VERSION 5.7 ;
  NOWIREEXTENSIONATPIN ON ;
  DIVIDERCHAR "/" ;
  BUSBITCHARS "[]" ;
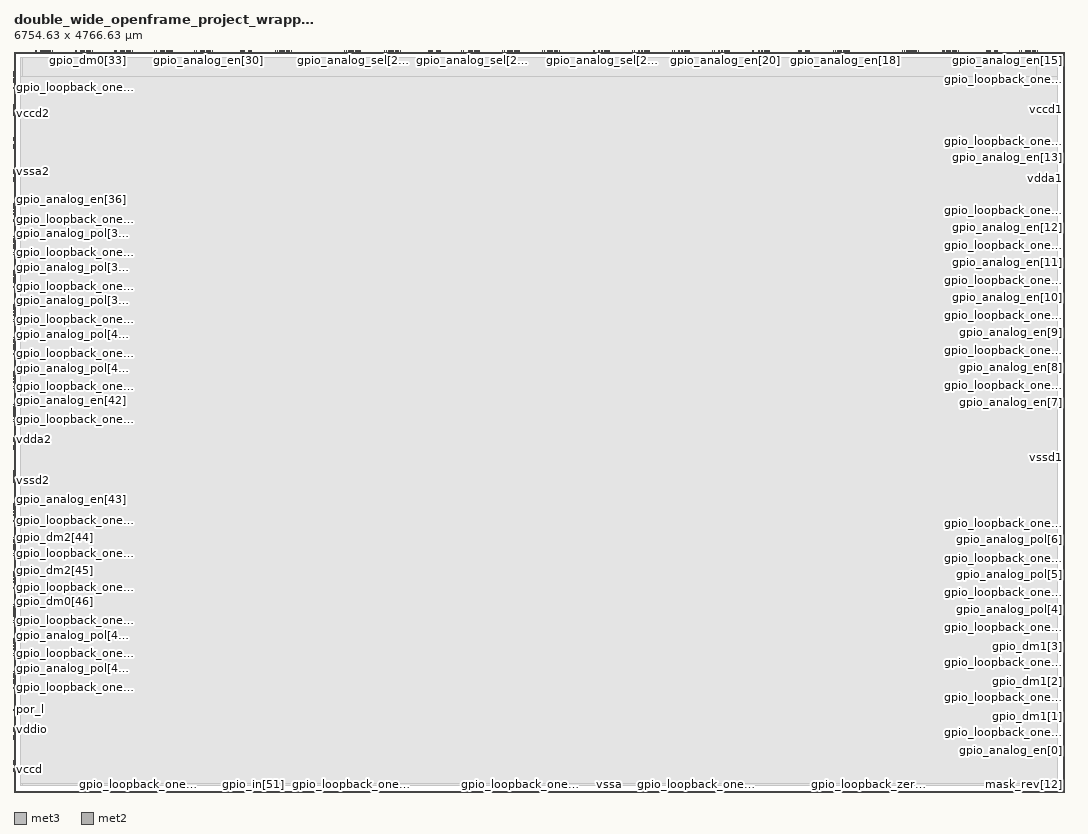
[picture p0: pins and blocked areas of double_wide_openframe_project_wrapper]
MACRO double_wide_openframe_project_wrapper
  CLASS BLOCK ;
  FOREIGN double_wide_openframe_project_wrapper ;
  ORIGIN 0.000 0.000 ;
  SIZE 6754.630 BY 4766.630 ;
  PIN analog_io[0]
    DIRECTION INOUT ;
    USE SIGNAL ;
    PORT
      LAYER met3 ;
        RECT 6754.330 306.190 6756.630 306.830 ;
    END
  END analog_io[0]
  PIN analog_io[10]
    DIRECTION INOUT ;
    USE SIGNAL ;
    PORT
      LAYER met3 ;
        RECT 6754.330 3222.190 6756.630 3222.830 ;
    END
  END analog_io[10]
  PIN analog_io[11]
    DIRECTION INOUT ;
    USE SIGNAL ;
    PORT
      LAYER met3 ;
        RECT 6754.330 3447.190 6756.630 3447.830 ;
    END
  END analog_io[11]
  PIN analog_io[12]
    DIRECTION INOUT ;
    USE SIGNAL ;
    PORT
      LAYER met3 ;
        RECT 6754.330 3672.190 6756.630 3672.830 ;
    END
  END analog_io[12]
  PIN analog_io[13]
    DIRECTION INOUT ;
    USE SIGNAL ;
    PORT
      LAYER met3 ;
        RECT 6754.330 4118.190 6756.630 4118.830 ;
    END
  END analog_io[13]
  PIN analog_io[14]
    DIRECTION INOUT ;
    USE SIGNAL ;
    PORT
      LAYER met3 ;
        RECT 6754.330 4564.190 6756.630 4564.830 ;
    END
  END analog_io[14]
  PIN analog_io[15]
    DIRECTION INOUT ;
    USE SIGNAL ;
    PORT
      LAYER met2 ;
        RECT 6569.800 4766.350 6570.440 4768.630 ;
    END
  END analog_io[15]
  PIN analog_io[16]
    DIRECTION INOUT ;
    USE SIGNAL ;
    PORT
      LAYER met2 ;
        RECT 6060.800 4766.350 6061.440 4768.630 ;
    END
  END analog_io[16]
  PIN analog_io[17]
    DIRECTION INOUT ;
    USE SIGNAL ;
    PORT
      LAYER met2 ;
        RECT 5803.800 4766.350 5804.440 4768.630 ;
    END
  END analog_io[17]
  PIN analog_io[18]
    DIRECTION INOUT ;
    USE SIGNAL ;
    PORT
      LAYER met2 ;
        RECT 5358.800 4766.350 5359.440 4768.630 ;
    END
  END analog_io[18]
  PIN analog_io[19]
    DIRECTION INOUT ;
    USE SIGNAL ;
    PORT
      LAYER met2 ;
        RECT 4849.800 4766.350 4850.440 4768.630 ;
    END
  END analog_io[19]
  PIN analog_io[1]
    DIRECTION INOUT ;
    USE SIGNAL ;
    PORT
      LAYER met3 ;
        RECT 6754.330 532.190 6756.630 532.830 ;
    END
  END analog_io[1]
  PIN analog_io[20]
    DIRECTION INOUT ;
    USE SIGNAL ;
    PORT
      LAYER met2 ;
        RECT 4591.800 4766.350 4592.440 4768.630 ;
    END
  END analog_io[20]
  PIN analog_io[21]
    DIRECTION INOUT ;
    USE SIGNAL ;
    PORT
      LAYER met2 ;
        RECT 4334.800 4766.350 4335.440 4768.630 ;
    END
  END analog_io[21]
  PIN analog_io[22]
    DIRECTION INOUT ;
    USE SIGNAL ;
    PORT
      LAYER met2 ;
        RECT 4077.800 4766.350 4078.440 4768.630 ;
    END
  END analog_io[22]
  PIN analog_io[23]
    DIRECTION INOUT ;
    USE SIGNAL ;
    PORT
      LAYER met2 ;
        RECT 3820.800 4766.350 3821.440 4768.630 ;
    END
  END analog_io[23]
  PIN analog_io[24]
    DIRECTION INOUT ;
    USE SIGNAL ;
    PORT
      LAYER met2 ;
        RECT 3495.800 4766.350 3496.440 4768.630 ;
    END
  END analog_io[24]
  PIN analog_io[25]
    DIRECTION INOUT ;
    USE SIGNAL ;
    PORT
      LAYER met2 ;
        RECT 3238.800 4766.350 3239.440 4768.630 ;
    END
  END analog_io[25]
  PIN analog_io[26]
    DIRECTION INOUT ;
    USE SIGNAL ;
    PORT
      LAYER met2 ;
        RECT 2981.800 4766.350 2982.440 4768.630 ;
    END
  END analog_io[26]
  PIN analog_io[27]
    DIRECTION INOUT ;
    USE SIGNAL ;
    PORT
      LAYER met2 ;
        RECT 2472.800 4766.350 2473.440 4768.630 ;
    END
  END analog_io[27]
  PIN analog_io[28]
    DIRECTION INOUT ;
    USE SIGNAL ;
    PORT
      LAYER met2 ;
        RECT 2215.800 4766.350 2216.440 4768.630 ;
    END
  END analog_io[28]
  PIN analog_io[29]
    DIRECTION INOUT ;
    USE SIGNAL ;
    PORT
      LAYER met2 ;
        RECT 1770.800 4766.350 1771.440 4768.630 ;
    END
  END analog_io[29]
  PIN analog_io[2]
    DIRECTION INOUT ;
    USE SIGNAL ;
    PORT
      LAYER met3 ;
        RECT 6754.330 757.190 6756.630 757.830 ;
    END
  END analog_io[2]
  PIN analog_io[30]
    DIRECTION INOUT ;
    USE SIGNAL ;
    PORT
      LAYER met2 ;
        RECT 1261.800 4766.350 1262.440 4768.630 ;
    END
  END analog_io[30]
  PIN analog_io[31]
    DIRECTION INOUT ;
    USE SIGNAL ;
    PORT
      LAYER met2 ;
        RECT 1003.800 4766.350 1004.440 4768.630 ;
    END
  END analog_io[31]
  PIN analog_io[32]
    DIRECTION INOUT ;
    USE SIGNAL ;
    PORT
      LAYER met2 ;
        RECT 746.800 4766.350 747.440 4768.630 ;
    END
  END analog_io[32]
  PIN analog_io[33]
    DIRECTION INOUT ;
    USE SIGNAL ;
    PORT
      LAYER met2 ;
        RECT 489.800 4766.350 490.440 4768.630 ;
    END
  END analog_io[33]
  PIN analog_io[34]
    DIRECTION INOUT ;
    USE SIGNAL ;
    PORT
      LAYER met2 ;
        RECT 232.800 4766.350 233.440 4768.630 ;
    END
  END analog_io[34]
  PIN analog_io[35]
    DIRECTION INOUT ;
    USE SIGNAL ;
    PORT
      LAYER met3 ;
        RECT -2.000 4622.800 0.300 4623.440 ;
    END
  END analog_io[35]
  PIN analog_io[36]
    DIRECTION INOUT ;
    USE SIGNAL ;
    PORT
      LAYER met3 ;
        RECT -2.000 3773.800 0.300 3774.440 ;
    END
  END analog_io[36]
  PIN analog_io[37]
    DIRECTION INOUT ;
    USE SIGNAL ;
    PORT
      LAYER met3 ;
        RECT -2.000 3557.800 0.300 3558.440 ;
    END
  END analog_io[37]
  PIN analog_io[38]
    DIRECTION INOUT ;
    USE SIGNAL ;
    PORT
      LAYER met3 ;
        RECT -2.000 3341.800 0.300 3342.440 ;
    END
  END analog_io[38]
  PIN analog_io[39]
    DIRECTION INOUT ;
    USE SIGNAL ;
    PORT
      LAYER met3 ;
        RECT -2.000 3125.800 0.300 3126.440 ;
    END
  END analog_io[39]
  PIN analog_io[3]
    DIRECTION INOUT ;
    USE SIGNAL ;
    PORT
      LAYER met3 ;
        RECT 6754.330 983.190 6756.630 983.830 ;
    END
  END analog_io[3]
  PIN analog_io[40]
    DIRECTION INOUT ;
    USE SIGNAL ;
    PORT
      LAYER met3 ;
        RECT -2.000 2909.800 0.300 2910.440 ;
    END
  END analog_io[40]
  PIN analog_io[41]
    DIRECTION INOUT ;
    USE SIGNAL ;
    PORT
      LAYER met3 ;
        RECT -2.000 2693.800 0.300 2694.440 ;
    END
  END analog_io[41]
  PIN analog_io[42]
    DIRECTION INOUT ;
    USE SIGNAL ;
    PORT
      LAYER met3 ;
        RECT -2.000 2477.800 0.300 2478.440 ;
    END
  END analog_io[42]
  PIN analog_io[43]
    DIRECTION INOUT ;
    USE SIGNAL ;
    PORT
      LAYER met3 ;
        RECT -2.000 1839.800 0.300 1840.440 ;
    END
  END analog_io[43]
  PIN analog_io[44]
    DIRECTION INOUT ;
    USE SIGNAL ;
    PORT
      LAYER met3 ;
        RECT -2.000 1623.800 0.300 1624.440 ;
    END
  END analog_io[44]
  PIN analog_io[45]
    DIRECTION INOUT ;
    USE SIGNAL ;
    PORT
      LAYER met3 ;
        RECT -2.000 1407.800 0.300 1408.440 ;
    END
  END analog_io[45]
  PIN analog_io[46]
    DIRECTION INOUT ;
    USE SIGNAL ;
    PORT
      LAYER met3 ;
        RECT -2.000 1191.800 0.300 1192.440 ;
    END
  END analog_io[46]
  PIN analog_io[47]
    DIRECTION INOUT ;
    USE SIGNAL ;
    PORT
      LAYER met3 ;
        RECT -2.000 975.800 0.300 976.440 ;
    END
  END analog_io[47]
  PIN analog_io[48]
    DIRECTION INOUT ;
    USE SIGNAL ;
    PORT
      LAYER met3 ;
        RECT -2.000 759.800 0.300 760.440 ;
    END
  END analog_io[48]
  PIN analog_io[49]
    DIRECTION INOUT ;
    USE SIGNAL ;
    PORT
      LAYER met2 ;
        RECT 738.190 -2.000 738.830 0.280 ;
    END
  END analog_io[49]
  PIN analog_io[4]
    DIRECTION INOUT ;
    USE SIGNAL ;
    PORT
      LAYER met3 ;
        RECT 6754.330 1208.190 6756.630 1208.830 ;
    END
  END analog_io[4]
  PIN analog_io[50]
    DIRECTION INOUT ;
    USE SIGNAL ;
    PORT
      LAYER met2 ;
        RECT 1281.190 -2.000 1281.830 0.280 ;
    END
  END analog_io[50]
  PIN analog_io[51]
    DIRECTION INOUT ;
    USE SIGNAL ;
    PORT
      LAYER met2 ;
        RECT 1555.190 -2.000 1555.830 0.280 ;
    END
  END analog_io[51]
  PIN analog_io[52]
    DIRECTION INOUT ;
    USE SIGNAL ;
    PORT
      LAYER met2 ;
        RECT 1829.190 -2.000 1829.830 0.280 ;
    END
  END analog_io[52]
  PIN analog_io[53]
    DIRECTION INOUT ;
    USE SIGNAL ;
    PORT
      LAYER met2 ;
        RECT 2103.190 -2.000 2103.830 0.280 ;
    END
  END analog_io[53]
  PIN analog_io[54]
    DIRECTION INOUT ;
    USE SIGNAL ;
    PORT
      LAYER met2 ;
        RECT 2377.190 -2.000 2377.830 0.280 ;
    END
  END analog_io[54]
  PIN analog_io[55]
    DIRECTION INOUT ;
    USE SIGNAL ;
    PORT
      LAYER met2 ;
        RECT 3191.670 -2.000 3192.310 0.280 ;
    END
  END analog_io[55]
  PIN analog_io[56]
    DIRECTION INOUT ;
    USE SIGNAL ;
    PORT
      LAYER met2 ;
        RECT 3465.670 -2.000 3466.310 0.280 ;
    END
  END analog_io[56]
  PIN analog_io[57]
    DIRECTION INOUT ;
    USE SIGNAL ;
    PORT
      LAYER met2 ;
        RECT 4326.190 -2.000 4326.830 0.280 ;
    END
  END analog_io[57]
  PIN analog_io[58]
    DIRECTION INOUT ;
    USE SIGNAL ;
    PORT
      LAYER met2 ;
        RECT 4869.190 -2.000 4869.830 0.280 ;
    END
  END analog_io[58]
  PIN analog_io[59]
    DIRECTION INOUT ;
    USE SIGNAL ;
    PORT
      LAYER met2 ;
        RECT 5143.190 -2.000 5143.830 0.280 ;
    END
  END analog_io[59]
  PIN analog_io[5]
    DIRECTION INOUT ;
    USE SIGNAL ;
    PORT
      LAYER met3 ;
        RECT 6754.330 1433.190 6756.630 1433.830 ;
    END
  END analog_io[5]
  PIN analog_io[60]
    DIRECTION INOUT ;
    USE SIGNAL ;
    PORT
      LAYER met2 ;
        RECT 5417.190 -2.000 5417.830 0.280 ;
    END
  END analog_io[60]
  PIN analog_io[61]
    DIRECTION INOUT ;
    USE SIGNAL ;
    PORT
      LAYER met2 ;
        RECT 5691.190 -2.000 5691.830 0.280 ;
    END
  END analog_io[61]
  PIN analog_io[62]
    DIRECTION INOUT ;
    USE SIGNAL ;
    PORT
      LAYER met2 ;
        RECT 5965.190 -2.000 5965.830 0.280 ;
    END
  END analog_io[62]
  PIN analog_io[6]
    DIRECTION INOUT ;
    USE SIGNAL ;
    PORT
      LAYER met3 ;
        RECT 6754.330 1659.190 6756.630 1659.830 ;
    END
  END analog_io[6]
  PIN analog_io[7]
    DIRECTION INOUT ;
    USE SIGNAL ;
    PORT
      LAYER met3 ;
        RECT 6754.330 2545.190 6756.630 2545.830 ;
    END
  END analog_io[7]
  PIN analog_io[8]
    DIRECTION INOUT ;
    USE SIGNAL ;
    PORT
      LAYER met3 ;
        RECT 6754.330 2771.190 6756.630 2771.830 ;
    END
  END analog_io[8]
  PIN analog_io[9]
    DIRECTION INOUT ;
    USE SIGNAL ;
    PORT
      LAYER met3 ;
        RECT 6754.330 2996.190 6756.630 2996.830 ;
    END
  END analog_io[9]
  PIN analog_noesd_io[0]
    DIRECTION INOUT ;
    USE SIGNAL ;
    PORT
      LAYER met3 ;
        RECT 6754.330 315.175 6756.630 316.245 ;
    END
  END analog_noesd_io[0]
  PIN analog_noesd_io[10]
    DIRECTION INOUT ;
    USE SIGNAL ;
    PORT
      LAYER met3 ;
        RECT 6754.330 3231.175 6756.630 3232.245 ;
    END
  END analog_noesd_io[10]
  PIN analog_noesd_io[11]
    DIRECTION INOUT ;
    USE SIGNAL ;
    PORT
      LAYER met3 ;
        RECT 6754.330 3456.175 6756.630 3457.245 ;
    END
  END analog_noesd_io[11]
  PIN analog_noesd_io[12]
    DIRECTION INOUT ;
    USE SIGNAL ;
    PORT
      LAYER met3 ;
        RECT 6754.330 3681.175 6756.630 3682.245 ;
    END
  END analog_noesd_io[12]
  PIN analog_noesd_io[13]
    DIRECTION INOUT ;
    USE SIGNAL ;
    PORT
      LAYER met3 ;
        RECT 6754.330 4127.175 6756.630 4128.245 ;
    END
  END analog_noesd_io[13]
  PIN analog_noesd_io[14]
    DIRECTION INOUT ;
    USE SIGNAL ;
    PORT
      LAYER met3 ;
        RECT 6754.330 4573.175 6756.630 4574.245 ;
    END
  END analog_noesd_io[14]
  PIN analog_noesd_io[15]
    DIRECTION INOUT ;
    USE SIGNAL ;
    PORT
      LAYER met2 ;
        RECT 6560.385 4766.350 6561.455 4768.630 ;
    END
  END analog_noesd_io[15]
  PIN analog_noesd_io[16]
    DIRECTION INOUT ;
    USE SIGNAL ;
    PORT
      LAYER met2 ;
        RECT 6051.385 4766.350 6052.455 4768.630 ;
    END
  END analog_noesd_io[16]
  PIN analog_noesd_io[17]
    DIRECTION INOUT ;
    USE SIGNAL ;
    PORT
      LAYER met2 ;
        RECT 5794.385 4766.350 5795.455 4768.630 ;
    END
  END analog_noesd_io[17]
  PIN analog_noesd_io[18]
    DIRECTION INOUT ;
    USE SIGNAL ;
    PORT
      LAYER met2 ;
        RECT 5349.385 4766.350 5350.455 4768.630 ;
    END
  END analog_noesd_io[18]
  PIN analog_noesd_io[19]
    DIRECTION INOUT ;
    USE SIGNAL ;
    PORT
      LAYER met2 ;
        RECT 4840.385 4766.350 4841.455 4768.630 ;
    END
  END analog_noesd_io[19]
  PIN analog_noesd_io[1]
    DIRECTION INOUT ;
    USE SIGNAL ;
    PORT
      LAYER met3 ;
        RECT 6754.330 541.175 6756.630 542.245 ;
    END
  END analog_noesd_io[1]
  PIN analog_noesd_io[20]
    DIRECTION INOUT ;
    USE SIGNAL ;
    PORT
      LAYER met2 ;
        RECT 4582.385 4766.350 4583.455 4768.630 ;
    END
  END analog_noesd_io[20]
  PIN analog_noesd_io[21]
    DIRECTION INOUT ;
    USE SIGNAL ;
    PORT
      LAYER met2 ;
        RECT 4325.385 4766.350 4326.455 4768.630 ;
    END
  END analog_noesd_io[21]
  PIN analog_noesd_io[22]
    DIRECTION INOUT ;
    USE SIGNAL ;
    PORT
      LAYER met2 ;
        RECT 4068.385 4766.350 4069.455 4768.630 ;
    END
  END analog_noesd_io[22]
  PIN analog_noesd_io[23]
    DIRECTION INOUT ;
    USE SIGNAL ;
    PORT
      LAYER met2 ;
        RECT 3811.385 4766.350 3812.455 4768.630 ;
    END
  END analog_noesd_io[23]
  PIN analog_noesd_io[24]
    DIRECTION INOUT ;
    USE SIGNAL ;
    PORT
      LAYER met2 ;
        RECT 3486.385 4766.350 3487.455 4768.630 ;
    END
  END analog_noesd_io[24]
  PIN analog_noesd_io[25]
    DIRECTION INOUT ;
    USE SIGNAL ;
    PORT
      LAYER met2 ;
        RECT 3229.385 4766.350 3230.455 4768.630 ;
    END
  END analog_noesd_io[25]
  PIN analog_noesd_io[26]
    DIRECTION INOUT ;
    USE SIGNAL ;
    PORT
      LAYER met2 ;
        RECT 2972.385 4766.350 2973.455 4768.630 ;
    END
  END analog_noesd_io[26]
  PIN analog_noesd_io[27]
    DIRECTION INOUT ;
    USE SIGNAL ;
    PORT
      LAYER met2 ;
        RECT 2463.385 4766.350 2464.455 4768.630 ;
    END
  END analog_noesd_io[27]
  PIN analog_noesd_io[28]
    DIRECTION INOUT ;
    USE SIGNAL ;
    PORT
      LAYER met2 ;
        RECT 2206.385 4766.350 2207.455 4768.630 ;
    END
  END analog_noesd_io[28]
  PIN analog_noesd_io[29]
    DIRECTION INOUT ;
    USE SIGNAL ;
    PORT
      LAYER met2 ;
        RECT 1761.385 4766.350 1762.455 4768.630 ;
    END
  END analog_noesd_io[29]
  PIN analog_noesd_io[2]
    DIRECTION INOUT ;
    USE SIGNAL ;
    PORT
      LAYER met3 ;
        RECT 6754.330 766.175 6756.630 767.245 ;
    END
  END analog_noesd_io[2]
  PIN analog_noesd_io[30]
    DIRECTION INOUT ;
    USE SIGNAL ;
    PORT
      LAYER met2 ;
        RECT 1252.385 4766.350 1253.455 4768.630 ;
    END
  END analog_noesd_io[30]
  PIN analog_noesd_io[31]
    DIRECTION INOUT ;
    USE SIGNAL ;
    PORT
      LAYER met2 ;
        RECT 994.385 4766.350 995.455 4768.630 ;
    END
  END analog_noesd_io[31]
  PIN analog_noesd_io[32]
    DIRECTION INOUT ;
    USE SIGNAL ;
    PORT
      LAYER met2 ;
        RECT 737.385 4766.350 738.455 4768.630 ;
    END
  END analog_noesd_io[32]
  PIN analog_noesd_io[33]
    DIRECTION INOUT ;
    USE SIGNAL ;
    PORT
      LAYER met2 ;
        RECT 480.385 4766.350 481.455 4768.630 ;
    END
  END analog_noesd_io[33]
  PIN analog_noesd_io[34]
    DIRECTION INOUT ;
    USE SIGNAL ;
    PORT
      LAYER met2 ;
        RECT 223.385 4766.350 224.455 4768.630 ;
    END
  END analog_noesd_io[34]
  PIN analog_noesd_io[35]
    DIRECTION INOUT ;
    USE SIGNAL ;
    PORT
      LAYER met3 ;
        RECT -2.000 4613.385 0.300 4614.455 ;
    END
  END analog_noesd_io[35]
  PIN analog_noesd_io[36]
    DIRECTION INOUT ;
    USE SIGNAL ;
    PORT
      LAYER met3 ;
        RECT -2.000 3764.385 0.300 3765.455 ;
    END
  END analog_noesd_io[36]
  PIN analog_noesd_io[37]
    DIRECTION INOUT ;
    USE SIGNAL ;
    PORT
      LAYER met3 ;
        RECT -2.000 3548.385 0.300 3549.455 ;
    END
  END analog_noesd_io[37]
  PIN analog_noesd_io[38]
    DIRECTION INOUT ;
    USE SIGNAL ;
    PORT
      LAYER met3 ;
        RECT -2.000 3332.385 0.300 3333.455 ;
    END
  END analog_noesd_io[38]
  PIN analog_noesd_io[39]
    DIRECTION INOUT ;
    USE SIGNAL ;
    PORT
      LAYER met3 ;
        RECT -2.000 3116.385 0.300 3117.455 ;
    END
  END analog_noesd_io[39]
  PIN analog_noesd_io[3]
    DIRECTION INOUT ;
    USE SIGNAL ;
    PORT
      LAYER met3 ;
        RECT 6754.330 992.175 6756.630 993.245 ;
    END
  END analog_noesd_io[3]
  PIN analog_noesd_io[40]
    DIRECTION INOUT ;
    USE SIGNAL ;
    PORT
      LAYER met3 ;
        RECT -2.000 2900.385 0.300 2901.455 ;
    END
  END analog_noesd_io[40]
  PIN analog_noesd_io[41]
    DIRECTION INOUT ;
    USE SIGNAL ;
    PORT
      LAYER met3 ;
        RECT -2.000 2684.385 0.300 2685.455 ;
    END
  END analog_noesd_io[41]
  PIN analog_noesd_io[42]
    DIRECTION INOUT ;
    USE SIGNAL ;
    PORT
      LAYER met3 ;
        RECT -2.000 2468.385 0.300 2469.455 ;
    END
  END analog_noesd_io[42]
  PIN analog_noesd_io[43]
    DIRECTION INOUT ;
    USE SIGNAL ;
    PORT
      LAYER met3 ;
        RECT -2.000 1830.385 0.300 1831.455 ;
    END
  END analog_noesd_io[43]
  PIN analog_noesd_io[44]
    DIRECTION INOUT ;
    USE SIGNAL ;
    PORT
      LAYER met3 ;
        RECT -2.000 1614.385 0.300 1615.455 ;
    END
  END analog_noesd_io[44]
  PIN analog_noesd_io[45]
    DIRECTION INOUT ;
    USE SIGNAL ;
    PORT
      LAYER met3 ;
        RECT -2.000 1398.385 0.300 1399.455 ;
    END
  END analog_noesd_io[45]
  PIN analog_noesd_io[46]
    DIRECTION INOUT ;
    USE SIGNAL ;
    PORT
      LAYER met3 ;
        RECT -2.000 1182.385 0.300 1183.455 ;
    END
  END analog_noesd_io[46]
  PIN analog_noesd_io[47]
    DIRECTION INOUT ;
    USE SIGNAL ;
    PORT
      LAYER met3 ;
        RECT -2.000 966.385 0.300 967.455 ;
    END
  END analog_noesd_io[47]
  PIN analog_noesd_io[48]
    DIRECTION INOUT ;
    USE SIGNAL ;
    PORT
      LAYER met3 ;
        RECT -2.000 750.385 0.300 751.455 ;
    END
  END analog_noesd_io[48]
  PIN analog_noesd_io[49]
    DIRECTION INOUT ;
    USE SIGNAL ;
    PORT
      LAYER met2 ;
        RECT 747.175 -2.000 748.245 0.280 ;
    END
  END analog_noesd_io[49]
  PIN analog_noesd_io[4]
    DIRECTION INOUT ;
    USE SIGNAL ;
    PORT
      LAYER met3 ;
        RECT 6754.330 1217.175 6756.630 1218.245 ;
    END
  END analog_noesd_io[4]
  PIN analog_noesd_io[50]
    DIRECTION INOUT ;
    USE SIGNAL ;
    PORT
      LAYER met2 ;
        RECT 1290.175 -2.000 1291.245 0.280 ;
    END
  END analog_noesd_io[50]
  PIN analog_noesd_io[51]
    DIRECTION INOUT ;
    USE SIGNAL ;
    PORT
      LAYER met2 ;
        RECT 1564.175 -2.000 1565.245 0.280 ;
    END
  END analog_noesd_io[51]
  PIN analog_noesd_io[52]
    DIRECTION INOUT ;
    USE SIGNAL ;
    PORT
      LAYER met2 ;
        RECT 1838.175 -2.000 1839.245 0.280 ;
    END
  END analog_noesd_io[52]
  PIN analog_noesd_io[53]
    DIRECTION INOUT ;
    USE SIGNAL ;
    PORT
      LAYER met2 ;
        RECT 2112.175 -2.000 2113.245 0.280 ;
    END
  END analog_noesd_io[53]
  PIN analog_noesd_io[54]
    DIRECTION INOUT ;
    USE SIGNAL ;
    PORT
      LAYER met2 ;
        RECT 2386.175 -2.000 2387.245 0.280 ;
    END
  END analog_noesd_io[54]
  PIN analog_noesd_io[55]
    DIRECTION INOUT ;
    USE SIGNAL ;
    PORT
      LAYER met2 ;
        RECT 3200.655 -2.000 3201.725 0.280 ;
    END
  END analog_noesd_io[55]
  PIN analog_noesd_io[56]
    DIRECTION INOUT ;
    USE SIGNAL ;
    PORT
      LAYER met2 ;
        RECT 3474.655 -2.000 3475.725 0.280 ;
    END
  END analog_noesd_io[56]
  PIN analog_noesd_io[57]
    DIRECTION INOUT ;
    USE SIGNAL ;
    PORT
      LAYER met2 ;
        RECT 4335.175 -2.000 4336.245 0.280 ;
    END
  END analog_noesd_io[57]
  PIN analog_noesd_io[58]
    DIRECTION INOUT ;
    USE SIGNAL ;
    PORT
      LAYER met2 ;
        RECT 4878.175 -2.000 4879.245 0.280 ;
    END
  END analog_noesd_io[58]
  PIN analog_noesd_io[59]
    DIRECTION INOUT ;
    USE SIGNAL ;
    PORT
      LAYER met2 ;
        RECT 5152.175 -2.000 5153.245 0.280 ;
    END
  END analog_noesd_io[59]
  PIN analog_noesd_io[5]
    DIRECTION INOUT ;
    USE SIGNAL ;
    PORT
      LAYER met3 ;
        RECT 6754.330 1442.175 6756.630 1443.245 ;
    END
  END analog_noesd_io[5]
  PIN analog_noesd_io[60]
    DIRECTION INOUT ;
    USE SIGNAL ;
    PORT
      LAYER met2 ;
        RECT 5426.175 -2.000 5427.245 0.280 ;
    END
  END analog_noesd_io[60]
  PIN analog_noesd_io[61]
    DIRECTION INOUT ;
    USE SIGNAL ;
    PORT
      LAYER met2 ;
        RECT 5700.175 -2.000 5701.245 0.280 ;
    END
  END analog_noesd_io[61]
  PIN analog_noesd_io[62]
    DIRECTION INOUT ;
    USE SIGNAL ;
    PORT
      LAYER met2 ;
        RECT 5974.175 -2.000 5975.245 0.280 ;
    END
  END analog_noesd_io[62]
  PIN analog_noesd_io[6]
    DIRECTION INOUT ;
    USE SIGNAL ;
    PORT
      LAYER met3 ;
        RECT 6754.330 1668.175 6756.630 1669.245 ;
    END
  END analog_noesd_io[6]
  PIN analog_noesd_io[7]
    DIRECTION INOUT ;
    USE SIGNAL ;
    PORT
      LAYER met3 ;
        RECT 6754.330 2554.175 6756.630 2555.245 ;
    END
  END analog_noesd_io[7]
  PIN analog_noesd_io[8]
    DIRECTION INOUT ;
    USE SIGNAL ;
    PORT
      LAYER met3 ;
        RECT 6754.330 2780.175 6756.630 2781.245 ;
    END
  END analog_noesd_io[8]
  PIN analog_noesd_io[9]
    DIRECTION INOUT ;
    USE SIGNAL ;
    PORT
      LAYER met3 ;
        RECT 6754.330 3005.175 6756.630 3006.245 ;
    END
  END analog_noesd_io[9]
  PIN gpio_analog_en[0]
    DIRECTION OUTPUT ;
    USE SIGNAL ;
    PORT
      LAYER met3 ;
        RECT 6754.330 318.300 6756.630 318.650 ;
    END
  END gpio_analog_en[0]
  PIN gpio_analog_en[10]
    DIRECTION OUTPUT ;
    USE SIGNAL ;
    PORT
      LAYER met3 ;
        RECT 6754.330 3234.300 6756.630 3234.650 ;
    END
  END gpio_analog_en[10]
  PIN gpio_analog_en[11]
    DIRECTION OUTPUT ;
    USE SIGNAL ;
    PORT
      LAYER met3 ;
        RECT 6754.330 3459.300 6756.630 3459.650 ;
    END
  END gpio_analog_en[11]
  PIN gpio_analog_en[12]
    DIRECTION OUTPUT ;
    USE SIGNAL ;
    PORT
      LAYER met3 ;
        RECT 6754.330 3684.300 6756.630 3684.650 ;
    END
  END gpio_analog_en[12]
  PIN gpio_analog_en[13]
    DIRECTION OUTPUT ;
    USE SIGNAL ;
    PORT
      LAYER met3 ;
        RECT 6754.330 4130.300 6756.630 4130.650 ;
    END
  END gpio_analog_en[13]
  PIN gpio_analog_en[14]
    DIRECTION OUTPUT ;
    USE SIGNAL ;
    PORT
      LAYER met3 ;
        RECT 6754.330 4576.300 6756.630 4576.650 ;
    END
  END gpio_analog_en[14]
  PIN gpio_analog_en[15]
    DIRECTION OUTPUT ;
    USE SIGNAL ;
    PORT
      LAYER met2 ;
        RECT 6558.020 4766.350 6558.300 4768.630 ;
    END
  END gpio_analog_en[15]
  PIN gpio_analog_en[16]
    DIRECTION OUTPUT ;
    USE SIGNAL ;
    PORT
      LAYER met2 ;
        RECT 6049.020 4766.350 6049.300 4768.630 ;
    END
  END gpio_analog_en[16]
  PIN gpio_analog_en[17]
    DIRECTION OUTPUT ;
    USE SIGNAL ;
    PORT
      LAYER met2 ;
        RECT 5792.020 4766.350 5792.300 4768.630 ;
    END
  END gpio_analog_en[17]
  PIN gpio_analog_en[18]
    DIRECTION OUTPUT ;
    USE SIGNAL ;
    PORT
      LAYER met2 ;
        RECT 5347.020 4766.350 5347.300 4768.630 ;
    END
  END gpio_analog_en[18]
  PIN gpio_analog_en[19]
    DIRECTION OUTPUT ;
    USE SIGNAL ;
    PORT
      LAYER met2 ;
        RECT 4838.020 4766.350 4838.300 4768.630 ;
    END
  END gpio_analog_en[19]
  PIN gpio_analog_en[1]
    DIRECTION OUTPUT ;
    USE SIGNAL ;
    PORT
      LAYER met3 ;
        RECT 6754.330 544.300 6756.630 544.650 ;
    END
  END gpio_analog_en[1]
  PIN gpio_analog_en[20]
    DIRECTION OUTPUT ;
    USE SIGNAL ;
    PORT
      LAYER met2 ;
        RECT 4580.020 4766.350 4580.300 4768.630 ;
    END
  END gpio_analog_en[20]
  PIN gpio_analog_en[21]
    DIRECTION OUTPUT ;
    USE SIGNAL ;
    PORT
      LAYER met2 ;
        RECT 4323.020 4766.350 4323.300 4768.630 ;
    END
  END gpio_analog_en[21]
  PIN gpio_analog_en[22]
    DIRECTION OUTPUT ;
    USE SIGNAL ;
    PORT
      LAYER met2 ;
        RECT 4066.020 4766.350 4066.300 4768.630 ;
    END
  END gpio_analog_en[22]
  PIN gpio_analog_en[23]
    DIRECTION OUTPUT ;
    USE SIGNAL ;
    PORT
      LAYER met2 ;
        RECT 3809.020 4766.350 3809.300 4768.630 ;
    END
  END gpio_analog_en[23]
  PIN gpio_analog_en[24]
    DIRECTION OUTPUT ;
    USE SIGNAL ;
    PORT
      LAYER met2 ;
        RECT 3484.020 4766.350 3484.300 4768.630 ;
    END
  END gpio_analog_en[24]
  PIN gpio_analog_en[25]
    DIRECTION OUTPUT ;
    USE SIGNAL ;
    PORT
      LAYER met2 ;
        RECT 3227.020 4766.350 3227.300 4768.630 ;
    END
  END gpio_analog_en[25]
  PIN gpio_analog_en[26]
    DIRECTION OUTPUT ;
    USE SIGNAL ;
    PORT
      LAYER met2 ;
        RECT 2970.020 4766.350 2970.300 4768.630 ;
    END
  END gpio_analog_en[26]
  PIN gpio_analog_en[27]
    DIRECTION OUTPUT ;
    USE SIGNAL ;
    PORT
      LAYER met2 ;
        RECT 2461.020 4766.350 2461.300 4768.630 ;
    END
  END gpio_analog_en[27]
  PIN gpio_analog_en[28]
    DIRECTION OUTPUT ;
    USE SIGNAL ;
    PORT
      LAYER met2 ;
        RECT 2204.020 4766.350 2204.300 4768.630 ;
    END
  END gpio_analog_en[28]
  PIN gpio_analog_en[29]
    DIRECTION OUTPUT ;
    USE SIGNAL ;
    PORT
      LAYER met2 ;
        RECT 1759.020 4766.350 1759.300 4768.630 ;
    END
  END gpio_analog_en[29]
  PIN gpio_analog_en[2]
    DIRECTION OUTPUT ;
    USE SIGNAL ;
    PORT
      LAYER met3 ;
        RECT 6754.330 769.300 6756.630 769.650 ;
    END
  END gpio_analog_en[2]
  PIN gpio_analog_en[30]
    DIRECTION OUTPUT ;
    USE SIGNAL ;
    PORT
      LAYER met2 ;
        RECT 1250.020 4766.350 1250.300 4768.630 ;
    END
  END gpio_analog_en[30]
  PIN gpio_analog_en[31]
    DIRECTION OUTPUT ;
    USE SIGNAL ;
    PORT
      LAYER met2 ;
        RECT 992.020 4766.350 992.300 4768.630 ;
    END
  END gpio_analog_en[31]
  PIN gpio_analog_en[32]
    DIRECTION OUTPUT ;
    USE SIGNAL ;
    PORT
      LAYER met2 ;
        RECT 735.020 4766.350 735.300 4768.630 ;
    END
  END gpio_analog_en[32]
  PIN gpio_analog_en[33]
    DIRECTION OUTPUT ;
    USE SIGNAL ;
    PORT
      LAYER met2 ;
        RECT 478.020 4766.350 478.300 4768.630 ;
    END
  END gpio_analog_en[33]
  PIN gpio_analog_en[34]
    DIRECTION OUTPUT ;
    USE SIGNAL ;
    PORT
      LAYER met2 ;
        RECT 221.020 4766.350 221.300 4768.630 ;
    END
  END gpio_analog_en[34]
  PIN gpio_analog_en[35]
    DIRECTION OUTPUT ;
    USE SIGNAL ;
    PORT
      LAYER met3 ;
        RECT -2.000 4610.980 0.300 4611.330 ;
    END
  END gpio_analog_en[35]
  PIN gpio_analog_en[36]
    DIRECTION OUTPUT ;
    USE SIGNAL ;
    PORT
      LAYER met3 ;
        RECT -2.000 3761.980 0.300 3762.330 ;
    END
  END gpio_analog_en[36]
  PIN gpio_analog_en[37]
    DIRECTION OUTPUT ;
    USE SIGNAL ;
    PORT
      LAYER met3 ;
        RECT -2.000 3545.980 0.300 3546.330 ;
    END
  END gpio_analog_en[37]
  PIN gpio_analog_en[38]
    DIRECTION OUTPUT ;
    USE SIGNAL ;
    PORT
      LAYER met3 ;
        RECT -2.000 3329.980 0.300 3330.330 ;
    END
  END gpio_analog_en[38]
  PIN gpio_analog_en[39]
    DIRECTION OUTPUT ;
    USE SIGNAL ;
    PORT
      LAYER met3 ;
        RECT -2.000 3113.980 0.300 3114.330 ;
    END
  END gpio_analog_en[39]
  PIN gpio_analog_en[3]
    DIRECTION OUTPUT ;
    USE SIGNAL ;
    PORT
      LAYER met3 ;
        RECT 6754.330 995.300 6756.630 995.650 ;
    END
  END gpio_analog_en[3]
  PIN gpio_analog_en[40]
    DIRECTION OUTPUT ;
    USE SIGNAL ;
    PORT
      LAYER met3 ;
        RECT -2.000 2897.980 0.300 2898.330 ;
    END
  END gpio_analog_en[40]
  PIN gpio_analog_en[41]
    DIRECTION OUTPUT ;
    USE SIGNAL ;
    PORT
      LAYER met3 ;
        RECT -2.000 2681.980 0.300 2682.330 ;
    END
  END gpio_analog_en[41]
  PIN gpio_analog_en[42]
    DIRECTION OUTPUT ;
    USE SIGNAL ;
    PORT
      LAYER met3 ;
        RECT -2.000 2465.980 0.300 2466.330 ;
    END
  END gpio_analog_en[42]
  PIN gpio_analog_en[43]
    DIRECTION OUTPUT ;
    USE SIGNAL ;
    PORT
      LAYER met3 ;
        RECT -2.000 1827.980 0.300 1828.330 ;
    END
  END gpio_analog_en[43]
  PIN gpio_analog_en[44]
    DIRECTION OUTPUT ;
    USE SIGNAL ;
    PORT
      LAYER met3 ;
        RECT -2.000 1611.980 0.300 1612.330 ;
    END
  END gpio_analog_en[44]
  PIN gpio_analog_en[45]
    DIRECTION OUTPUT ;
    USE SIGNAL ;
    PORT
      LAYER met3 ;
        RECT -2.000 1395.980 0.300 1396.330 ;
    END
  END gpio_analog_en[45]
  PIN gpio_analog_en[46]
    DIRECTION OUTPUT ;
    USE SIGNAL ;
    PORT
      LAYER met3 ;
        RECT -2.000 1179.980 0.300 1180.330 ;
    END
  END gpio_analog_en[46]
  PIN gpio_analog_en[47]
    DIRECTION OUTPUT ;
    USE SIGNAL ;
    PORT
      LAYER met3 ;
        RECT -2.000 963.980 0.300 964.330 ;
    END
  END gpio_analog_en[47]
  PIN gpio_analog_en[48]
    DIRECTION OUTPUT ;
    USE SIGNAL ;
    PORT
      LAYER met3 ;
        RECT -2.000 747.980 0.300 748.330 ;
    END
  END gpio_analog_en[48]
  PIN gpio_analog_en[49]
    DIRECTION OUTPUT ;
    USE SIGNAL ;
    PORT
      LAYER met2 ;
        RECT 750.330 -2.000 750.610 0.280 ;
    END
  END gpio_analog_en[49]
  PIN gpio_analog_en[4]
    DIRECTION OUTPUT ;
    USE SIGNAL ;
    PORT
      LAYER met3 ;
        RECT 6754.330 1220.300 6756.630 1220.650 ;
    END
  END gpio_analog_en[4]
  PIN gpio_analog_en[50]
    DIRECTION OUTPUT ;
    USE SIGNAL ;
    PORT
      LAYER met2 ;
        RECT 1293.330 -2.000 1293.610 0.280 ;
    END
  END gpio_analog_en[50]
  PIN gpio_analog_en[51]
    DIRECTION OUTPUT ;
    USE SIGNAL ;
    PORT
      LAYER met2 ;
        RECT 1567.330 -2.000 1567.610 0.280 ;
    END
  END gpio_analog_en[51]
  PIN gpio_analog_en[52]
    DIRECTION OUTPUT ;
    USE SIGNAL ;
    PORT
      LAYER met2 ;
        RECT 1841.330 -2.000 1841.610 0.280 ;
    END
  END gpio_analog_en[52]
  PIN gpio_analog_en[53]
    DIRECTION OUTPUT ;
    USE SIGNAL ;
    PORT
      LAYER met2 ;
        RECT 2115.330 -2.000 2115.610 0.280 ;
    END
  END gpio_analog_en[53]
  PIN gpio_analog_en[54]
    DIRECTION OUTPUT ;
    USE SIGNAL ;
    PORT
      LAYER met2 ;
        RECT 2389.330 -2.000 2389.610 0.280 ;
    END
  END gpio_analog_en[54]
  PIN gpio_analog_en[55]
    DIRECTION OUTPUT ;
    USE SIGNAL ;
    PORT
      LAYER met2 ;
        RECT 3203.810 -2.000 3204.090 0.280 ;
    END
  END gpio_analog_en[55]
  PIN gpio_analog_en[56]
    DIRECTION OUTPUT ;
    USE SIGNAL ;
    PORT
      LAYER met2 ;
        RECT 3477.810 -2.000 3478.090 0.280 ;
    END
  END gpio_analog_en[56]
  PIN gpio_analog_en[57]
    DIRECTION OUTPUT ;
    USE SIGNAL ;
    PORT
      LAYER met2 ;
        RECT 4338.330 -2.000 4338.610 0.280 ;
    END
  END gpio_analog_en[57]
  PIN gpio_analog_en[58]
    DIRECTION OUTPUT ;
    USE SIGNAL ;
    PORT
      LAYER met2 ;
        RECT 4881.330 -2.000 4881.610 0.280 ;
    END
  END gpio_analog_en[58]
  PIN gpio_analog_en[59]
    DIRECTION OUTPUT ;
    USE SIGNAL ;
    PORT
      LAYER met2 ;
        RECT 5155.330 -2.000 5155.610 0.280 ;
    END
  END gpio_analog_en[59]
  PIN gpio_analog_en[5]
    DIRECTION OUTPUT ;
    USE SIGNAL ;
    PORT
      LAYER met3 ;
        RECT 6754.330 1445.300 6756.630 1445.650 ;
    END
  END gpio_analog_en[5]
  PIN gpio_analog_en[60]
    DIRECTION OUTPUT ;
    USE SIGNAL ;
    PORT
      LAYER met2 ;
        RECT 5429.330 -2.000 5429.610 0.280 ;
    END
  END gpio_analog_en[60]
  PIN gpio_analog_en[61]
    DIRECTION OUTPUT ;
    USE SIGNAL ;
    PORT
      LAYER met2 ;
        RECT 5703.330 -2.000 5703.610 0.280 ;
    END
  END gpio_analog_en[61]
  PIN gpio_analog_en[62]
    DIRECTION OUTPUT ;
    USE SIGNAL ;
    PORT
      LAYER met2 ;
        RECT 5977.330 -2.000 5977.610 0.280 ;
    END
  END gpio_analog_en[62]
  PIN gpio_analog_en[6]
    DIRECTION OUTPUT ;
    USE SIGNAL ;
    PORT
      LAYER met3 ;
        RECT 6754.330 1671.300 6756.630 1671.650 ;
    END
  END gpio_analog_en[6]
  PIN gpio_analog_en[7]
    DIRECTION OUTPUT ;
    USE SIGNAL ;
    PORT
      LAYER met3 ;
        RECT 6754.330 2557.300 6756.630 2557.650 ;
    END
  END gpio_analog_en[7]
  PIN gpio_analog_en[8]
    DIRECTION OUTPUT ;
    USE SIGNAL ;
    PORT
      LAYER met3 ;
        RECT 6754.330 2783.300 6756.630 2783.650 ;
    END
  END gpio_analog_en[8]
  PIN gpio_analog_en[9]
    DIRECTION OUTPUT ;
    USE SIGNAL ;
    PORT
      LAYER met3 ;
        RECT 6754.330 3008.300 6756.630 3008.650 ;
    END
  END gpio_analog_en[9]
  PIN gpio_analog_pol[0]
    DIRECTION OUTPUT ;
    USE SIGNAL ;
    PORT
      LAYER met3 ;
        RECT 6754.330 324.740 6756.630 325.090 ;
    END
  END gpio_analog_pol[0]
  PIN gpio_analog_pol[10]
    DIRECTION OUTPUT ;
    USE SIGNAL ;
    PORT
      LAYER met3 ;
        RECT 6754.330 3240.740 6756.630 3241.090 ;
    END
  END gpio_analog_pol[10]
  PIN gpio_analog_pol[11]
    DIRECTION OUTPUT ;
    USE SIGNAL ;
    PORT
      LAYER met3 ;
        RECT 6754.330 3465.740 6756.630 3466.090 ;
    END
  END gpio_analog_pol[11]
  PIN gpio_analog_pol[12]
    DIRECTION OUTPUT ;
    USE SIGNAL ;
    PORT
      LAYER met3 ;
        RECT 6754.330 3690.740 6756.630 3691.090 ;
    END
  END gpio_analog_pol[12]
  PIN gpio_analog_pol[13]
    DIRECTION OUTPUT ;
    USE SIGNAL ;
    PORT
      LAYER met3 ;
        RECT 6754.330 4136.740 6756.630 4137.090 ;
    END
  END gpio_analog_pol[13]
  PIN gpio_analog_pol[14]
    DIRECTION OUTPUT ;
    USE SIGNAL ;
    PORT
      LAYER met3 ;
        RECT 6754.330 4582.740 6756.630 4583.090 ;
    END
  END gpio_analog_pol[14]
  PIN gpio_analog_pol[15]
    DIRECTION OUTPUT ;
    USE SIGNAL ;
    PORT
      LAYER met2 ;
        RECT 6551.580 4766.350 6551.860 4768.630 ;
    END
  END gpio_analog_pol[15]
  PIN gpio_analog_pol[16]
    DIRECTION OUTPUT ;
    USE SIGNAL ;
    PORT
      LAYER met2 ;
        RECT 6042.580 4766.350 6042.860 4768.630 ;
    END
  END gpio_analog_pol[16]
  PIN gpio_analog_pol[17]
    DIRECTION OUTPUT ;
    USE SIGNAL ;
    PORT
      LAYER met2 ;
        RECT 5785.580 4766.350 5785.860 4768.630 ;
    END
  END gpio_analog_pol[17]
  PIN gpio_analog_pol[18]
    DIRECTION OUTPUT ;
    USE SIGNAL ;
    PORT
      LAYER met2 ;
        RECT 5340.580 4766.350 5340.860 4768.630 ;
    END
  END gpio_analog_pol[18]
  PIN gpio_analog_pol[19]
    DIRECTION OUTPUT ;
    USE SIGNAL ;
    PORT
      LAYER met2 ;
        RECT 4831.580 4766.350 4831.860 4768.630 ;
    END
  END gpio_analog_pol[19]
  PIN gpio_analog_pol[1]
    DIRECTION OUTPUT ;
    USE SIGNAL ;
    PORT
      LAYER met3 ;
        RECT 6754.330 550.740 6756.630 551.090 ;
    END
  END gpio_analog_pol[1]
  PIN gpio_analog_pol[20]
    DIRECTION OUTPUT ;
    USE SIGNAL ;
    PORT
      LAYER met2 ;
        RECT 4573.580 4766.350 4573.860 4768.630 ;
    END
  END gpio_analog_pol[20]
  PIN gpio_analog_pol[21]
    DIRECTION OUTPUT ;
    USE SIGNAL ;
    PORT
      LAYER met2 ;
        RECT 4316.580 4766.350 4316.860 4768.630 ;
    END
  END gpio_analog_pol[21]
  PIN gpio_analog_pol[22]
    DIRECTION OUTPUT ;
    USE SIGNAL ;
    PORT
      LAYER met2 ;
        RECT 4059.580 4766.350 4059.860 4768.630 ;
    END
  END gpio_analog_pol[22]
  PIN gpio_analog_pol[23]
    DIRECTION OUTPUT ;
    USE SIGNAL ;
    PORT
      LAYER met2 ;
        RECT 3802.580 4766.350 3802.860 4768.630 ;
    END
  END gpio_analog_pol[23]
  PIN gpio_analog_pol[24]
    DIRECTION OUTPUT ;
    USE SIGNAL ;
    PORT
      LAYER met2 ;
        RECT 3477.580 4766.350 3477.860 4768.630 ;
    END
  END gpio_analog_pol[24]
  PIN gpio_analog_pol[25]
    DIRECTION OUTPUT ;
    USE SIGNAL ;
    PORT
      LAYER met2 ;
        RECT 3220.580 4766.350 3220.860 4768.630 ;
    END
  END gpio_analog_pol[25]
  PIN gpio_analog_pol[26]
    DIRECTION OUTPUT ;
    USE SIGNAL ;
    PORT
      LAYER met2 ;
        RECT 2963.580 4766.350 2963.860 4768.630 ;
    END
  END gpio_analog_pol[26]
  PIN gpio_analog_pol[27]
    DIRECTION OUTPUT ;
    USE SIGNAL ;
    PORT
      LAYER met2 ;
        RECT 2454.580 4766.350 2454.860 4768.630 ;
    END
  END gpio_analog_pol[27]
  PIN gpio_analog_pol[28]
    DIRECTION OUTPUT ;
    USE SIGNAL ;
    PORT
      LAYER met2 ;
        RECT 2197.580 4766.350 2197.860 4768.630 ;
    END
  END gpio_analog_pol[28]
  PIN gpio_analog_pol[29]
    DIRECTION OUTPUT ;
    USE SIGNAL ;
    PORT
      LAYER met2 ;
        RECT 1752.580 4766.350 1752.860 4768.630 ;
    END
  END gpio_analog_pol[29]
  PIN gpio_analog_pol[2]
    DIRECTION OUTPUT ;
    USE SIGNAL ;
    PORT
      LAYER met3 ;
        RECT 6754.330 775.740 6756.630 776.090 ;
    END
  END gpio_analog_pol[2]
  PIN gpio_analog_pol[30]
    DIRECTION OUTPUT ;
    USE SIGNAL ;
    PORT
      LAYER met2 ;
        RECT 1243.580 4766.350 1243.860 4768.630 ;
    END
  END gpio_analog_pol[30]
  PIN gpio_analog_pol[31]
    DIRECTION OUTPUT ;
    USE SIGNAL ;
    PORT
      LAYER met2 ;
        RECT 985.580 4766.350 985.860 4768.630 ;
    END
  END gpio_analog_pol[31]
  PIN gpio_analog_pol[32]
    DIRECTION OUTPUT ;
    USE SIGNAL ;
    PORT
      LAYER met2 ;
        RECT 728.580 4766.350 728.860 4768.630 ;
    END
  END gpio_analog_pol[32]
  PIN gpio_analog_pol[33]
    DIRECTION OUTPUT ;
    USE SIGNAL ;
    PORT
      LAYER met2 ;
        RECT 471.580 4766.350 471.860 4768.630 ;
    END
  END gpio_analog_pol[33]
  PIN gpio_analog_pol[34]
    DIRECTION OUTPUT ;
    USE SIGNAL ;
    PORT
      LAYER met2 ;
        RECT 214.580 4766.350 214.860 4768.630 ;
    END
  END gpio_analog_pol[34]
  PIN gpio_analog_pol[35]
    DIRECTION OUTPUT ;
    USE SIGNAL ;
    PORT
      LAYER met3 ;
        RECT -2.000 4604.540 0.300 4604.890 ;
    END
  END gpio_analog_pol[35]
  PIN gpio_analog_pol[36]
    DIRECTION OUTPUT ;
    USE SIGNAL ;
    PORT
      LAYER met3 ;
        RECT -2.000 3755.540 0.300 3755.890 ;
    END
  END gpio_analog_pol[36]
  PIN gpio_analog_pol[37]
    DIRECTION OUTPUT ;
    USE SIGNAL ;
    PORT
      LAYER met3 ;
        RECT -2.000 3539.540 0.300 3539.890 ;
    END
  END gpio_analog_pol[37]
  PIN gpio_analog_pol[38]
    DIRECTION OUTPUT ;
    USE SIGNAL ;
    PORT
      LAYER met3 ;
        RECT -2.000 3323.540 0.300 3323.890 ;
    END
  END gpio_analog_pol[38]
  PIN gpio_analog_pol[39]
    DIRECTION OUTPUT ;
    USE SIGNAL ;
    PORT
      LAYER met3 ;
        RECT -2.000 3107.540 0.300 3107.890 ;
    END
  END gpio_analog_pol[39]
  PIN gpio_analog_pol[3]
    DIRECTION OUTPUT ;
    USE SIGNAL ;
    PORT
      LAYER met3 ;
        RECT 6754.330 1001.740 6756.630 1002.090 ;
    END
  END gpio_analog_pol[3]
  PIN gpio_analog_pol[40]
    DIRECTION OUTPUT ;
    USE SIGNAL ;
    PORT
      LAYER met3 ;
        RECT -2.000 2891.540 0.300 2891.890 ;
    END
  END gpio_analog_pol[40]
  PIN gpio_analog_pol[41]
    DIRECTION OUTPUT ;
    USE SIGNAL ;
    PORT
      LAYER met3 ;
        RECT -2.000 2675.540 0.300 2675.890 ;
    END
  END gpio_analog_pol[41]
  PIN gpio_analog_pol[42]
    DIRECTION OUTPUT ;
    USE SIGNAL ;
    PORT
      LAYER met3 ;
        RECT -2.000 2459.540 0.300 2459.890 ;
    END
  END gpio_analog_pol[42]
  PIN gpio_analog_pol[43]
    DIRECTION OUTPUT ;
    USE SIGNAL ;
    PORT
      LAYER met3 ;
        RECT -2.000 1821.540 0.300 1821.890 ;
    END
  END gpio_analog_pol[43]
  PIN gpio_analog_pol[44]
    DIRECTION OUTPUT ;
    USE SIGNAL ;
    PORT
      LAYER met3 ;
        RECT -2.000 1605.540 0.300 1605.890 ;
    END
  END gpio_analog_pol[44]
  PIN gpio_analog_pol[45]
    DIRECTION OUTPUT ;
    USE SIGNAL ;
    PORT
      LAYER met3 ;
        RECT -2.000 1389.540 0.300 1389.890 ;
    END
  END gpio_analog_pol[45]
  PIN gpio_analog_pol[46]
    DIRECTION OUTPUT ;
    USE SIGNAL ;
    PORT
      LAYER met3 ;
        RECT -2.000 1173.540 0.300 1173.890 ;
    END
  END gpio_analog_pol[46]
  PIN gpio_analog_pol[47]
    DIRECTION OUTPUT ;
    USE SIGNAL ;
    PORT
      LAYER met3 ;
        RECT -2.000 957.540 0.300 957.890 ;
    END
  END gpio_analog_pol[47]
  PIN gpio_analog_pol[48]
    DIRECTION OUTPUT ;
    USE SIGNAL ;
    PORT
      LAYER met3 ;
        RECT -2.000 741.540 0.300 741.890 ;
    END
  END gpio_analog_pol[48]
  PIN gpio_analog_pol[49]
    DIRECTION OUTPUT ;
    USE SIGNAL ;
    PORT
      LAYER met2 ;
        RECT 756.770 -2.000 757.050 0.280 ;
    END
  END gpio_analog_pol[49]
  PIN gpio_analog_pol[4]
    DIRECTION OUTPUT ;
    USE SIGNAL ;
    PORT
      LAYER met3 ;
        RECT 6754.330 1226.740 6756.630 1227.090 ;
    END
  END gpio_analog_pol[4]
  PIN gpio_analog_pol[50]
    DIRECTION OUTPUT ;
    USE SIGNAL ;
    PORT
      LAYER met2 ;
        RECT 1299.770 -2.000 1300.050 0.280 ;
    END
  END gpio_analog_pol[50]
  PIN gpio_analog_pol[51]
    DIRECTION OUTPUT ;
    USE SIGNAL ;
    PORT
      LAYER met2 ;
        RECT 1573.770 -2.000 1574.050 0.280 ;
    END
  END gpio_analog_pol[51]
  PIN gpio_analog_pol[52]
    DIRECTION OUTPUT ;
    USE SIGNAL ;
    PORT
      LAYER met2 ;
        RECT 1847.770 -2.000 1848.050 0.280 ;
    END
  END gpio_analog_pol[52]
  PIN gpio_analog_pol[53]
    DIRECTION OUTPUT ;
    USE SIGNAL ;
    PORT
      LAYER met2 ;
        RECT 2121.770 -2.000 2122.050 0.280 ;
    END
  END gpio_analog_pol[53]
  PIN gpio_analog_pol[54]
    DIRECTION OUTPUT ;
    USE SIGNAL ;
    PORT
      LAYER met2 ;
        RECT 2395.770 -2.000 2396.050 0.280 ;
    END
  END gpio_analog_pol[54]
  PIN gpio_analog_pol[55]
    DIRECTION OUTPUT ;
    USE SIGNAL ;
    PORT
      LAYER met2 ;
        RECT 3210.250 -2.000 3210.530 0.280 ;
    END
  END gpio_analog_pol[55]
  PIN gpio_analog_pol[56]
    DIRECTION OUTPUT ;
    USE SIGNAL ;
    PORT
      LAYER met2 ;
        RECT 3484.250 -2.000 3484.530 0.280 ;
    END
  END gpio_analog_pol[56]
  PIN gpio_analog_pol[57]
    DIRECTION OUTPUT ;
    USE SIGNAL ;
    PORT
      LAYER met2 ;
        RECT 4344.770 -2.000 4345.050 0.280 ;
    END
  END gpio_analog_pol[57]
  PIN gpio_analog_pol[58]
    DIRECTION OUTPUT ;
    USE SIGNAL ;
    PORT
      LAYER met2 ;
        RECT 4887.770 -2.000 4888.050 0.280 ;
    END
  END gpio_analog_pol[58]
  PIN gpio_analog_pol[59]
    DIRECTION OUTPUT ;
    USE SIGNAL ;
    PORT
      LAYER met2 ;
        RECT 5161.770 -2.000 5162.050 0.280 ;
    END
  END gpio_analog_pol[59]
  PIN gpio_analog_pol[5]
    DIRECTION OUTPUT ;
    USE SIGNAL ;
    PORT
      LAYER met3 ;
        RECT 6754.330 1451.740 6756.630 1452.090 ;
    END
  END gpio_analog_pol[5]
  PIN gpio_analog_pol[60]
    DIRECTION OUTPUT ;
    USE SIGNAL ;
    PORT
      LAYER met2 ;
        RECT 5435.770 -2.000 5436.050 0.280 ;
    END
  END gpio_analog_pol[60]
  PIN gpio_analog_pol[61]
    DIRECTION OUTPUT ;
    USE SIGNAL ;
    PORT
      LAYER met2 ;
        RECT 5709.770 -2.000 5710.050 0.280 ;
    END
  END gpio_analog_pol[61]
  PIN gpio_analog_pol[62]
    DIRECTION OUTPUT ;
    USE SIGNAL ;
    PORT
      LAYER met2 ;
        RECT 5983.770 -2.000 5984.050 0.280 ;
    END
  END gpio_analog_pol[62]
  PIN gpio_analog_pol[6]
    DIRECTION OUTPUT ;
    USE SIGNAL ;
    PORT
      LAYER met3 ;
        RECT 6754.330 1677.740 6756.630 1678.090 ;
    END
  END gpio_analog_pol[6]
  PIN gpio_analog_pol[7]
    DIRECTION OUTPUT ;
    USE SIGNAL ;
    PORT
      LAYER met3 ;
        RECT 6754.330 2563.740 6756.630 2564.090 ;
    END
  END gpio_analog_pol[7]
  PIN gpio_analog_pol[8]
    DIRECTION OUTPUT ;
    USE SIGNAL ;
    PORT
      LAYER met3 ;
        RECT 6754.330 2789.740 6756.630 2790.090 ;
    END
  END gpio_analog_pol[8]
  PIN gpio_analog_pol[9]
    DIRECTION OUTPUT ;
    USE SIGNAL ;
    PORT
      LAYER met3 ;
        RECT 6754.330 3014.740 6756.630 3015.090 ;
    END
  END gpio_analog_pol[9]
  PIN gpio_analog_sel[0]
    DIRECTION OUTPUT ;
    USE SIGNAL ;
    PORT
      LAYER met3 ;
        RECT 6754.330 339.920 6756.630 340.270 ;
    END
  END gpio_analog_sel[0]
  PIN gpio_analog_sel[10]
    DIRECTION OUTPUT ;
    USE SIGNAL ;
    PORT
      LAYER met3 ;
        RECT 6754.330 3255.920 6756.630 3256.270 ;
    END
  END gpio_analog_sel[10]
  PIN gpio_analog_sel[11]
    DIRECTION OUTPUT ;
    USE SIGNAL ;
    PORT
      LAYER met3 ;
        RECT 6754.330 3480.920 6756.630 3481.270 ;
    END
  END gpio_analog_sel[11]
  PIN gpio_analog_sel[12]
    DIRECTION OUTPUT ;
    USE SIGNAL ;
    PORT
      LAYER met3 ;
        RECT 6754.330 3705.920 6756.630 3706.270 ;
    END
  END gpio_analog_sel[12]
  PIN gpio_analog_sel[13]
    DIRECTION OUTPUT ;
    USE SIGNAL ;
    PORT
      LAYER met3 ;
        RECT 6754.330 4151.920 6756.630 4152.270 ;
    END
  END gpio_analog_sel[13]
  PIN gpio_analog_sel[14]
    DIRECTION OUTPUT ;
    USE SIGNAL ;
    PORT
      LAYER met3 ;
        RECT 6754.330 4597.920 6756.630 4598.270 ;
    END
  END gpio_analog_sel[14]
  PIN gpio_analog_sel[15]
    DIRECTION OUTPUT ;
    USE SIGNAL ;
    PORT
      LAYER met2 ;
        RECT 6536.400 4766.350 6536.680 4768.630 ;
    END
  END gpio_analog_sel[15]
  PIN gpio_analog_sel[16]
    DIRECTION OUTPUT ;
    USE SIGNAL ;
    PORT
      LAYER met2 ;
        RECT 6027.400 4766.350 6027.680 4768.630 ;
    END
  END gpio_analog_sel[16]
  PIN gpio_analog_sel[17]
    DIRECTION OUTPUT ;
    USE SIGNAL ;
    PORT
      LAYER met2 ;
        RECT 5770.400 4766.350 5770.680 4768.630 ;
    END
  END gpio_analog_sel[17]
  PIN gpio_analog_sel[18]
    DIRECTION OUTPUT ;
    USE SIGNAL ;
    PORT
      LAYER met2 ;
        RECT 5325.400 4766.350 5325.680 4768.630 ;
    END
  END gpio_analog_sel[18]
  PIN gpio_analog_sel[19]
    DIRECTION OUTPUT ;
    USE SIGNAL ;
    PORT
      LAYER met2 ;
        RECT 4816.400 4766.350 4816.680 4768.630 ;
    END
  END gpio_analog_sel[19]
  PIN gpio_analog_sel[1]
    DIRECTION OUTPUT ;
    USE SIGNAL ;
    PORT
      LAYER met3 ;
        RECT 6754.330 565.920 6756.630 566.270 ;
    END
  END gpio_analog_sel[1]
  PIN gpio_analog_sel[20]
    DIRECTION OUTPUT ;
    USE SIGNAL ;
    PORT
      LAYER met2 ;
        RECT 4558.400 4766.350 4558.680 4768.630 ;
    END
  END gpio_analog_sel[20]
  PIN gpio_analog_sel[21]
    DIRECTION OUTPUT ;
    USE SIGNAL ;
    PORT
      LAYER met2 ;
        RECT 4301.400 4766.350 4301.680 4768.630 ;
    END
  END gpio_analog_sel[21]
  PIN gpio_analog_sel[22]
    DIRECTION OUTPUT ;
    USE SIGNAL ;
    PORT
      LAYER met2 ;
        RECT 4044.400 4766.350 4044.680 4768.630 ;
    END
  END gpio_analog_sel[22]
  PIN gpio_analog_sel[23]
    DIRECTION OUTPUT ;
    USE SIGNAL ;
    PORT
      LAYER met2 ;
        RECT 3787.400 4766.350 3787.680 4768.630 ;
    END
  END gpio_analog_sel[23]
  PIN gpio_analog_sel[24]
    DIRECTION OUTPUT ;
    USE SIGNAL ;
    PORT
      LAYER met2 ;
        RECT 3462.400 4766.350 3462.680 4768.630 ;
    END
  END gpio_analog_sel[24]
  PIN gpio_analog_sel[25]
    DIRECTION OUTPUT ;
    USE SIGNAL ;
    PORT
      LAYER met2 ;
        RECT 3205.400 4766.350 3205.680 4768.630 ;
    END
  END gpio_analog_sel[25]
  PIN gpio_analog_sel[26]
    DIRECTION OUTPUT ;
    USE SIGNAL ;
    PORT
      LAYER met2 ;
        RECT 2948.400 4766.350 2948.680 4768.630 ;
    END
  END gpio_analog_sel[26]
  PIN gpio_analog_sel[27]
    DIRECTION OUTPUT ;
    USE SIGNAL ;
    PORT
      LAYER met2 ;
        RECT 2439.400 4766.350 2439.680 4768.630 ;
    END
  END gpio_analog_sel[27]
  PIN gpio_analog_sel[28]
    DIRECTION OUTPUT ;
    USE SIGNAL ;
    PORT
      LAYER met2 ;
        RECT 2182.400 4766.350 2182.680 4768.630 ;
    END
  END gpio_analog_sel[28]
  PIN gpio_analog_sel[29]
    DIRECTION OUTPUT ;
    USE SIGNAL ;
    PORT
      LAYER met2 ;
        RECT 1737.400 4766.350 1737.680 4768.630 ;
    END
  END gpio_analog_sel[29]
  PIN gpio_analog_sel[2]
    DIRECTION OUTPUT ;
    USE SIGNAL ;
    PORT
      LAYER met3 ;
        RECT 6754.330 790.920 6756.630 791.270 ;
    END
  END gpio_analog_sel[2]
  PIN gpio_analog_sel[30]
    DIRECTION OUTPUT ;
    USE SIGNAL ;
    PORT
      LAYER met2 ;
        RECT 1228.400 4766.350 1228.680 4768.630 ;
    END
  END gpio_analog_sel[30]
  PIN gpio_analog_sel[31]
    DIRECTION OUTPUT ;
    USE SIGNAL ;
    PORT
      LAYER met2 ;
        RECT 970.400 4766.350 970.680 4768.630 ;
    END
  END gpio_analog_sel[31]
  PIN gpio_analog_sel[32]
    DIRECTION OUTPUT ;
    USE SIGNAL ;
    PORT
      LAYER met2 ;
        RECT 713.400 4766.350 713.680 4768.630 ;
    END
  END gpio_analog_sel[32]
  PIN gpio_analog_sel[33]
    DIRECTION OUTPUT ;
    USE SIGNAL ;
    PORT
      LAYER met2 ;
        RECT 456.400 4766.350 456.680 4768.630 ;
    END
  END gpio_analog_sel[33]
  PIN gpio_analog_sel[34]
    DIRECTION OUTPUT ;
    USE SIGNAL ;
    PORT
      LAYER met2 ;
        RECT 199.400 4766.350 199.680 4768.630 ;
    END
  END gpio_analog_sel[34]
  PIN gpio_analog_sel[35]
    DIRECTION OUTPUT ;
    USE SIGNAL ;
    PORT
      LAYER met3 ;
        RECT -2.000 4589.360 0.300 4589.710 ;
    END
  END gpio_analog_sel[35]
  PIN gpio_analog_sel[36]
    DIRECTION OUTPUT ;
    USE SIGNAL ;
    PORT
      LAYER met3 ;
        RECT -2.000 3740.360 0.300 3740.710 ;
    END
  END gpio_analog_sel[36]
  PIN gpio_analog_sel[37]
    DIRECTION OUTPUT ;
    USE SIGNAL ;
    PORT
      LAYER met3 ;
        RECT -2.000 3524.360 0.300 3524.710 ;
    END
  END gpio_analog_sel[37]
  PIN gpio_analog_sel[38]
    DIRECTION OUTPUT ;
    USE SIGNAL ;
    PORT
      LAYER met3 ;
        RECT -2.000 3308.360 0.300 3308.710 ;
    END
  END gpio_analog_sel[38]
  PIN gpio_analog_sel[39]
    DIRECTION OUTPUT ;
    USE SIGNAL ;
    PORT
      LAYER met3 ;
        RECT -2.000 3092.360 0.300 3092.710 ;
    END
  END gpio_analog_sel[39]
  PIN gpio_analog_sel[3]
    DIRECTION OUTPUT ;
    USE SIGNAL ;
    PORT
      LAYER met3 ;
        RECT 6754.330 1016.920 6756.630 1017.270 ;
    END
  END gpio_analog_sel[3]
  PIN gpio_analog_sel[40]
    DIRECTION OUTPUT ;
    USE SIGNAL ;
    PORT
      LAYER met3 ;
        RECT -2.000 2876.360 0.300 2876.710 ;
    END
  END gpio_analog_sel[40]
  PIN gpio_analog_sel[41]
    DIRECTION OUTPUT ;
    USE SIGNAL ;
    PORT
      LAYER met3 ;
        RECT -2.000 2660.360 0.300 2660.710 ;
    END
  END gpio_analog_sel[41]
  PIN gpio_analog_sel[42]
    DIRECTION OUTPUT ;
    USE SIGNAL ;
    PORT
      LAYER met3 ;
        RECT -2.000 2444.360 0.300 2444.710 ;
    END
  END gpio_analog_sel[42]
  PIN gpio_analog_sel[43]
    DIRECTION OUTPUT ;
    USE SIGNAL ;
    PORT
      LAYER met3 ;
        RECT -2.000 1806.360 0.300 1806.710 ;
    END
  END gpio_analog_sel[43]
  PIN gpio_analog_sel[44]
    DIRECTION OUTPUT ;
    USE SIGNAL ;
    PORT
      LAYER met3 ;
        RECT -2.000 1590.360 0.300 1590.710 ;
    END
  END gpio_analog_sel[44]
  PIN gpio_analog_sel[45]
    DIRECTION OUTPUT ;
    USE SIGNAL ;
    PORT
      LAYER met3 ;
        RECT -2.000 1374.360 0.300 1374.710 ;
    END
  END gpio_analog_sel[45]
  PIN gpio_analog_sel[46]
    DIRECTION OUTPUT ;
    USE SIGNAL ;
    PORT
      LAYER met3 ;
        RECT -2.000 1158.360 0.300 1158.710 ;
    END
  END gpio_analog_sel[46]
  PIN gpio_analog_sel[47]
    DIRECTION OUTPUT ;
    USE SIGNAL ;
    PORT
      LAYER met3 ;
        RECT -2.000 942.360 0.300 942.710 ;
    END
  END gpio_analog_sel[47]
  PIN gpio_analog_sel[48]
    DIRECTION OUTPUT ;
    USE SIGNAL ;
    PORT
      LAYER met3 ;
        RECT -2.000 726.360 0.300 726.710 ;
    END
  END gpio_analog_sel[48]
  PIN gpio_analog_sel[49]
    DIRECTION OUTPUT ;
    USE SIGNAL ;
    PORT
      LAYER met2 ;
        RECT 771.950 -2.000 772.230 0.280 ;
    END
  END gpio_analog_sel[49]
  PIN gpio_analog_sel[4]
    DIRECTION OUTPUT ;
    USE SIGNAL ;
    PORT
      LAYER met3 ;
        RECT 6754.330 1241.920 6756.630 1242.270 ;
    END
  END gpio_analog_sel[4]
  PIN gpio_analog_sel[50]
    DIRECTION OUTPUT ;
    USE SIGNAL ;
    PORT
      LAYER met2 ;
        RECT 1314.950 -2.000 1315.230 0.280 ;
    END
  END gpio_analog_sel[50]
  PIN gpio_analog_sel[51]
    DIRECTION OUTPUT ;
    USE SIGNAL ;
    PORT
      LAYER met2 ;
        RECT 1588.950 -2.000 1589.230 0.280 ;
    END
  END gpio_analog_sel[51]
  PIN gpio_analog_sel[52]
    DIRECTION OUTPUT ;
    USE SIGNAL ;
    PORT
      LAYER met2 ;
        RECT 1862.950 -2.000 1863.230 0.280 ;
    END
  END gpio_analog_sel[52]
  PIN gpio_analog_sel[53]
    DIRECTION OUTPUT ;
    USE SIGNAL ;
    PORT
      LAYER met2 ;
        RECT 2136.950 -2.000 2137.230 0.280 ;
    END
  END gpio_analog_sel[53]
  PIN gpio_analog_sel[54]
    DIRECTION OUTPUT ;
    USE SIGNAL ;
    PORT
      LAYER met2 ;
        RECT 2410.950 -2.000 2411.230 0.280 ;
    END
  END gpio_analog_sel[54]
  PIN gpio_analog_sel[55]
    DIRECTION OUTPUT ;
    USE SIGNAL ;
    PORT
      LAYER met2 ;
        RECT 3225.430 -2.000 3225.710 0.280 ;
    END
  END gpio_analog_sel[55]
  PIN gpio_analog_sel[56]
    DIRECTION OUTPUT ;
    USE SIGNAL ;
    PORT
      LAYER met2 ;
        RECT 3499.430 -2.000 3499.710 0.280 ;
    END
  END gpio_analog_sel[56]
  PIN gpio_analog_sel[57]
    DIRECTION OUTPUT ;
    USE SIGNAL ;
    PORT
      LAYER met2 ;
        RECT 4359.950 -2.000 4360.230 0.280 ;
    END
  END gpio_analog_sel[57]
  PIN gpio_analog_sel[58]
    DIRECTION OUTPUT ;
    USE SIGNAL ;
    PORT
      LAYER met2 ;
        RECT 4902.950 -2.000 4903.230 0.280 ;
    END
  END gpio_analog_sel[58]
  PIN gpio_analog_sel[59]
    DIRECTION OUTPUT ;
    USE SIGNAL ;
    PORT
      LAYER met2 ;
        RECT 5176.950 -2.000 5177.230 0.280 ;
    END
  END gpio_analog_sel[59]
  PIN gpio_analog_sel[5]
    DIRECTION OUTPUT ;
    USE SIGNAL ;
    PORT
      LAYER met3 ;
        RECT 6754.330 1466.920 6756.630 1467.270 ;
    END
  END gpio_analog_sel[5]
  PIN gpio_analog_sel[60]
    DIRECTION OUTPUT ;
    USE SIGNAL ;
    PORT
      LAYER met2 ;
        RECT 5450.950 -2.000 5451.230 0.280 ;
    END
  END gpio_analog_sel[60]
  PIN gpio_analog_sel[61]
    DIRECTION OUTPUT ;
    USE SIGNAL ;
    PORT
      LAYER met2 ;
        RECT 5724.950 -2.000 5725.230 0.280 ;
    END
  END gpio_analog_sel[61]
  PIN gpio_analog_sel[62]
    DIRECTION OUTPUT ;
    USE SIGNAL ;
    PORT
      LAYER met2 ;
        RECT 5998.950 -2.000 5999.230 0.280 ;
    END
  END gpio_analog_sel[62]
  PIN gpio_analog_sel[6]
    DIRECTION OUTPUT ;
    USE SIGNAL ;
    PORT
      LAYER met3 ;
        RECT 6754.330 1692.920 6756.630 1693.270 ;
    END
  END gpio_analog_sel[6]
  PIN gpio_analog_sel[7]
    DIRECTION OUTPUT ;
    USE SIGNAL ;
    PORT
      LAYER met3 ;
        RECT 6754.330 2578.920 6756.630 2579.270 ;
    END
  END gpio_analog_sel[7]
  PIN gpio_analog_sel[8]
    DIRECTION OUTPUT ;
    USE SIGNAL ;
    PORT
      LAYER met3 ;
        RECT 6754.330 2804.920 6756.630 2805.270 ;
    END
  END gpio_analog_sel[8]
  PIN gpio_analog_sel[9]
    DIRECTION OUTPUT ;
    USE SIGNAL ;
    PORT
      LAYER met3 ;
        RECT 6754.330 3029.920 6756.630 3030.270 ;
    END
  END gpio_analog_sel[9]
  PIN gpio_dm0[0]
    DIRECTION OUTPUT ;
    USE SIGNAL ;
    PORT
      LAYER met3 ;
        RECT 6754.330 321.520 6756.630 321.870 ;
    END
  END gpio_dm0[0]
  PIN gpio_dm0[10]
    DIRECTION OUTPUT ;
    USE SIGNAL ;
    PORT
      LAYER met3 ;
        RECT 6754.330 3237.520 6756.630 3237.870 ;
    END
  END gpio_dm0[10]
  PIN gpio_dm0[11]
    DIRECTION OUTPUT ;
    USE SIGNAL ;
    PORT
      LAYER met3 ;
        RECT 6754.330 3462.520 6756.630 3462.870 ;
    END
  END gpio_dm0[11]
  PIN gpio_dm0[12]
    DIRECTION OUTPUT ;
    USE SIGNAL ;
    PORT
      LAYER met3 ;
        RECT 6754.330 3687.520 6756.630 3687.870 ;
    END
  END gpio_dm0[12]
  PIN gpio_dm0[13]
    DIRECTION OUTPUT ;
    USE SIGNAL ;
    PORT
      LAYER met3 ;
        RECT 6754.330 4133.520 6756.630 4133.870 ;
    END
  END gpio_dm0[13]
  PIN gpio_dm0[14]
    DIRECTION OUTPUT ;
    USE SIGNAL ;
    PORT
      LAYER met3 ;
        RECT 6754.330 4579.520 6756.630 4579.870 ;
    END
  END gpio_dm0[14]
  PIN gpio_dm0[15]
    DIRECTION OUTPUT ;
    USE SIGNAL ;
    PORT
      LAYER met2 ;
        RECT 6554.800 4766.350 6555.080 4768.630 ;
    END
  END gpio_dm0[15]
  PIN gpio_dm0[16]
    DIRECTION OUTPUT ;
    USE SIGNAL ;
    PORT
      LAYER met2 ;
        RECT 6045.800 4766.350 6046.080 4768.630 ;
    END
  END gpio_dm0[16]
  PIN gpio_dm0[17]
    DIRECTION OUTPUT ;
    USE SIGNAL ;
    PORT
      LAYER met2 ;
        RECT 5788.800 4766.350 5789.080 4768.630 ;
    END
  END gpio_dm0[17]
  PIN gpio_dm0[18]
    DIRECTION OUTPUT ;
    USE SIGNAL ;
    PORT
      LAYER met2 ;
        RECT 5343.800 4766.350 5344.080 4768.630 ;
    END
  END gpio_dm0[18]
  PIN gpio_dm0[19]
    DIRECTION OUTPUT ;
    USE SIGNAL ;
    PORT
      LAYER met2 ;
        RECT 4834.800 4766.350 4835.080 4768.630 ;
    END
  END gpio_dm0[19]
  PIN gpio_dm0[1]
    DIRECTION OUTPUT ;
    USE SIGNAL ;
    PORT
      LAYER met3 ;
        RECT 6754.330 547.520 6756.630 547.870 ;
    END
  END gpio_dm0[1]
  PIN gpio_dm0[20]
    DIRECTION OUTPUT ;
    USE SIGNAL ;
    PORT
      LAYER met2 ;
        RECT 4576.800 4766.350 4577.080 4768.630 ;
    END
  END gpio_dm0[20]
  PIN gpio_dm0[21]
    DIRECTION OUTPUT ;
    USE SIGNAL ;
    PORT
      LAYER met2 ;
        RECT 4319.800 4766.350 4320.080 4768.630 ;
    END
  END gpio_dm0[21]
  PIN gpio_dm0[22]
    DIRECTION OUTPUT ;
    USE SIGNAL ;
    PORT
      LAYER met2 ;
        RECT 4062.800 4766.350 4063.080 4768.630 ;
    END
  END gpio_dm0[22]
  PIN gpio_dm0[23]
    DIRECTION OUTPUT ;
    USE SIGNAL ;
    PORT
      LAYER met2 ;
        RECT 3805.800 4766.350 3806.080 4768.630 ;
    END
  END gpio_dm0[23]
  PIN gpio_dm0[24]
    DIRECTION OUTPUT ;
    USE SIGNAL ;
    PORT
      LAYER met2 ;
        RECT 3480.800 4766.350 3481.080 4768.630 ;
    END
  END gpio_dm0[24]
  PIN gpio_dm0[25]
    DIRECTION OUTPUT ;
    USE SIGNAL ;
    PORT
      LAYER met2 ;
        RECT 3223.800 4766.350 3224.080 4768.630 ;
    END
  END gpio_dm0[25]
  PIN gpio_dm0[26]
    DIRECTION OUTPUT ;
    USE SIGNAL ;
    PORT
      LAYER met2 ;
        RECT 2966.800 4766.350 2967.080 4768.630 ;
    END
  END gpio_dm0[26]
  PIN gpio_dm0[27]
    DIRECTION OUTPUT ;
    USE SIGNAL ;
    PORT
      LAYER met2 ;
        RECT 2457.800 4766.350 2458.080 4768.630 ;
    END
  END gpio_dm0[27]
  PIN gpio_dm0[28]
    DIRECTION OUTPUT ;
    USE SIGNAL ;
    PORT
      LAYER met2 ;
        RECT 2200.800 4766.350 2201.080 4768.630 ;
    END
  END gpio_dm0[28]
  PIN gpio_dm0[29]
    DIRECTION OUTPUT ;
    USE SIGNAL ;
    PORT
      LAYER met2 ;
        RECT 1755.800 4766.350 1756.080 4768.630 ;
    END
  END gpio_dm0[29]
  PIN gpio_dm0[2]
    DIRECTION OUTPUT ;
    USE SIGNAL ;
    PORT
      LAYER met3 ;
        RECT 6754.330 772.520 6756.630 772.870 ;
    END
  END gpio_dm0[2]
  PIN gpio_dm0[30]
    DIRECTION OUTPUT ;
    USE SIGNAL ;
    PORT
      LAYER met2 ;
        RECT 1246.800 4766.350 1247.080 4768.630 ;
    END
  END gpio_dm0[30]
  PIN gpio_dm0[31]
    DIRECTION OUTPUT ;
    USE SIGNAL ;
    PORT
      LAYER met2 ;
        RECT 988.800 4766.350 989.080 4768.630 ;
    END
  END gpio_dm0[31]
  PIN gpio_dm0[32]
    DIRECTION OUTPUT ;
    USE SIGNAL ;
    PORT
      LAYER met2 ;
        RECT 731.800 4766.350 732.080 4768.630 ;
    END
  END gpio_dm0[32]
  PIN gpio_dm0[33]
    DIRECTION OUTPUT ;
    USE SIGNAL ;
    PORT
      LAYER met2 ;
        RECT 474.800 4766.350 475.080 4768.630 ;
    END
  END gpio_dm0[33]
  PIN gpio_dm0[34]
    DIRECTION OUTPUT ;
    USE SIGNAL ;
    PORT
      LAYER met2 ;
        RECT 217.800 4766.350 218.080 4768.630 ;
    END
  END gpio_dm0[34]
  PIN gpio_dm0[35]
    DIRECTION OUTPUT ;
    USE SIGNAL ;
    PORT
      LAYER met3 ;
        RECT -2.000 4607.760 0.300 4608.110 ;
    END
  END gpio_dm0[35]
  PIN gpio_dm0[36]
    DIRECTION OUTPUT ;
    USE SIGNAL ;
    PORT
      LAYER met3 ;
        RECT -2.000 3758.760 0.300 3759.110 ;
    END
  END gpio_dm0[36]
  PIN gpio_dm0[37]
    DIRECTION OUTPUT ;
    USE SIGNAL ;
    PORT
      LAYER met3 ;
        RECT -2.000 3542.760 0.300 3543.110 ;
    END
  END gpio_dm0[37]
  PIN gpio_dm0[38]
    DIRECTION OUTPUT ;
    USE SIGNAL ;
    PORT
      LAYER met3 ;
        RECT -2.000 3326.760 0.300 3327.110 ;
    END
  END gpio_dm0[38]
  PIN gpio_dm0[39]
    DIRECTION OUTPUT ;
    USE SIGNAL ;
    PORT
      LAYER met3 ;
        RECT -2.000 3110.760 0.300 3111.110 ;
    END
  END gpio_dm0[39]
  PIN gpio_dm0[3]
    DIRECTION OUTPUT ;
    USE SIGNAL ;
    PORT
      LAYER met3 ;
        RECT 6754.330 998.520 6756.630 998.870 ;
    END
  END gpio_dm0[3]
  PIN gpio_dm0[40]
    DIRECTION OUTPUT ;
    USE SIGNAL ;
    PORT
      LAYER met3 ;
        RECT -2.000 2894.760 0.300 2895.110 ;
    END
  END gpio_dm0[40]
  PIN gpio_dm0[41]
    DIRECTION OUTPUT ;
    USE SIGNAL ;
    PORT
      LAYER met3 ;
        RECT -2.000 2678.760 0.300 2679.110 ;
    END
  END gpio_dm0[41]
  PIN gpio_dm0[42]
    DIRECTION OUTPUT ;
    USE SIGNAL ;
    PORT
      LAYER met3 ;
        RECT -2.000 2462.760 0.300 2463.110 ;
    END
  END gpio_dm0[42]
  PIN gpio_dm0[43]
    DIRECTION OUTPUT ;
    USE SIGNAL ;
    PORT
      LAYER met3 ;
        RECT -2.000 1824.760 0.300 1825.110 ;
    END
  END gpio_dm0[43]
  PIN gpio_dm0[44]
    DIRECTION OUTPUT ;
    USE SIGNAL ;
    PORT
      LAYER met3 ;
        RECT -2.000 1608.760 0.300 1609.110 ;
    END
  END gpio_dm0[44]
  PIN gpio_dm0[45]
    DIRECTION OUTPUT ;
    USE SIGNAL ;
    PORT
      LAYER met3 ;
        RECT -2.000 1392.760 0.300 1393.110 ;
    END
  END gpio_dm0[45]
  PIN gpio_dm0[46]
    DIRECTION OUTPUT ;
    USE SIGNAL ;
    PORT
      LAYER met3 ;
        RECT -2.000 1176.760 0.300 1177.110 ;
    END
  END gpio_dm0[46]
  PIN gpio_dm0[47]
    DIRECTION OUTPUT ;
    USE SIGNAL ;
    PORT
      LAYER met3 ;
        RECT -2.000 960.760 0.300 961.110 ;
    END
  END gpio_dm0[47]
  PIN gpio_dm0[48]
    DIRECTION OUTPUT ;
    USE SIGNAL ;
    PORT
      LAYER met3 ;
        RECT -2.000 744.760 0.300 745.110 ;
    END
  END gpio_dm0[48]
  PIN gpio_dm0[49]
    DIRECTION OUTPUT ;
    USE SIGNAL ;
    PORT
      LAYER met2 ;
        RECT 753.550 -2.000 753.830 0.280 ;
    END
  END gpio_dm0[49]
  PIN gpio_dm0[4]
    DIRECTION OUTPUT ;
    USE SIGNAL ;
    PORT
      LAYER met3 ;
        RECT 6754.330 1223.520 6756.630 1223.870 ;
    END
  END gpio_dm0[4]
  PIN gpio_dm0[50]
    DIRECTION OUTPUT ;
    USE SIGNAL ;
    PORT
      LAYER met2 ;
        RECT 1296.550 -2.000 1296.830 0.280 ;
    END
  END gpio_dm0[50]
  PIN gpio_dm0[51]
    DIRECTION OUTPUT ;
    USE SIGNAL ;
    PORT
      LAYER met2 ;
        RECT 1570.550 -2.000 1570.830 0.280 ;
    END
  END gpio_dm0[51]
  PIN gpio_dm0[52]
    DIRECTION OUTPUT ;
    USE SIGNAL ;
    PORT
      LAYER met2 ;
        RECT 1844.550 -2.000 1844.830 0.280 ;
    END
  END gpio_dm0[52]
  PIN gpio_dm0[53]
    DIRECTION OUTPUT ;
    USE SIGNAL ;
    PORT
      LAYER met2 ;
        RECT 2118.550 -2.000 2118.830 0.280 ;
    END
  END gpio_dm0[53]
  PIN gpio_dm0[54]
    DIRECTION OUTPUT ;
    USE SIGNAL ;
    PORT
      LAYER met2 ;
        RECT 2392.550 -2.000 2392.830 0.280 ;
    END
  END gpio_dm0[54]
  PIN gpio_dm0[55]
    DIRECTION OUTPUT ;
    USE SIGNAL ;
    PORT
      LAYER met2 ;
        RECT 3207.030 -2.000 3207.310 0.280 ;
    END
  END gpio_dm0[55]
  PIN gpio_dm0[56]
    DIRECTION OUTPUT ;
    USE SIGNAL ;
    PORT
      LAYER met2 ;
        RECT 3481.030 -2.000 3481.310 0.280 ;
    END
  END gpio_dm0[56]
  PIN gpio_dm0[57]
    DIRECTION OUTPUT ;
    USE SIGNAL ;
    PORT
      LAYER met2 ;
        RECT 4341.550 -2.000 4341.830 0.280 ;
    END
  END gpio_dm0[57]
  PIN gpio_dm0[58]
    DIRECTION OUTPUT ;
    USE SIGNAL ;
    PORT
      LAYER met2 ;
        RECT 4884.550 -2.000 4884.830 0.280 ;
    END
  END gpio_dm0[58]
  PIN gpio_dm0[59]
    DIRECTION OUTPUT ;
    USE SIGNAL ;
    PORT
      LAYER met2 ;
        RECT 5158.550 -2.000 5158.830 0.280 ;
    END
  END gpio_dm0[59]
  PIN gpio_dm0[5]
    DIRECTION OUTPUT ;
    USE SIGNAL ;
    PORT
      LAYER met3 ;
        RECT 6754.330 1448.520 6756.630 1448.870 ;
    END
  END gpio_dm0[5]
  PIN gpio_dm0[60]
    DIRECTION OUTPUT ;
    USE SIGNAL ;
    PORT
      LAYER met2 ;
        RECT 5432.550 -2.000 5432.830 0.280 ;
    END
  END gpio_dm0[60]
  PIN gpio_dm0[61]
    DIRECTION OUTPUT ;
    USE SIGNAL ;
    PORT
      LAYER met2 ;
        RECT 5706.550 -2.000 5706.830 0.280 ;
    END
  END gpio_dm0[61]
  PIN gpio_dm0[62]
    DIRECTION OUTPUT ;
    USE SIGNAL ;
    PORT
      LAYER met2 ;
        RECT 5980.550 -2.000 5980.830 0.280 ;
    END
  END gpio_dm0[62]
  PIN gpio_dm0[6]
    DIRECTION OUTPUT ;
    USE SIGNAL ;
    PORT
      LAYER met3 ;
        RECT 6754.330 1674.520 6756.630 1674.870 ;
    END
  END gpio_dm0[6]
  PIN gpio_dm0[7]
    DIRECTION OUTPUT ;
    USE SIGNAL ;
    PORT
      LAYER met3 ;
        RECT 6754.330 2560.520 6756.630 2560.870 ;
    END
  END gpio_dm0[7]
  PIN gpio_dm0[8]
    DIRECTION OUTPUT ;
    USE SIGNAL ;
    PORT
      LAYER met3 ;
        RECT 6754.330 2786.520 6756.630 2786.870 ;
    END
  END gpio_dm0[8]
  PIN gpio_dm0[9]
    DIRECTION OUTPUT ;
    USE SIGNAL ;
    PORT
      LAYER met3 ;
        RECT 6754.330 3011.520 6756.630 3011.870 ;
    END
  END gpio_dm0[9]
  PIN gpio_dm1[0]
    DIRECTION OUTPUT ;
    USE SIGNAL ;
    PORT
      LAYER met3 ;
        RECT 6754.330 312.320 6756.630 312.670 ;
    END
  END gpio_dm1[0]
  PIN gpio_dm1[10]
    DIRECTION OUTPUT ;
    USE SIGNAL ;
    PORT
      LAYER met3 ;
        RECT 6754.330 3228.320 6756.630 3228.670 ;
    END
  END gpio_dm1[10]
  PIN gpio_dm1[11]
    DIRECTION OUTPUT ;
    USE SIGNAL ;
    PORT
      LAYER met3 ;
        RECT 6754.330 3453.320 6756.630 3453.670 ;
    END
  END gpio_dm1[11]
  PIN gpio_dm1[12]
    DIRECTION OUTPUT ;
    USE SIGNAL ;
    PORT
      LAYER met3 ;
        RECT 6754.330 3678.320 6756.630 3678.670 ;
    END
  END gpio_dm1[12]
  PIN gpio_dm1[13]
    DIRECTION OUTPUT ;
    USE SIGNAL ;
    PORT
      LAYER met3 ;
        RECT 6754.330 4124.320 6756.630 4124.670 ;
    END
  END gpio_dm1[13]
  PIN gpio_dm1[14]
    DIRECTION OUTPUT ;
    USE SIGNAL ;
    PORT
      LAYER met3 ;
        RECT 6754.330 4570.320 6756.630 4570.670 ;
    END
  END gpio_dm1[14]
  PIN gpio_dm1[15]
    DIRECTION OUTPUT ;
    USE SIGNAL ;
    PORT
      LAYER met2 ;
        RECT 6564.000 4766.350 6564.280 4768.630 ;
    END
  END gpio_dm1[15]
  PIN gpio_dm1[16]
    DIRECTION OUTPUT ;
    USE SIGNAL ;
    PORT
      LAYER met2 ;
        RECT 6055.000 4766.350 6055.280 4768.630 ;
    END
  END gpio_dm1[16]
  PIN gpio_dm1[17]
    DIRECTION OUTPUT ;
    USE SIGNAL ;
    PORT
      LAYER met2 ;
        RECT 5798.000 4766.350 5798.280 4768.630 ;
    END
  END gpio_dm1[17]
  PIN gpio_dm1[18]
    DIRECTION OUTPUT ;
    USE SIGNAL ;
    PORT
      LAYER met2 ;
        RECT 5353.000 4766.350 5353.280 4768.630 ;
    END
  END gpio_dm1[18]
  PIN gpio_dm1[19]
    DIRECTION OUTPUT ;
    USE SIGNAL ;
    PORT
      LAYER met2 ;
        RECT 4844.000 4766.350 4844.280 4768.630 ;
    END
  END gpio_dm1[19]
  PIN gpio_dm1[1]
    DIRECTION OUTPUT ;
    USE SIGNAL ;
    PORT
      LAYER met3 ;
        RECT 6754.330 538.320 6756.630 538.670 ;
    END
  END gpio_dm1[1]
  PIN gpio_dm1[20]
    DIRECTION OUTPUT ;
    USE SIGNAL ;
    PORT
      LAYER met2 ;
        RECT 4586.000 4766.350 4586.280 4768.630 ;
    END
  END gpio_dm1[20]
  PIN gpio_dm1[21]
    DIRECTION OUTPUT ;
    USE SIGNAL ;
    PORT
      LAYER met2 ;
        RECT 4329.000 4766.350 4329.280 4768.630 ;
    END
  END gpio_dm1[21]
  PIN gpio_dm1[22]
    DIRECTION OUTPUT ;
    USE SIGNAL ;
    PORT
      LAYER met2 ;
        RECT 4072.000 4766.350 4072.280 4768.630 ;
    END
  END gpio_dm1[22]
  PIN gpio_dm1[23]
    DIRECTION OUTPUT ;
    USE SIGNAL ;
    PORT
      LAYER met2 ;
        RECT 3815.000 4766.350 3815.280 4768.630 ;
    END
  END gpio_dm1[23]
  PIN gpio_dm1[24]
    DIRECTION OUTPUT ;
    USE SIGNAL ;
    PORT
      LAYER met2 ;
        RECT 3490.000 4766.350 3490.280 4768.630 ;
    END
  END gpio_dm1[24]
  PIN gpio_dm1[25]
    DIRECTION OUTPUT ;
    USE SIGNAL ;
    PORT
      LAYER met2 ;
        RECT 3233.000 4766.350 3233.280 4768.630 ;
    END
  END gpio_dm1[25]
  PIN gpio_dm1[26]
    DIRECTION OUTPUT ;
    USE SIGNAL ;
    PORT
      LAYER met2 ;
        RECT 2976.000 4766.350 2976.280 4768.630 ;
    END
  END gpio_dm1[26]
  PIN gpio_dm1[27]
    DIRECTION OUTPUT ;
    USE SIGNAL ;
    PORT
      LAYER met2 ;
        RECT 2467.000 4766.350 2467.280 4768.630 ;
    END
  END gpio_dm1[27]
  PIN gpio_dm1[28]
    DIRECTION OUTPUT ;
    USE SIGNAL ;
    PORT
      LAYER met2 ;
        RECT 2210.000 4766.350 2210.280 4768.630 ;
    END
  END gpio_dm1[28]
  PIN gpio_dm1[29]
    DIRECTION OUTPUT ;
    USE SIGNAL ;
    PORT
      LAYER met2 ;
        RECT 1765.000 4766.350 1765.280 4768.630 ;
    END
  END gpio_dm1[29]
  PIN gpio_dm1[2]
    DIRECTION OUTPUT ;
    USE SIGNAL ;
    PORT
      LAYER met3 ;
        RECT 6754.330 763.320 6756.630 763.670 ;
    END
  END gpio_dm1[2]
  PIN gpio_dm1[30]
    DIRECTION OUTPUT ;
    USE SIGNAL ;
    PORT
      LAYER met2 ;
        RECT 1256.000 4766.350 1256.280 4768.630 ;
    END
  END gpio_dm1[30]
  PIN gpio_dm1[31]
    DIRECTION OUTPUT ;
    USE SIGNAL ;
    PORT
      LAYER met2 ;
        RECT 998.000 4766.350 998.280 4768.630 ;
    END
  END gpio_dm1[31]
  PIN gpio_dm1[32]
    DIRECTION OUTPUT ;
    USE SIGNAL ;
    PORT
      LAYER met2 ;
        RECT 741.000 4766.350 741.280 4768.630 ;
    END
  END gpio_dm1[32]
  PIN gpio_dm1[33]
    DIRECTION OUTPUT ;
    USE SIGNAL ;
    PORT
      LAYER met2 ;
        RECT 484.000 4766.350 484.280 4768.630 ;
    END
  END gpio_dm1[33]
  PIN gpio_dm1[34]
    DIRECTION OUTPUT ;
    USE SIGNAL ;
    PORT
      LAYER met2 ;
        RECT 227.000 4766.350 227.280 4768.630 ;
    END
  END gpio_dm1[34]
  PIN gpio_dm1[35]
    DIRECTION OUTPUT ;
    USE SIGNAL ;
    PORT
      LAYER met3 ;
        RECT -2.000 4616.960 0.300 4617.310 ;
    END
  END gpio_dm1[35]
  PIN gpio_dm1[36]
    DIRECTION OUTPUT ;
    USE SIGNAL ;
    PORT
      LAYER met3 ;
        RECT -2.000 3767.960 0.300 3768.310 ;
    END
  END gpio_dm1[36]
  PIN gpio_dm1[37]
    DIRECTION OUTPUT ;
    USE SIGNAL ;
    PORT
      LAYER met3 ;
        RECT -2.000 3551.960 0.300 3552.310 ;
    END
  END gpio_dm1[37]
  PIN gpio_dm1[38]
    DIRECTION OUTPUT ;
    USE SIGNAL ;
    PORT
      LAYER met3 ;
        RECT -2.000 3335.960 0.300 3336.310 ;
    END
  END gpio_dm1[38]
  PIN gpio_dm1[39]
    DIRECTION OUTPUT ;
    USE SIGNAL ;
    PORT
      LAYER met3 ;
        RECT -2.000 3119.960 0.300 3120.310 ;
    END
  END gpio_dm1[39]
  PIN gpio_dm1[3]
    DIRECTION OUTPUT ;
    USE SIGNAL ;
    PORT
      LAYER met3 ;
        RECT 6754.330 989.320 6756.630 989.670 ;
    END
  END gpio_dm1[3]
  PIN gpio_dm1[40]
    DIRECTION OUTPUT ;
    USE SIGNAL ;
    PORT
      LAYER met3 ;
        RECT -2.000 2903.960 0.300 2904.310 ;
    END
  END gpio_dm1[40]
  PIN gpio_dm1[41]
    DIRECTION OUTPUT ;
    USE SIGNAL ;
    PORT
      LAYER met3 ;
        RECT -2.000 2687.960 0.300 2688.310 ;
    END
  END gpio_dm1[41]
  PIN gpio_dm1[42]
    DIRECTION OUTPUT ;
    USE SIGNAL ;
    PORT
      LAYER met3 ;
        RECT -2.000 2471.960 0.300 2472.310 ;
    END
  END gpio_dm1[42]
  PIN gpio_dm1[43]
    DIRECTION OUTPUT ;
    USE SIGNAL ;
    PORT
      LAYER met3 ;
        RECT -2.000 1833.960 0.300 1834.310 ;
    END
  END gpio_dm1[43]
  PIN gpio_dm1[44]
    DIRECTION OUTPUT ;
    USE SIGNAL ;
    PORT
      LAYER met3 ;
        RECT -2.000 1617.960 0.300 1618.310 ;
    END
  END gpio_dm1[44]
  PIN gpio_dm1[45]
    DIRECTION OUTPUT ;
    USE SIGNAL ;
    PORT
      LAYER met3 ;
        RECT -2.000 1401.960 0.300 1402.310 ;
    END
  END gpio_dm1[45]
  PIN gpio_dm1[46]
    DIRECTION OUTPUT ;
    USE SIGNAL ;
    PORT
      LAYER met3 ;
        RECT -2.000 1185.960 0.300 1186.310 ;
    END
  END gpio_dm1[46]
  PIN gpio_dm1[47]
    DIRECTION OUTPUT ;
    USE SIGNAL ;
    PORT
      LAYER met3 ;
        RECT -2.000 969.960 0.300 970.310 ;
    END
  END gpio_dm1[47]
  PIN gpio_dm1[48]
    DIRECTION OUTPUT ;
    USE SIGNAL ;
    PORT
      LAYER met3 ;
        RECT -2.000 753.960 0.300 754.310 ;
    END
  END gpio_dm1[48]
  PIN gpio_dm1[49]
    DIRECTION OUTPUT ;
    USE SIGNAL ;
    PORT
      LAYER met2 ;
        RECT 744.350 -2.000 744.630 0.280 ;
    END
  END gpio_dm1[49]
  PIN gpio_dm1[4]
    DIRECTION OUTPUT ;
    USE SIGNAL ;
    PORT
      LAYER met3 ;
        RECT 6754.330 1214.320 6756.630 1214.670 ;
    END
  END gpio_dm1[4]
  PIN gpio_dm1[50]
    DIRECTION OUTPUT ;
    USE SIGNAL ;
    PORT
      LAYER met2 ;
        RECT 1287.350 -2.000 1287.630 0.280 ;
    END
  END gpio_dm1[50]
  PIN gpio_dm1[51]
    DIRECTION OUTPUT ;
    USE SIGNAL ;
    PORT
      LAYER met2 ;
        RECT 1561.350 -2.000 1561.630 0.280 ;
    END
  END gpio_dm1[51]
  PIN gpio_dm1[52]
    DIRECTION OUTPUT ;
    USE SIGNAL ;
    PORT
      LAYER met2 ;
        RECT 1835.350 -2.000 1835.630 0.280 ;
    END
  END gpio_dm1[52]
  PIN gpio_dm1[53]
    DIRECTION OUTPUT ;
    USE SIGNAL ;
    PORT
      LAYER met2 ;
        RECT 2109.350 -2.000 2109.630 0.280 ;
    END
  END gpio_dm1[53]
  PIN gpio_dm1[54]
    DIRECTION OUTPUT ;
    USE SIGNAL ;
    PORT
      LAYER met2 ;
        RECT 2383.350 -2.000 2383.630 0.280 ;
    END
  END gpio_dm1[54]
  PIN gpio_dm1[55]
    DIRECTION OUTPUT ;
    USE SIGNAL ;
    PORT
      LAYER met2 ;
        RECT 3197.830 -2.000 3198.110 0.280 ;
    END
  END gpio_dm1[55]
  PIN gpio_dm1[56]
    DIRECTION OUTPUT ;
    USE SIGNAL ;
    PORT
      LAYER met2 ;
        RECT 3471.830 -2.000 3472.110 0.280 ;
    END
  END gpio_dm1[56]
  PIN gpio_dm1[57]
    DIRECTION OUTPUT ;
    USE SIGNAL ;
    PORT
      LAYER met2 ;
        RECT 4332.350 -2.000 4332.630 0.280 ;
    END
  END gpio_dm1[57]
  PIN gpio_dm1[58]
    DIRECTION OUTPUT ;
    USE SIGNAL ;
    PORT
      LAYER met2 ;
        RECT 4875.350 -2.000 4875.630 0.280 ;
    END
  END gpio_dm1[58]
  PIN gpio_dm1[59]
    DIRECTION OUTPUT ;
    USE SIGNAL ;
    PORT
      LAYER met2 ;
        RECT 5149.350 -2.000 5149.630 0.280 ;
    END
  END gpio_dm1[59]
  PIN gpio_dm1[5]
    DIRECTION OUTPUT ;
    USE SIGNAL ;
    PORT
      LAYER met3 ;
        RECT 6754.330 1439.320 6756.630 1439.670 ;
    END
  END gpio_dm1[5]
  PIN gpio_dm1[60]
    DIRECTION OUTPUT ;
    USE SIGNAL ;
    PORT
      LAYER met2 ;
        RECT 5423.350 -2.000 5423.630 0.280 ;
    END
  END gpio_dm1[60]
  PIN gpio_dm1[61]
    DIRECTION OUTPUT ;
    USE SIGNAL ;
    PORT
      LAYER met2 ;
        RECT 5697.350 -2.000 5697.630 0.280 ;
    END
  END gpio_dm1[61]
  PIN gpio_dm1[62]
    DIRECTION OUTPUT ;
    USE SIGNAL ;
    PORT
      LAYER met2 ;
        RECT 5971.350 -2.000 5971.630 0.280 ;
    END
  END gpio_dm1[62]
  PIN gpio_dm1[6]
    DIRECTION OUTPUT ;
    USE SIGNAL ;
    PORT
      LAYER met3 ;
        RECT 6754.330 1665.320 6756.630 1665.670 ;
    END
  END gpio_dm1[6]
  PIN gpio_dm1[7]
    DIRECTION OUTPUT ;
    USE SIGNAL ;
    PORT
      LAYER met3 ;
        RECT 6754.330 2551.320 6756.630 2551.670 ;
    END
  END gpio_dm1[7]
  PIN gpio_dm1[8]
    DIRECTION OUTPUT ;
    USE SIGNAL ;
    PORT
      LAYER met3 ;
        RECT 6754.330 2777.320 6756.630 2777.670 ;
    END
  END gpio_dm1[8]
  PIN gpio_dm1[9]
    DIRECTION OUTPUT ;
    USE SIGNAL ;
    PORT
      LAYER met3 ;
        RECT 6754.330 3002.320 6756.630 3002.670 ;
    END
  END gpio_dm1[9]
  PIN gpio_dm2[0]
    DIRECTION OUTPUT ;
    USE SIGNAL ;
    PORT
      LAYER met3 ;
        RECT 6754.330 343.140 6756.630 343.490 ;
    END
  END gpio_dm2[0]
  PIN gpio_dm2[10]
    DIRECTION OUTPUT ;
    USE SIGNAL ;
    PORT
      LAYER met3 ;
        RECT 6754.330 3259.140 6756.630 3259.490 ;
    END
  END gpio_dm2[10]
  PIN gpio_dm2[11]
    DIRECTION OUTPUT ;
    USE SIGNAL ;
    PORT
      LAYER met3 ;
        RECT 6754.330 3484.140 6756.630 3484.490 ;
    END
  END gpio_dm2[11]
  PIN gpio_dm2[12]
    DIRECTION OUTPUT ;
    USE SIGNAL ;
    PORT
      LAYER met3 ;
        RECT 6754.330 3709.140 6756.630 3709.490 ;
    END
  END gpio_dm2[12]
  PIN gpio_dm2[13]
    DIRECTION OUTPUT ;
    USE SIGNAL ;
    PORT
      LAYER met3 ;
        RECT 6754.330 4155.140 6756.630 4155.490 ;
    END
  END gpio_dm2[13]
  PIN gpio_dm2[14]
    DIRECTION OUTPUT ;
    USE SIGNAL ;
    PORT
      LAYER met3 ;
        RECT 6754.330 4601.140 6756.630 4601.490 ;
    END
  END gpio_dm2[14]
  PIN gpio_dm2[15]
    DIRECTION OUTPUT ;
    USE SIGNAL ;
    PORT
      LAYER met2 ;
        RECT 6533.180 4766.350 6533.460 4768.630 ;
    END
  END gpio_dm2[15]
  PIN gpio_dm2[16]
    DIRECTION OUTPUT ;
    USE SIGNAL ;
    PORT
      LAYER met2 ;
        RECT 6024.180 4766.350 6024.460 4768.630 ;
    END
  END gpio_dm2[16]
  PIN gpio_dm2[17]
    DIRECTION OUTPUT ;
    USE SIGNAL ;
    PORT
      LAYER met2 ;
        RECT 5767.180 4766.350 5767.460 4768.630 ;
    END
  END gpio_dm2[17]
  PIN gpio_dm2[18]
    DIRECTION OUTPUT ;
    USE SIGNAL ;
    PORT
      LAYER met2 ;
        RECT 5322.180 4766.350 5322.460 4768.630 ;
    END
  END gpio_dm2[18]
  PIN gpio_dm2[19]
    DIRECTION OUTPUT ;
    USE SIGNAL ;
    PORT
      LAYER met2 ;
        RECT 4813.180 4766.350 4813.460 4768.630 ;
    END
  END gpio_dm2[19]
  PIN gpio_dm2[1]
    DIRECTION OUTPUT ;
    USE SIGNAL ;
    PORT
      LAYER met3 ;
        RECT 6754.330 569.140 6756.630 569.490 ;
    END
  END gpio_dm2[1]
  PIN gpio_dm2[20]
    DIRECTION OUTPUT ;
    USE SIGNAL ;
    PORT
      LAYER met2 ;
        RECT 4555.180 4766.350 4555.460 4768.630 ;
    END
  END gpio_dm2[20]
  PIN gpio_dm2[21]
    DIRECTION OUTPUT ;
    USE SIGNAL ;
    PORT
      LAYER met2 ;
        RECT 4298.180 4766.350 4298.460 4768.630 ;
    END
  END gpio_dm2[21]
  PIN gpio_dm2[22]
    DIRECTION OUTPUT ;
    USE SIGNAL ;
    PORT
      LAYER met2 ;
        RECT 4041.180 4766.350 4041.460 4768.630 ;
    END
  END gpio_dm2[22]
  PIN gpio_dm2[23]
    DIRECTION OUTPUT ;
    USE SIGNAL ;
    PORT
      LAYER met2 ;
        RECT 3784.180 4766.350 3784.460 4768.630 ;
    END
  END gpio_dm2[23]
  PIN gpio_dm2[24]
    DIRECTION OUTPUT ;
    USE SIGNAL ;
    PORT
      LAYER met2 ;
        RECT 3459.180 4766.350 3459.460 4768.630 ;
    END
  END gpio_dm2[24]
  PIN gpio_dm2[25]
    DIRECTION OUTPUT ;
    USE SIGNAL ;
    PORT
      LAYER met2 ;
        RECT 3202.180 4766.350 3202.460 4768.630 ;
    END
  END gpio_dm2[25]
  PIN gpio_dm2[26]
    DIRECTION OUTPUT ;
    USE SIGNAL ;
    PORT
      LAYER met2 ;
        RECT 2945.180 4766.350 2945.460 4768.630 ;
    END
  END gpio_dm2[26]
  PIN gpio_dm2[27]
    DIRECTION OUTPUT ;
    USE SIGNAL ;
    PORT
      LAYER met2 ;
        RECT 2436.180 4766.350 2436.460 4768.630 ;
    END
  END gpio_dm2[27]
  PIN gpio_dm2[28]
    DIRECTION OUTPUT ;
    USE SIGNAL ;
    PORT
      LAYER met2 ;
        RECT 2179.180 4766.350 2179.460 4768.630 ;
    END
  END gpio_dm2[28]
  PIN gpio_dm2[29]
    DIRECTION OUTPUT ;
    USE SIGNAL ;
    PORT
      LAYER met2 ;
        RECT 1734.180 4766.350 1734.460 4768.630 ;
    END
  END gpio_dm2[29]
  PIN gpio_dm2[2]
    DIRECTION OUTPUT ;
    USE SIGNAL ;
    PORT
      LAYER met3 ;
        RECT 6754.330 794.140 6756.630 794.490 ;
    END
  END gpio_dm2[2]
  PIN gpio_dm2[30]
    DIRECTION OUTPUT ;
    USE SIGNAL ;
    PORT
      LAYER met2 ;
        RECT 1225.180 4766.350 1225.460 4768.630 ;
    END
  END gpio_dm2[30]
  PIN gpio_dm2[31]
    DIRECTION OUTPUT ;
    USE SIGNAL ;
    PORT
      LAYER met2 ;
        RECT 967.180 4766.350 967.460 4768.630 ;
    END
  END gpio_dm2[31]
  PIN gpio_dm2[32]
    DIRECTION OUTPUT ;
    USE SIGNAL ;
    PORT
      LAYER met2 ;
        RECT 710.180 4766.350 710.460 4768.630 ;
    END
  END gpio_dm2[32]
  PIN gpio_dm2[33]
    DIRECTION OUTPUT ;
    USE SIGNAL ;
    PORT
      LAYER met2 ;
        RECT 453.180 4766.350 453.460 4768.630 ;
    END
  END gpio_dm2[33]
  PIN gpio_dm2[34]
    DIRECTION OUTPUT ;
    USE SIGNAL ;
    PORT
      LAYER met2 ;
        RECT 196.180 4766.350 196.460 4768.630 ;
    END
  END gpio_dm2[34]
  PIN gpio_dm2[35]
    DIRECTION OUTPUT ;
    USE SIGNAL ;
    PORT
      LAYER met3 ;
        RECT -2.000 4586.140 0.300 4586.490 ;
    END
  END gpio_dm2[35]
  PIN gpio_dm2[36]
    DIRECTION OUTPUT ;
    USE SIGNAL ;
    PORT
      LAYER met3 ;
        RECT -2.000 3737.140 0.300 3737.490 ;
    END
  END gpio_dm2[36]
  PIN gpio_dm2[37]
    DIRECTION OUTPUT ;
    USE SIGNAL ;
    PORT
      LAYER met3 ;
        RECT -2.000 3521.140 0.300 3521.490 ;
    END
  END gpio_dm2[37]
  PIN gpio_dm2[38]
    DIRECTION OUTPUT ;
    USE SIGNAL ;
    PORT
      LAYER met3 ;
        RECT -2.000 3305.140 0.300 3305.490 ;
    END
  END gpio_dm2[38]
  PIN gpio_dm2[39]
    DIRECTION OUTPUT ;
    USE SIGNAL ;
    PORT
      LAYER met3 ;
        RECT -2.000 3089.140 0.300 3089.490 ;
    END
  END gpio_dm2[39]
  PIN gpio_dm2[3]
    DIRECTION OUTPUT ;
    USE SIGNAL ;
    PORT
      LAYER met3 ;
        RECT 6754.330 1020.140 6756.630 1020.490 ;
    END
  END gpio_dm2[3]
  PIN gpio_dm2[40]
    DIRECTION OUTPUT ;
    USE SIGNAL ;
    PORT
      LAYER met3 ;
        RECT -2.000 2873.140 0.300 2873.490 ;
    END
  END gpio_dm2[40]
  PIN gpio_dm2[41]
    DIRECTION OUTPUT ;
    USE SIGNAL ;
    PORT
      LAYER met3 ;
        RECT -2.000 2657.140 0.300 2657.490 ;
    END
  END gpio_dm2[41]
  PIN gpio_dm2[42]
    DIRECTION OUTPUT ;
    USE SIGNAL ;
    PORT
      LAYER met3 ;
        RECT -2.000 2441.140 0.300 2441.490 ;
    END
  END gpio_dm2[42]
  PIN gpio_dm2[43]
    DIRECTION OUTPUT ;
    USE SIGNAL ;
    PORT
      LAYER met3 ;
        RECT -2.000 1803.140 0.300 1803.490 ;
    END
  END gpio_dm2[43]
  PIN gpio_dm2[44]
    DIRECTION OUTPUT ;
    USE SIGNAL ;
    PORT
      LAYER met3 ;
        RECT -2.000 1587.140 0.300 1587.490 ;
    END
  END gpio_dm2[44]
  PIN gpio_dm2[45]
    DIRECTION OUTPUT ;
    USE SIGNAL ;
    PORT
      LAYER met3 ;
        RECT -2.000 1371.140 0.300 1371.490 ;
    END
  END gpio_dm2[45]
  PIN gpio_dm2[46]
    DIRECTION OUTPUT ;
    USE SIGNAL ;
    PORT
      LAYER met3 ;
        RECT -2.000 1155.140 0.300 1155.490 ;
    END
  END gpio_dm2[46]
  PIN gpio_dm2[47]
    DIRECTION OUTPUT ;
    USE SIGNAL ;
    PORT
      LAYER met3 ;
        RECT -2.000 939.140 0.300 939.490 ;
    END
  END gpio_dm2[47]
  PIN gpio_dm2[48]
    DIRECTION OUTPUT ;
    USE SIGNAL ;
    PORT
      LAYER met3 ;
        RECT -2.000 723.140 0.300 723.490 ;
    END
  END gpio_dm2[48]
  PIN gpio_dm2[49]
    DIRECTION OUTPUT ;
    USE SIGNAL ;
    PORT
      LAYER met2 ;
        RECT 775.170 -2.000 775.450 0.280 ;
    END
  END gpio_dm2[49]
  PIN gpio_dm2[4]
    DIRECTION OUTPUT ;
    USE SIGNAL ;
    PORT
      LAYER met3 ;
        RECT 6754.330 1245.140 6756.630 1245.490 ;
    END
  END gpio_dm2[4]
  PIN gpio_dm2[50]
    DIRECTION OUTPUT ;
    USE SIGNAL ;
    PORT
      LAYER met2 ;
        RECT 1318.170 -2.000 1318.450 0.280 ;
    END
  END gpio_dm2[50]
  PIN gpio_dm2[51]
    DIRECTION OUTPUT ;
    USE SIGNAL ;
    PORT
      LAYER met2 ;
        RECT 1592.170 -2.000 1592.450 0.280 ;
    END
  END gpio_dm2[51]
  PIN gpio_dm2[52]
    DIRECTION OUTPUT ;
    USE SIGNAL ;
    PORT
      LAYER met2 ;
        RECT 1866.170 -2.000 1866.450 0.280 ;
    END
  END gpio_dm2[52]
  PIN gpio_dm2[53]
    DIRECTION OUTPUT ;
    USE SIGNAL ;
    PORT
      LAYER met2 ;
        RECT 2140.170 -2.000 2140.450 0.280 ;
    END
  END gpio_dm2[53]
  PIN gpio_dm2[54]
    DIRECTION OUTPUT ;
    USE SIGNAL ;
    PORT
      LAYER met2 ;
        RECT 2414.170 -2.000 2414.450 0.280 ;
    END
  END gpio_dm2[54]
  PIN gpio_dm2[55]
    DIRECTION OUTPUT ;
    USE SIGNAL ;
    PORT
      LAYER met2 ;
        RECT 3228.650 -2.000 3228.930 0.280 ;
    END
  END gpio_dm2[55]
  PIN gpio_dm2[56]
    DIRECTION OUTPUT ;
    USE SIGNAL ;
    PORT
      LAYER met2 ;
        RECT 3502.650 -2.000 3502.930 0.280 ;
    END
  END gpio_dm2[56]
  PIN gpio_dm2[57]
    DIRECTION OUTPUT ;
    USE SIGNAL ;
    PORT
      LAYER met2 ;
        RECT 4363.170 -2.000 4363.450 0.280 ;
    END
  END gpio_dm2[57]
  PIN gpio_dm2[58]
    DIRECTION OUTPUT ;
    USE SIGNAL ;
    PORT
      LAYER met2 ;
        RECT 4906.170 -2.000 4906.450 0.280 ;
    END
  END gpio_dm2[58]
  PIN gpio_dm2[59]
    DIRECTION OUTPUT ;
    USE SIGNAL ;
    PORT
      LAYER met2 ;
        RECT 5180.170 -2.000 5180.450 0.280 ;
    END
  END gpio_dm2[59]
  PIN gpio_dm2[5]
    DIRECTION OUTPUT ;
    USE SIGNAL ;
    PORT
      LAYER met3 ;
        RECT 6754.330 1470.140 6756.630 1470.490 ;
    END
  END gpio_dm2[5]
  PIN gpio_dm2[60]
    DIRECTION OUTPUT ;
    USE SIGNAL ;
    PORT
      LAYER met2 ;
        RECT 5454.170 -2.000 5454.450 0.280 ;
    END
  END gpio_dm2[60]
  PIN gpio_dm2[61]
    DIRECTION OUTPUT ;
    USE SIGNAL ;
    PORT
      LAYER met2 ;
        RECT 5728.170 -2.000 5728.450 0.280 ;
    END
  END gpio_dm2[61]
  PIN gpio_dm2[62]
    DIRECTION OUTPUT ;
    USE SIGNAL ;
    PORT
      LAYER met2 ;
        RECT 6002.170 -2.000 6002.450 0.280 ;
    END
  END gpio_dm2[62]
  PIN gpio_dm2[6]
    DIRECTION OUTPUT ;
    USE SIGNAL ;
    PORT
      LAYER met3 ;
        RECT 6754.330 1696.140 6756.630 1696.490 ;
    END
  END gpio_dm2[6]
  PIN gpio_dm2[7]
    DIRECTION OUTPUT ;
    USE SIGNAL ;
    PORT
      LAYER met3 ;
        RECT 6754.330 2582.140 6756.630 2582.490 ;
    END
  END gpio_dm2[7]
  PIN gpio_dm2[8]
    DIRECTION OUTPUT ;
    USE SIGNAL ;
    PORT
      LAYER met3 ;
        RECT 6754.330 2808.140 6756.630 2808.490 ;
    END
  END gpio_dm2[8]
  PIN gpio_dm2[9]
    DIRECTION OUTPUT ;
    USE SIGNAL ;
    PORT
      LAYER met3 ;
        RECT 6754.330 3033.140 6756.630 3033.490 ;
    END
  END gpio_dm2[9]
  PIN gpio_holdover[0]
    DIRECTION OUTPUT ;
    USE SIGNAL ;
    PORT
      LAYER met3 ;
        RECT 6754.330 346.360 6756.630 346.710 ;
    END
  END gpio_holdover[0]
  PIN gpio_holdover[10]
    DIRECTION OUTPUT ;
    USE SIGNAL ;
    PORT
      LAYER met3 ;
        RECT 6754.330 3262.360 6756.630 3262.710 ;
    END
  END gpio_holdover[10]
  PIN gpio_holdover[11]
    DIRECTION OUTPUT ;
    USE SIGNAL ;
    PORT
      LAYER met3 ;
        RECT 6754.330 3487.360 6756.630 3487.710 ;
    END
  END gpio_holdover[11]
  PIN gpio_holdover[12]
    DIRECTION OUTPUT ;
    USE SIGNAL ;
    PORT
      LAYER met3 ;
        RECT 6754.330 3712.360 6756.630 3712.710 ;
    END
  END gpio_holdover[12]
  PIN gpio_holdover[13]
    DIRECTION OUTPUT ;
    USE SIGNAL ;
    PORT
      LAYER met3 ;
        RECT 6754.330 4158.360 6756.630 4158.710 ;
    END
  END gpio_holdover[13]
  PIN gpio_holdover[14]
    DIRECTION OUTPUT ;
    USE SIGNAL ;
    PORT
      LAYER met3 ;
        RECT 6754.330 4604.360 6756.630 4604.710 ;
    END
  END gpio_holdover[14]
  PIN gpio_holdover[15]
    DIRECTION OUTPUT ;
    USE SIGNAL ;
    PORT
      LAYER met2 ;
        RECT 6529.960 4766.350 6530.240 4768.630 ;
    END
  END gpio_holdover[15]
  PIN gpio_holdover[16]
    DIRECTION OUTPUT ;
    USE SIGNAL ;
    PORT
      LAYER met2 ;
        RECT 6020.960 4766.350 6021.240 4768.630 ;
    END
  END gpio_holdover[16]
  PIN gpio_holdover[17]
    DIRECTION OUTPUT ;
    USE SIGNAL ;
    PORT
      LAYER met2 ;
        RECT 5763.960 4766.350 5764.240 4768.630 ;
    END
  END gpio_holdover[17]
  PIN gpio_holdover[18]
    DIRECTION OUTPUT ;
    USE SIGNAL ;
    PORT
      LAYER met2 ;
        RECT 5318.960 4766.350 5319.240 4768.630 ;
    END
  END gpio_holdover[18]
  PIN gpio_holdover[19]
    DIRECTION OUTPUT ;
    USE SIGNAL ;
    PORT
      LAYER met2 ;
        RECT 4809.960 4766.350 4810.240 4768.630 ;
    END
  END gpio_holdover[19]
  PIN gpio_holdover[1]
    DIRECTION OUTPUT ;
    USE SIGNAL ;
    PORT
      LAYER met3 ;
        RECT 6754.330 572.360 6756.630 572.710 ;
    END
  END gpio_holdover[1]
  PIN gpio_holdover[20]
    DIRECTION OUTPUT ;
    USE SIGNAL ;
    PORT
      LAYER met2 ;
        RECT 4551.960 4766.350 4552.240 4768.630 ;
    END
  END gpio_holdover[20]
  PIN gpio_holdover[21]
    DIRECTION OUTPUT ;
    USE SIGNAL ;
    PORT
      LAYER met2 ;
        RECT 4294.960 4766.350 4295.240 4768.630 ;
    END
  END gpio_holdover[21]
  PIN gpio_holdover[22]
    DIRECTION OUTPUT ;
    USE SIGNAL ;
    PORT
      LAYER met2 ;
        RECT 4037.960 4766.350 4038.240 4768.630 ;
    END
  END gpio_holdover[22]
  PIN gpio_holdover[23]
    DIRECTION OUTPUT ;
    USE SIGNAL ;
    PORT
      LAYER met2 ;
        RECT 3780.960 4766.350 3781.240 4768.630 ;
    END
  END gpio_holdover[23]
  PIN gpio_holdover[24]
    DIRECTION OUTPUT ;
    USE SIGNAL ;
    PORT
      LAYER met2 ;
        RECT 3455.960 4766.350 3456.240 4768.630 ;
    END
  END gpio_holdover[24]
  PIN gpio_holdover[25]
    DIRECTION OUTPUT ;
    USE SIGNAL ;
    PORT
      LAYER met2 ;
        RECT 3198.960 4766.350 3199.240 4768.630 ;
    END
  END gpio_holdover[25]
  PIN gpio_holdover[26]
    DIRECTION OUTPUT ;
    USE SIGNAL ;
    PORT
      LAYER met2 ;
        RECT 2941.960 4766.350 2942.240 4768.630 ;
    END
  END gpio_holdover[26]
  PIN gpio_holdover[27]
    DIRECTION OUTPUT ;
    USE SIGNAL ;
    PORT
      LAYER met2 ;
        RECT 2432.960 4766.350 2433.240 4768.630 ;
    END
  END gpio_holdover[27]
  PIN gpio_holdover[28]
    DIRECTION OUTPUT ;
    USE SIGNAL ;
    PORT
      LAYER met2 ;
        RECT 2175.960 4766.350 2176.240 4768.630 ;
    END
  END gpio_holdover[28]
  PIN gpio_holdover[29]
    DIRECTION OUTPUT ;
    USE SIGNAL ;
    PORT
      LAYER met2 ;
        RECT 1730.960 4766.350 1731.240 4768.630 ;
    END
  END gpio_holdover[29]
  PIN gpio_holdover[2]
    DIRECTION OUTPUT ;
    USE SIGNAL ;
    PORT
      LAYER met3 ;
        RECT 6754.330 797.360 6756.630 797.710 ;
    END
  END gpio_holdover[2]
  PIN gpio_holdover[30]
    DIRECTION OUTPUT ;
    USE SIGNAL ;
    PORT
      LAYER met2 ;
        RECT 1221.960 4766.350 1222.240 4768.630 ;
    END
  END gpio_holdover[30]
  PIN gpio_holdover[31]
    DIRECTION OUTPUT ;
    USE SIGNAL ;
    PORT
      LAYER met2 ;
        RECT 963.960 4766.350 964.240 4768.630 ;
    END
  END gpio_holdover[31]
  PIN gpio_holdover[32]
    DIRECTION OUTPUT ;
    USE SIGNAL ;
    PORT
      LAYER met2 ;
        RECT 706.960 4766.350 707.240 4768.630 ;
    END
  END gpio_holdover[32]
  PIN gpio_holdover[33]
    DIRECTION OUTPUT ;
    USE SIGNAL ;
    PORT
      LAYER met2 ;
        RECT 449.960 4766.350 450.240 4768.630 ;
    END
  END gpio_holdover[33]
  PIN gpio_holdover[34]
    DIRECTION OUTPUT ;
    USE SIGNAL ;
    PORT
      LAYER met2 ;
        RECT 192.960 4766.350 193.240 4768.630 ;
    END
  END gpio_holdover[34]
  PIN gpio_holdover[35]
    DIRECTION OUTPUT ;
    USE SIGNAL ;
    PORT
      LAYER met3 ;
        RECT -2.000 4582.920 0.300 4583.270 ;
    END
  END gpio_holdover[35]
  PIN gpio_holdover[36]
    DIRECTION OUTPUT ;
    USE SIGNAL ;
    PORT
      LAYER met3 ;
        RECT -2.000 3733.920 0.300 3734.270 ;
    END
  END gpio_holdover[36]
  PIN gpio_holdover[37]
    DIRECTION OUTPUT ;
    USE SIGNAL ;
    PORT
      LAYER met3 ;
        RECT -2.000 3517.920 0.300 3518.270 ;
    END
  END gpio_holdover[37]
  PIN gpio_holdover[38]
    DIRECTION OUTPUT ;
    USE SIGNAL ;
    PORT
      LAYER met3 ;
        RECT -2.000 3301.920 0.300 3302.270 ;
    END
  END gpio_holdover[38]
  PIN gpio_holdover[39]
    DIRECTION OUTPUT ;
    USE SIGNAL ;
    PORT
      LAYER met3 ;
        RECT -2.000 3085.920 0.300 3086.270 ;
    END
  END gpio_holdover[39]
  PIN gpio_holdover[3]
    DIRECTION OUTPUT ;
    USE SIGNAL ;
    PORT
      LAYER met3 ;
        RECT 6754.330 1023.360 6756.630 1023.710 ;
    END
  END gpio_holdover[3]
  PIN gpio_holdover[40]
    DIRECTION OUTPUT ;
    USE SIGNAL ;
    PORT
      LAYER met3 ;
        RECT -2.000 2869.920 0.300 2870.270 ;
    END
  END gpio_holdover[40]
  PIN gpio_holdover[41]
    DIRECTION OUTPUT ;
    USE SIGNAL ;
    PORT
      LAYER met3 ;
        RECT -2.000 2653.920 0.300 2654.270 ;
    END
  END gpio_holdover[41]
  PIN gpio_holdover[42]
    DIRECTION OUTPUT ;
    USE SIGNAL ;
    PORT
      LAYER met3 ;
        RECT -2.000 2437.920 0.300 2438.270 ;
    END
  END gpio_holdover[42]
  PIN gpio_holdover[43]
    DIRECTION OUTPUT ;
    USE SIGNAL ;
    PORT
      LAYER met3 ;
        RECT -2.000 1799.920 0.300 1800.270 ;
    END
  END gpio_holdover[43]
  PIN gpio_holdover[44]
    DIRECTION OUTPUT ;
    USE SIGNAL ;
    PORT
      LAYER met3 ;
        RECT -2.000 1583.920 0.300 1584.270 ;
    END
  END gpio_holdover[44]
  PIN gpio_holdover[45]
    DIRECTION OUTPUT ;
    USE SIGNAL ;
    PORT
      LAYER met3 ;
        RECT -2.000 1367.920 0.300 1368.270 ;
    END
  END gpio_holdover[45]
  PIN gpio_holdover[46]
    DIRECTION OUTPUT ;
    USE SIGNAL ;
    PORT
      LAYER met3 ;
        RECT -2.000 1151.920 0.300 1152.270 ;
    END
  END gpio_holdover[46]
  PIN gpio_holdover[47]
    DIRECTION OUTPUT ;
    USE SIGNAL ;
    PORT
      LAYER met3 ;
        RECT -2.000 935.920 0.300 936.270 ;
    END
  END gpio_holdover[47]
  PIN gpio_holdover[48]
    DIRECTION OUTPUT ;
    USE SIGNAL ;
    PORT
      LAYER met3 ;
        RECT -2.000 719.920 0.300 720.270 ;
    END
  END gpio_holdover[48]
  PIN gpio_holdover[49]
    DIRECTION OUTPUT ;
    USE SIGNAL ;
    PORT
      LAYER met2 ;
        RECT 778.390 -2.000 778.670 0.280 ;
    END
  END gpio_holdover[49]
  PIN gpio_holdover[4]
    DIRECTION OUTPUT ;
    USE SIGNAL ;
    PORT
      LAYER met3 ;
        RECT 6754.330 1248.360 6756.630 1248.710 ;
    END
  END gpio_holdover[4]
  PIN gpio_holdover[50]
    DIRECTION OUTPUT ;
    USE SIGNAL ;
    PORT
      LAYER met2 ;
        RECT 1321.390 -2.000 1321.670 0.280 ;
    END
  END gpio_holdover[50]
  PIN gpio_holdover[51]
    DIRECTION OUTPUT ;
    USE SIGNAL ;
    PORT
      LAYER met2 ;
        RECT 1595.390 -2.000 1595.670 0.280 ;
    END
  END gpio_holdover[51]
  PIN gpio_holdover[52]
    DIRECTION OUTPUT ;
    USE SIGNAL ;
    PORT
      LAYER met2 ;
        RECT 1869.390 -2.000 1869.670 0.280 ;
    END
  END gpio_holdover[52]
  PIN gpio_holdover[53]
    DIRECTION OUTPUT ;
    USE SIGNAL ;
    PORT
      LAYER met2 ;
        RECT 2143.390 -2.000 2143.670 0.280 ;
    END
  END gpio_holdover[53]
  PIN gpio_holdover[54]
    DIRECTION OUTPUT ;
    USE SIGNAL ;
    PORT
      LAYER met2 ;
        RECT 2417.390 -2.000 2417.670 0.280 ;
    END
  END gpio_holdover[54]
  PIN gpio_holdover[55]
    DIRECTION OUTPUT ;
    USE SIGNAL ;
    PORT
      LAYER met2 ;
        RECT 3231.870 -2.000 3232.150 0.280 ;
    END
  END gpio_holdover[55]
  PIN gpio_holdover[56]
    DIRECTION OUTPUT ;
    USE SIGNAL ;
    PORT
      LAYER met2 ;
        RECT 3505.870 -2.000 3506.150 0.280 ;
    END
  END gpio_holdover[56]
  PIN gpio_holdover[57]
    DIRECTION OUTPUT ;
    USE SIGNAL ;
    PORT
      LAYER met2 ;
        RECT 4366.390 -2.000 4366.670 0.280 ;
    END
  END gpio_holdover[57]
  PIN gpio_holdover[58]
    DIRECTION OUTPUT ;
    USE SIGNAL ;
    PORT
      LAYER met2 ;
        RECT 4909.390 -2.000 4909.670 0.280 ;
    END
  END gpio_holdover[58]
  PIN gpio_holdover[59]
    DIRECTION OUTPUT ;
    USE SIGNAL ;
    PORT
      LAYER met2 ;
        RECT 5183.390 -2.000 5183.670 0.280 ;
    END
  END gpio_holdover[59]
  PIN gpio_holdover[5]
    DIRECTION OUTPUT ;
    USE SIGNAL ;
    PORT
      LAYER met3 ;
        RECT 6754.330 1473.360 6756.630 1473.710 ;
    END
  END gpio_holdover[5]
  PIN gpio_holdover[60]
    DIRECTION OUTPUT ;
    USE SIGNAL ;
    PORT
      LAYER met2 ;
        RECT 5457.390 -2.000 5457.670 0.280 ;
    END
  END gpio_holdover[60]
  PIN gpio_holdover[61]
    DIRECTION OUTPUT ;
    USE SIGNAL ;
    PORT
      LAYER met2 ;
        RECT 5731.390 -2.000 5731.670 0.280 ;
    END
  END gpio_holdover[61]
  PIN gpio_holdover[62]
    DIRECTION OUTPUT ;
    USE SIGNAL ;
    PORT
      LAYER met2 ;
        RECT 6005.390 -2.000 6005.670 0.280 ;
    END
  END gpio_holdover[62]
  PIN gpio_holdover[6]
    DIRECTION OUTPUT ;
    USE SIGNAL ;
    PORT
      LAYER met3 ;
        RECT 6754.330 1699.360 6756.630 1699.710 ;
    END
  END gpio_holdover[6]
  PIN gpio_holdover[7]
    DIRECTION OUTPUT ;
    USE SIGNAL ;
    PORT
      LAYER met3 ;
        RECT 6754.330 2585.360 6756.630 2585.710 ;
    END
  END gpio_holdover[7]
  PIN gpio_holdover[8]
    DIRECTION OUTPUT ;
    USE SIGNAL ;
    PORT
      LAYER met3 ;
        RECT 6754.330 2811.360 6756.630 2811.710 ;
    END
  END gpio_holdover[8]
  PIN gpio_holdover[9]
    DIRECTION OUTPUT ;
    USE SIGNAL ;
    PORT
      LAYER met3 ;
        RECT 6754.330 3036.360 6756.630 3036.710 ;
    END
  END gpio_holdover[9]
  PIN gpio_ib_mode_sel[0]
    DIRECTION OUTPUT ;
    USE SIGNAL ;
    PORT
      LAYER met3 ;
        RECT 6754.330 361.540 6756.630 361.890 ;
    END
  END gpio_ib_mode_sel[0]
  PIN gpio_ib_mode_sel[10]
    DIRECTION OUTPUT ;
    USE SIGNAL ;
    PORT
      LAYER met3 ;
        RECT 6754.330 3277.540 6756.630 3277.890 ;
    END
  END gpio_ib_mode_sel[10]
  PIN gpio_ib_mode_sel[11]
    DIRECTION OUTPUT ;
    USE SIGNAL ;
    PORT
      LAYER met3 ;
        RECT 6754.330 3502.540 6756.630 3502.890 ;
    END
  END gpio_ib_mode_sel[11]
  PIN gpio_ib_mode_sel[12]
    DIRECTION OUTPUT ;
    USE SIGNAL ;
    PORT
      LAYER met3 ;
        RECT 6754.330 3727.540 6756.630 3727.890 ;
    END
  END gpio_ib_mode_sel[12]
  PIN gpio_ib_mode_sel[13]
    DIRECTION OUTPUT ;
    USE SIGNAL ;
    PORT
      LAYER met3 ;
        RECT 6754.330 4173.540 6756.630 4173.890 ;
    END
  END gpio_ib_mode_sel[13]
  PIN gpio_ib_mode_sel[14]
    DIRECTION OUTPUT ;
    USE SIGNAL ;
    PORT
      LAYER met3 ;
        RECT 6754.330 4619.540 6756.630 4619.890 ;
    END
  END gpio_ib_mode_sel[14]
  PIN gpio_ib_mode_sel[15]
    DIRECTION OUTPUT ;
    USE SIGNAL ;
    PORT
      LAYER met2 ;
        RECT 6514.780 4766.350 6515.060 4768.630 ;
    END
  END gpio_ib_mode_sel[15]
  PIN gpio_ib_mode_sel[16]
    DIRECTION OUTPUT ;
    USE SIGNAL ;
    PORT
      LAYER met2 ;
        RECT 6005.780 4766.350 6006.060 4768.630 ;
    END
  END gpio_ib_mode_sel[16]
  PIN gpio_ib_mode_sel[17]
    DIRECTION OUTPUT ;
    USE SIGNAL ;
    PORT
      LAYER met2 ;
        RECT 5748.780 4766.350 5749.060 4768.630 ;
    END
  END gpio_ib_mode_sel[17]
  PIN gpio_ib_mode_sel[18]
    DIRECTION OUTPUT ;
    USE SIGNAL ;
    PORT
      LAYER met2 ;
        RECT 5303.780 4766.350 5304.060 4768.630 ;
    END
  END gpio_ib_mode_sel[18]
  PIN gpio_ib_mode_sel[19]
    DIRECTION OUTPUT ;
    USE SIGNAL ;
    PORT
      LAYER met2 ;
        RECT 4794.780 4766.350 4795.060 4768.630 ;
    END
  END gpio_ib_mode_sel[19]
  PIN gpio_ib_mode_sel[1]
    DIRECTION OUTPUT ;
    USE SIGNAL ;
    PORT
      LAYER met3 ;
        RECT 6754.330 587.540 6756.630 587.890 ;
    END
  END gpio_ib_mode_sel[1]
  PIN gpio_ib_mode_sel[20]
    DIRECTION OUTPUT ;
    USE SIGNAL ;
    PORT
      LAYER met2 ;
        RECT 4536.780 4766.350 4537.060 4768.630 ;
    END
  END gpio_ib_mode_sel[20]
  PIN gpio_ib_mode_sel[21]
    DIRECTION OUTPUT ;
    USE SIGNAL ;
    PORT
      LAYER met2 ;
        RECT 4279.780 4766.350 4280.060 4768.630 ;
    END
  END gpio_ib_mode_sel[21]
  PIN gpio_ib_mode_sel[22]
    DIRECTION OUTPUT ;
    USE SIGNAL ;
    PORT
      LAYER met2 ;
        RECT 4022.780 4766.350 4023.060 4768.630 ;
    END
  END gpio_ib_mode_sel[22]
  PIN gpio_ib_mode_sel[23]
    DIRECTION OUTPUT ;
    USE SIGNAL ;
    PORT
      LAYER met2 ;
        RECT 3765.780 4766.350 3766.060 4768.630 ;
    END
  END gpio_ib_mode_sel[23]
  PIN gpio_ib_mode_sel[24]
    DIRECTION OUTPUT ;
    USE SIGNAL ;
    PORT
      LAYER met2 ;
        RECT 3440.780 4766.350 3441.060 4768.630 ;
    END
  END gpio_ib_mode_sel[24]
  PIN gpio_ib_mode_sel[25]
    DIRECTION OUTPUT ;
    USE SIGNAL ;
    PORT
      LAYER met2 ;
        RECT 3183.780 4766.350 3184.060 4768.630 ;
    END
  END gpio_ib_mode_sel[25]
  PIN gpio_ib_mode_sel[26]
    DIRECTION OUTPUT ;
    USE SIGNAL ;
    PORT
      LAYER met2 ;
        RECT 2926.780 4766.350 2927.060 4768.630 ;
    END
  END gpio_ib_mode_sel[26]
  PIN gpio_ib_mode_sel[27]
    DIRECTION OUTPUT ;
    USE SIGNAL ;
    PORT
      LAYER met2 ;
        RECT 2417.780 4766.350 2418.060 4768.630 ;
    END
  END gpio_ib_mode_sel[27]
  PIN gpio_ib_mode_sel[28]
    DIRECTION OUTPUT ;
    USE SIGNAL ;
    PORT
      LAYER met2 ;
        RECT 2160.780 4766.350 2161.060 4768.630 ;
    END
  END gpio_ib_mode_sel[28]
  PIN gpio_ib_mode_sel[29]
    DIRECTION OUTPUT ;
    USE SIGNAL ;
    PORT
      LAYER met2 ;
        RECT 1715.780 4766.350 1716.060 4768.630 ;
    END
  END gpio_ib_mode_sel[29]
  PIN gpio_ib_mode_sel[2]
    DIRECTION OUTPUT ;
    USE SIGNAL ;
    PORT
      LAYER met3 ;
        RECT 6754.330 812.540 6756.630 812.890 ;
    END
  END gpio_ib_mode_sel[2]
  PIN gpio_ib_mode_sel[30]
    DIRECTION OUTPUT ;
    USE SIGNAL ;
    PORT
      LAYER met2 ;
        RECT 1206.780 4766.350 1207.060 4768.630 ;
    END
  END gpio_ib_mode_sel[30]
  PIN gpio_ib_mode_sel[31]
    DIRECTION OUTPUT ;
    USE SIGNAL ;
    PORT
      LAYER met2 ;
        RECT 948.780 4766.350 949.060 4768.630 ;
    END
  END gpio_ib_mode_sel[31]
  PIN gpio_ib_mode_sel[32]
    DIRECTION OUTPUT ;
    USE SIGNAL ;
    PORT
      LAYER met2 ;
        RECT 691.780 4766.350 692.060 4768.630 ;
    END
  END gpio_ib_mode_sel[32]
  PIN gpio_ib_mode_sel[33]
    DIRECTION OUTPUT ;
    USE SIGNAL ;
    PORT
      LAYER met2 ;
        RECT 434.780 4766.350 435.060 4768.630 ;
    END
  END gpio_ib_mode_sel[33]
  PIN gpio_ib_mode_sel[34]
    DIRECTION OUTPUT ;
    USE SIGNAL ;
    PORT
      LAYER met2 ;
        RECT 177.780 4766.350 178.060 4768.630 ;
    END
  END gpio_ib_mode_sel[34]
  PIN gpio_ib_mode_sel[35]
    DIRECTION OUTPUT ;
    USE SIGNAL ;
    PORT
      LAYER met3 ;
        RECT -2.000 4567.740 0.300 4568.090 ;
    END
  END gpio_ib_mode_sel[35]
  PIN gpio_ib_mode_sel[36]
    DIRECTION OUTPUT ;
    USE SIGNAL ;
    PORT
      LAYER met3 ;
        RECT -2.000 3718.740 0.300 3719.090 ;
    END
  END gpio_ib_mode_sel[36]
  PIN gpio_ib_mode_sel[37]
    DIRECTION OUTPUT ;
    USE SIGNAL ;
    PORT
      LAYER met3 ;
        RECT -2.000 3502.740 0.300 3503.090 ;
    END
  END gpio_ib_mode_sel[37]
  PIN gpio_ib_mode_sel[38]
    DIRECTION OUTPUT ;
    USE SIGNAL ;
    PORT
      LAYER met3 ;
        RECT -2.000 3286.740 0.300 3287.090 ;
    END
  END gpio_ib_mode_sel[38]
  PIN gpio_ib_mode_sel[39]
    DIRECTION OUTPUT ;
    USE SIGNAL ;
    PORT
      LAYER met3 ;
        RECT -2.000 3070.740 0.300 3071.090 ;
    END
  END gpio_ib_mode_sel[39]
  PIN gpio_ib_mode_sel[3]
    DIRECTION OUTPUT ;
    USE SIGNAL ;
    PORT
      LAYER met3 ;
        RECT 6754.330 1038.540 6756.630 1038.890 ;
    END
  END gpio_ib_mode_sel[3]
  PIN gpio_ib_mode_sel[40]
    DIRECTION OUTPUT ;
    USE SIGNAL ;
    PORT
      LAYER met3 ;
        RECT -2.000 2854.740 0.300 2855.090 ;
    END
  END gpio_ib_mode_sel[40]
  PIN gpio_ib_mode_sel[41]
    DIRECTION OUTPUT ;
    USE SIGNAL ;
    PORT
      LAYER met3 ;
        RECT -2.000 2638.740 0.300 2639.090 ;
    END
  END gpio_ib_mode_sel[41]
  PIN gpio_ib_mode_sel[42]
    DIRECTION OUTPUT ;
    USE SIGNAL ;
    PORT
      LAYER met3 ;
        RECT -2.000 2422.740 0.300 2423.090 ;
    END
  END gpio_ib_mode_sel[42]
  PIN gpio_ib_mode_sel[43]
    DIRECTION OUTPUT ;
    USE SIGNAL ;
    PORT
      LAYER met3 ;
        RECT -2.000 1784.740 0.300 1785.090 ;
    END
  END gpio_ib_mode_sel[43]
  PIN gpio_ib_mode_sel[44]
    DIRECTION OUTPUT ;
    USE SIGNAL ;
    PORT
      LAYER met3 ;
        RECT -2.000 1568.740 0.300 1569.090 ;
    END
  END gpio_ib_mode_sel[44]
  PIN gpio_ib_mode_sel[45]
    DIRECTION OUTPUT ;
    USE SIGNAL ;
    PORT
      LAYER met3 ;
        RECT -2.000 1352.740 0.300 1353.090 ;
    END
  END gpio_ib_mode_sel[45]
  PIN gpio_ib_mode_sel[46]
    DIRECTION OUTPUT ;
    USE SIGNAL ;
    PORT
      LAYER met3 ;
        RECT -2.000 1136.740 0.300 1137.090 ;
    END
  END gpio_ib_mode_sel[46]
  PIN gpio_ib_mode_sel[47]
    DIRECTION OUTPUT ;
    USE SIGNAL ;
    PORT
      LAYER met3 ;
        RECT -2.000 920.740 0.300 921.090 ;
    END
  END gpio_ib_mode_sel[47]
  PIN gpio_ib_mode_sel[48]
    DIRECTION OUTPUT ;
    USE SIGNAL ;
    PORT
      LAYER met3 ;
        RECT -2.000 704.740 0.300 705.090 ;
    END
  END gpio_ib_mode_sel[48]
  PIN gpio_ib_mode_sel[49]
    DIRECTION OUTPUT ;
    USE SIGNAL ;
    PORT
      LAYER met2 ;
        RECT 793.570 -2.000 793.850 0.280 ;
    END
  END gpio_ib_mode_sel[49]
  PIN gpio_ib_mode_sel[4]
    DIRECTION OUTPUT ;
    USE SIGNAL ;
    PORT
      LAYER met3 ;
        RECT 6754.330 1263.540 6756.630 1263.890 ;
    END
  END gpio_ib_mode_sel[4]
  PIN gpio_ib_mode_sel[50]
    DIRECTION OUTPUT ;
    USE SIGNAL ;
    PORT
      LAYER met2 ;
        RECT 1336.570 -2.000 1336.850 0.280 ;
    END
  END gpio_ib_mode_sel[50]
  PIN gpio_ib_mode_sel[51]
    DIRECTION OUTPUT ;
    USE SIGNAL ;
    PORT
      LAYER met2 ;
        RECT 1610.570 -2.000 1610.850 0.280 ;
    END
  END gpio_ib_mode_sel[51]
  PIN gpio_ib_mode_sel[52]
    DIRECTION OUTPUT ;
    USE SIGNAL ;
    PORT
      LAYER met2 ;
        RECT 1884.570 -2.000 1884.850 0.280 ;
    END
  END gpio_ib_mode_sel[52]
  PIN gpio_ib_mode_sel[53]
    DIRECTION OUTPUT ;
    USE SIGNAL ;
    PORT
      LAYER met2 ;
        RECT 2158.570 -2.000 2158.850 0.280 ;
    END
  END gpio_ib_mode_sel[53]
  PIN gpio_ib_mode_sel[54]
    DIRECTION OUTPUT ;
    USE SIGNAL ;
    PORT
      LAYER met2 ;
        RECT 2432.570 -2.000 2432.850 0.280 ;
    END
  END gpio_ib_mode_sel[54]
  PIN gpio_ib_mode_sel[55]
    DIRECTION OUTPUT ;
    USE SIGNAL ;
    PORT
      LAYER met2 ;
        RECT 3247.050 -2.000 3247.330 0.280 ;
    END
  END gpio_ib_mode_sel[55]
  PIN gpio_ib_mode_sel[56]
    DIRECTION OUTPUT ;
    USE SIGNAL ;
    PORT
      LAYER met2 ;
        RECT 3521.050 -2.000 3521.330 0.280 ;
    END
  END gpio_ib_mode_sel[56]
  PIN gpio_ib_mode_sel[57]
    DIRECTION OUTPUT ;
    USE SIGNAL ;
    PORT
      LAYER met2 ;
        RECT 4381.570 -2.000 4381.850 0.280 ;
    END
  END gpio_ib_mode_sel[57]
  PIN gpio_ib_mode_sel[58]
    DIRECTION OUTPUT ;
    USE SIGNAL ;
    PORT
      LAYER met2 ;
        RECT 4924.570 -2.000 4924.850 0.280 ;
    END
  END gpio_ib_mode_sel[58]
  PIN gpio_ib_mode_sel[59]
    DIRECTION OUTPUT ;
    USE SIGNAL ;
    PORT
      LAYER met2 ;
        RECT 5198.570 -2.000 5198.850 0.280 ;
    END
  END gpio_ib_mode_sel[59]
  PIN gpio_ib_mode_sel[5]
    DIRECTION OUTPUT ;
    USE SIGNAL ;
    PORT
      LAYER met3 ;
        RECT 6754.330 1488.540 6756.630 1488.890 ;
    END
  END gpio_ib_mode_sel[5]
  PIN gpio_ib_mode_sel[60]
    DIRECTION OUTPUT ;
    USE SIGNAL ;
    PORT
      LAYER met2 ;
        RECT 5472.570 -2.000 5472.850 0.280 ;
    END
  END gpio_ib_mode_sel[60]
  PIN gpio_ib_mode_sel[61]
    DIRECTION OUTPUT ;
    USE SIGNAL ;
    PORT
      LAYER met2 ;
        RECT 5746.570 -2.000 5746.850 0.280 ;
    END
  END gpio_ib_mode_sel[61]
  PIN gpio_ib_mode_sel[62]
    DIRECTION OUTPUT ;
    USE SIGNAL ;
    PORT
      LAYER met2 ;
        RECT 6020.570 -2.000 6020.850 0.280 ;
    END
  END gpio_ib_mode_sel[62]
  PIN gpio_ib_mode_sel[6]
    DIRECTION OUTPUT ;
    USE SIGNAL ;
    PORT
      LAYER met3 ;
        RECT 6754.330 1714.540 6756.630 1714.890 ;
    END
  END gpio_ib_mode_sel[6]
  PIN gpio_ib_mode_sel[7]
    DIRECTION OUTPUT ;
    USE SIGNAL ;
    PORT
      LAYER met3 ;
        RECT 6754.330 2600.540 6756.630 2600.890 ;
    END
  END gpio_ib_mode_sel[7]
  PIN gpio_ib_mode_sel[8]
    DIRECTION OUTPUT ;
    USE SIGNAL ;
    PORT
      LAYER met3 ;
        RECT 6754.330 2826.540 6756.630 2826.890 ;
    END
  END gpio_ib_mode_sel[8]
  PIN gpio_ib_mode_sel[9]
    DIRECTION OUTPUT ;
    USE SIGNAL ;
    PORT
      LAYER met3 ;
        RECT 6754.330 3051.540 6756.630 3051.890 ;
    END
  END gpio_ib_mode_sel[9]
  PIN gpio_in[0]
    DIRECTION INPUT ;
    USE SIGNAL ;
    PORT
      LAYER met3 ;
        RECT 6754.330 293.920 6756.630 294.270 ;
    END
  END gpio_in[0]
  PIN gpio_in[10]
    DIRECTION INPUT ;
    USE SIGNAL ;
    PORT
      LAYER met3 ;
        RECT 6754.330 3209.920 6756.630 3210.270 ;
    END
  END gpio_in[10]
  PIN gpio_in[11]
    DIRECTION INPUT ;
    USE SIGNAL ;
    PORT
      LAYER met3 ;
        RECT 6754.330 3434.920 6756.630 3435.270 ;
    END
  END gpio_in[11]
  PIN gpio_in[12]
    DIRECTION INPUT ;
    USE SIGNAL ;
    PORT
      LAYER met3 ;
        RECT 6754.330 3659.920 6756.630 3660.270 ;
    END
  END gpio_in[12]
  PIN gpio_in[13]
    DIRECTION INPUT ;
    USE SIGNAL ;
    PORT
      LAYER met3 ;
        RECT 6754.330 4105.920 6756.630 4106.270 ;
    END
  END gpio_in[13]
  PIN gpio_in[14]
    DIRECTION INPUT ;
    USE SIGNAL ;
    PORT
      LAYER met3 ;
        RECT 6754.330 4551.920 6756.630 4552.270 ;
    END
  END gpio_in[14]
  PIN gpio_in[15]
    DIRECTION INPUT ;
    USE SIGNAL ;
    PORT
      LAYER met2 ;
        RECT 6582.400 4766.350 6582.680 4768.630 ;
    END
  END gpio_in[15]
  PIN gpio_in[16]
    DIRECTION INPUT ;
    USE SIGNAL ;
    PORT
      LAYER met2 ;
        RECT 6073.400 4766.350 6073.680 4768.630 ;
    END
  END gpio_in[16]
  PIN gpio_in[17]
    DIRECTION INPUT ;
    USE SIGNAL ;
    PORT
      LAYER met2 ;
        RECT 5816.400 4766.350 5816.680 4768.630 ;
    END
  END gpio_in[17]
  PIN gpio_in[18]
    DIRECTION INPUT ;
    USE SIGNAL ;
    PORT
      LAYER met2 ;
        RECT 5371.400 4766.350 5371.680 4768.630 ;
    END
  END gpio_in[18]
  PIN gpio_in[19]
    DIRECTION INPUT ;
    USE SIGNAL ;
    PORT
      LAYER met2 ;
        RECT 4862.400 4766.350 4862.680 4768.630 ;
    END
  END gpio_in[19]
  PIN gpio_in[1]
    DIRECTION INPUT ;
    USE SIGNAL ;
    PORT
      LAYER met3 ;
        RECT 6754.330 519.920 6756.630 520.270 ;
    END
  END gpio_in[1]
  PIN gpio_in[20]
    DIRECTION INPUT ;
    USE SIGNAL ;
    PORT
      LAYER met2 ;
        RECT 4604.400 4766.350 4604.680 4768.630 ;
    END
  END gpio_in[20]
  PIN gpio_in[21]
    DIRECTION INPUT ;
    USE SIGNAL ;
    PORT
      LAYER met2 ;
        RECT 4347.400 4766.350 4347.680 4768.630 ;
    END
  END gpio_in[21]
  PIN gpio_in[22]
    DIRECTION INPUT ;
    USE SIGNAL ;
    PORT
      LAYER met2 ;
        RECT 4090.400 4766.350 4090.680 4768.630 ;
    END
  END gpio_in[22]
  PIN gpio_in[23]
    DIRECTION INPUT ;
    USE SIGNAL ;
    PORT
      LAYER met2 ;
        RECT 3833.400 4766.350 3833.680 4768.630 ;
    END
  END gpio_in[23]
  PIN gpio_in[24]
    DIRECTION INPUT ;
    USE SIGNAL ;
    PORT
      LAYER met2 ;
        RECT 3508.400 4766.350 3508.680 4768.630 ;
    END
  END gpio_in[24]
  PIN gpio_in[25]
    DIRECTION INPUT ;
    USE SIGNAL ;
    PORT
      LAYER met2 ;
        RECT 3251.400 4766.350 3251.680 4768.630 ;
    END
  END gpio_in[25]
  PIN gpio_in[26]
    DIRECTION INPUT ;
    USE SIGNAL ;
    PORT
      LAYER met2 ;
        RECT 2994.400 4766.350 2994.680 4768.630 ;
    END
  END gpio_in[26]
  PIN gpio_in[27]
    DIRECTION INPUT ;
    USE SIGNAL ;
    PORT
      LAYER met2 ;
        RECT 2485.400 4766.350 2485.680 4768.630 ;
    END
  END gpio_in[27]
  PIN gpio_in[28]
    DIRECTION INPUT ;
    USE SIGNAL ;
    PORT
      LAYER met2 ;
        RECT 2228.400 4766.350 2228.680 4768.630 ;
    END
  END gpio_in[28]
  PIN gpio_in[29]
    DIRECTION INPUT ;
    USE SIGNAL ;
    PORT
      LAYER met2 ;
        RECT 1783.400 4766.350 1783.680 4768.630 ;
    END
  END gpio_in[29]
  PIN gpio_in[2]
    DIRECTION INPUT ;
    USE SIGNAL ;
    PORT
      LAYER met3 ;
        RECT 6754.330 744.920 6756.630 745.270 ;
    END
  END gpio_in[2]
  PIN gpio_in[30]
    DIRECTION INPUT ;
    USE SIGNAL ;
    PORT
      LAYER met2 ;
        RECT 1274.400 4766.350 1274.680 4768.630 ;
    END
  END gpio_in[30]
  PIN gpio_in[31]
    DIRECTION INPUT ;
    USE SIGNAL ;
    PORT
      LAYER met2 ;
        RECT 1016.400 4766.350 1016.680 4768.630 ;
    END
  END gpio_in[31]
  PIN gpio_in[32]
    DIRECTION INPUT ;
    USE SIGNAL ;
    PORT
      LAYER met2 ;
        RECT 759.400 4766.350 759.680 4768.630 ;
    END
  END gpio_in[32]
  PIN gpio_in[33]
    DIRECTION INPUT ;
    USE SIGNAL ;
    PORT
      LAYER met2 ;
        RECT 502.400 4766.350 502.680 4768.630 ;
    END
  END gpio_in[33]
  PIN gpio_in[34]
    DIRECTION INPUT ;
    USE SIGNAL ;
    PORT
      LAYER met2 ;
        RECT 245.400 4766.350 245.680 4768.630 ;
    END
  END gpio_in[34]
  PIN gpio_in[35]
    DIRECTION INPUT ;
    USE SIGNAL ;
    PORT
      LAYER met3 ;
        RECT -2.000 4635.360 0.300 4635.710 ;
    END
  END gpio_in[35]
  PIN gpio_in[36]
    DIRECTION INPUT ;
    USE SIGNAL ;
    PORT
      LAYER met3 ;
        RECT -2.000 3786.360 0.300 3786.710 ;
    END
  END gpio_in[36]
  PIN gpio_in[37]
    DIRECTION INPUT ;
    USE SIGNAL ;
    PORT
      LAYER met3 ;
        RECT -2.000 3570.360 0.300 3570.710 ;
    END
  END gpio_in[37]
  PIN gpio_in[38]
    DIRECTION INPUT ;
    USE SIGNAL ;
    PORT
      LAYER met3 ;
        RECT -2.000 3354.360 0.300 3354.710 ;
    END
  END gpio_in[38]
  PIN gpio_in[39]
    DIRECTION INPUT ;
    USE SIGNAL ;
    PORT
      LAYER met3 ;
        RECT -2.000 3138.360 0.300 3138.710 ;
    END
  END gpio_in[39]
  PIN gpio_in[3]
    DIRECTION INPUT ;
    USE SIGNAL ;
    PORT
      LAYER met3 ;
        RECT 6754.330 970.920 6756.630 971.270 ;
    END
  END gpio_in[3]
  PIN gpio_in[40]
    DIRECTION INPUT ;
    USE SIGNAL ;
    PORT
      LAYER met3 ;
        RECT -2.000 2922.360 0.300 2922.710 ;
    END
  END gpio_in[40]
  PIN gpio_in[41]
    DIRECTION INPUT ;
    USE SIGNAL ;
    PORT
      LAYER met3 ;
        RECT -2.000 2706.360 0.300 2706.710 ;
    END
  END gpio_in[41]
  PIN gpio_in[42]
    DIRECTION INPUT ;
    USE SIGNAL ;
    PORT
      LAYER met3 ;
        RECT -2.000 2490.360 0.300 2490.710 ;
    END
  END gpio_in[42]
  PIN gpio_in[43]
    DIRECTION INPUT ;
    USE SIGNAL ;
    PORT
      LAYER met3 ;
        RECT -2.000 1852.360 0.300 1852.710 ;
    END
  END gpio_in[43]
  PIN gpio_in[44]
    DIRECTION INPUT ;
    USE SIGNAL ;
    PORT
      LAYER met3 ;
        RECT -2.000 1636.360 0.300 1636.710 ;
    END
  END gpio_in[44]
  PIN gpio_in[45]
    DIRECTION INPUT ;
    USE SIGNAL ;
    PORT
      LAYER met3 ;
        RECT -2.000 1420.360 0.300 1420.710 ;
    END
  END gpio_in[45]
  PIN gpio_in[46]
    DIRECTION INPUT ;
    USE SIGNAL ;
    PORT
      LAYER met3 ;
        RECT -2.000 1204.360 0.300 1204.710 ;
    END
  END gpio_in[46]
  PIN gpio_in[47]
    DIRECTION INPUT ;
    USE SIGNAL ;
    PORT
      LAYER met3 ;
        RECT -2.000 988.360 0.300 988.710 ;
    END
  END gpio_in[47]
  PIN gpio_in[48]
    DIRECTION INPUT ;
    USE SIGNAL ;
    PORT
      LAYER met3 ;
        RECT -2.000 772.360 0.300 772.710 ;
    END
  END gpio_in[48]
  PIN gpio_in[49]
    DIRECTION INPUT ;
    USE SIGNAL ;
    PORT
      LAYER met2 ;
        RECT 725.950 -2.000 726.230 0.280 ;
    END
  END gpio_in[49]
  PIN gpio_in[4]
    DIRECTION INPUT ;
    USE SIGNAL ;
    PORT
      LAYER met3 ;
        RECT 6754.330 1195.920 6756.630 1196.270 ;
    END
  END gpio_in[4]
  PIN gpio_in[50]
    DIRECTION INPUT ;
    USE SIGNAL ;
    PORT
      LAYER met2 ;
        RECT 1268.950 -2.000 1269.230 0.280 ;
    END
  END gpio_in[50]
  PIN gpio_in[51]
    DIRECTION INPUT ;
    USE SIGNAL ;
    PORT
      LAYER met2 ;
        RECT 1542.950 -2.000 1543.230 0.280 ;
    END
  END gpio_in[51]
  PIN gpio_in[52]
    DIRECTION INPUT ;
    USE SIGNAL ;
    PORT
      LAYER met2 ;
        RECT 1816.950 -2.000 1817.230 0.280 ;
    END
  END gpio_in[52]
  PIN gpio_in[53]
    DIRECTION INPUT ;
    USE SIGNAL ;
    PORT
      LAYER met2 ;
        RECT 2090.950 -2.000 2091.230 0.280 ;
    END
  END gpio_in[53]
  PIN gpio_in[54]
    DIRECTION INPUT ;
    USE SIGNAL ;
    PORT
      LAYER met2 ;
        RECT 2364.950 -2.000 2365.230 0.280 ;
    END
  END gpio_in[54]
  PIN gpio_in[55]
    DIRECTION INPUT ;
    USE SIGNAL ;
    PORT
      LAYER met2 ;
        RECT 3179.430 -2.000 3179.710 0.280 ;
    END
  END gpio_in[55]
  PIN gpio_in[56]
    DIRECTION INPUT ;
    USE SIGNAL ;
    PORT
      LAYER met2 ;
        RECT 3453.430 -2.000 3453.710 0.280 ;
    END
  END gpio_in[56]
  PIN gpio_in[57]
    DIRECTION INPUT ;
    USE SIGNAL ;
    PORT
      LAYER met2 ;
        RECT 4313.950 -2.000 4314.230 0.280 ;
    END
  END gpio_in[57]
  PIN gpio_in[58]
    DIRECTION INPUT ;
    USE SIGNAL ;
    PORT
      LAYER met2 ;
        RECT 4856.950 -2.000 4857.230 0.280 ;
    END
  END gpio_in[58]
  PIN gpio_in[59]
    DIRECTION INPUT ;
    USE SIGNAL ;
    PORT
      LAYER met2 ;
        RECT 5130.950 -2.000 5131.230 0.280 ;
    END
  END gpio_in[59]
  PIN gpio_in[5]
    DIRECTION INPUT ;
    USE SIGNAL ;
    PORT
      LAYER met3 ;
        RECT 6754.330 1420.920 6756.630 1421.270 ;
    END
  END gpio_in[5]
  PIN gpio_in[60]
    DIRECTION INPUT ;
    USE SIGNAL ;
    PORT
      LAYER met2 ;
        RECT 5404.950 -2.000 5405.230 0.280 ;
    END
  END gpio_in[60]
  PIN gpio_in[61]
    DIRECTION INPUT ;
    USE SIGNAL ;
    PORT
      LAYER met2 ;
        RECT 5678.950 -2.000 5679.230 0.280 ;
    END
  END gpio_in[61]
  PIN gpio_in[62]
    DIRECTION INPUT ;
    USE SIGNAL ;
    PORT
      LAYER met2 ;
        RECT 5952.950 -2.000 5953.230 0.280 ;
    END
  END gpio_in[62]
  PIN gpio_in[6]
    DIRECTION INPUT ;
    USE SIGNAL ;
    PORT
      LAYER met3 ;
        RECT 6754.330 1646.920 6756.630 1647.270 ;
    END
  END gpio_in[6]
  PIN gpio_in[7]
    DIRECTION INPUT ;
    USE SIGNAL ;
    PORT
      LAYER met3 ;
        RECT 6754.330 2532.920 6756.630 2533.270 ;
    END
  END gpio_in[7]
  PIN gpio_in[8]
    DIRECTION INPUT ;
    USE SIGNAL ;
    PORT
      LAYER met3 ;
        RECT 6754.330 2758.920 6756.630 2759.270 ;
    END
  END gpio_in[8]
  PIN gpio_in[9]
    DIRECTION INPUT ;
    USE SIGNAL ;
    PORT
      LAYER met3 ;
        RECT 6754.330 2983.920 6756.630 2984.270 ;
    END
  END gpio_in[9]
  PIN gpio_in_h[0]
    DIRECTION INPUT ;
    USE SIGNAL ;
    PORT
      LAYER met3 ;
        RECT 6754.330 367.520 6756.630 367.870 ;
    END
  END gpio_in_h[0]
  PIN gpio_in_h[10]
    DIRECTION INPUT ;
    USE SIGNAL ;
    PORT
      LAYER met3 ;
        RECT 6754.330 3283.520 6756.630 3283.870 ;
    END
  END gpio_in_h[10]
  PIN gpio_in_h[11]
    DIRECTION INPUT ;
    USE SIGNAL ;
    PORT
      LAYER met3 ;
        RECT 6754.330 3508.520 6756.630 3508.870 ;
    END
  END gpio_in_h[11]
  PIN gpio_in_h[12]
    DIRECTION INPUT ;
    USE SIGNAL ;
    PORT
      LAYER met3 ;
        RECT 6754.330 3733.520 6756.630 3733.870 ;
    END
  END gpio_in_h[12]
  PIN gpio_in_h[13]
    DIRECTION INPUT ;
    USE SIGNAL ;
    PORT
      LAYER met3 ;
        RECT 6754.330 4179.520 6756.630 4179.870 ;
    END
  END gpio_in_h[13]
  PIN gpio_in_h[14]
    DIRECTION INPUT ;
    USE SIGNAL ;
    PORT
      LAYER met3 ;
        RECT 6754.330 4625.520 6756.630 4625.870 ;
    END
  END gpio_in_h[14]
  PIN gpio_in_h[15]
    DIRECTION INPUT ;
    USE SIGNAL ;
    PORT
      LAYER met2 ;
        RECT 6508.800 4766.350 6509.080 4768.630 ;
    END
  END gpio_in_h[15]
  PIN gpio_in_h[16]
    DIRECTION INPUT ;
    USE SIGNAL ;
    PORT
      LAYER met2 ;
        RECT 5999.800 4766.350 6000.080 4768.630 ;
    END
  END gpio_in_h[16]
  PIN gpio_in_h[17]
    DIRECTION INPUT ;
    USE SIGNAL ;
    PORT
      LAYER met2 ;
        RECT 5742.800 4766.350 5743.080 4768.630 ;
    END
  END gpio_in_h[17]
  PIN gpio_in_h[18]
    DIRECTION INPUT ;
    USE SIGNAL ;
    PORT
      LAYER met2 ;
        RECT 5297.800 4766.350 5298.080 4768.630 ;
    END
  END gpio_in_h[18]
  PIN gpio_in_h[19]
    DIRECTION INPUT ;
    USE SIGNAL ;
    PORT
      LAYER met2 ;
        RECT 4788.800 4766.350 4789.080 4768.630 ;
    END
  END gpio_in_h[19]
  PIN gpio_in_h[1]
    DIRECTION INPUT ;
    USE SIGNAL ;
    PORT
      LAYER met3 ;
        RECT 6754.330 593.520 6756.630 593.870 ;
    END
  END gpio_in_h[1]
  PIN gpio_in_h[20]
    DIRECTION INPUT ;
    USE SIGNAL ;
    PORT
      LAYER met2 ;
        RECT 4530.800 4766.350 4531.080 4768.630 ;
    END
  END gpio_in_h[20]
  PIN gpio_in_h[21]
    DIRECTION INPUT ;
    USE SIGNAL ;
    PORT
      LAYER met2 ;
        RECT 4273.800 4766.350 4274.080 4768.630 ;
    END
  END gpio_in_h[21]
  PIN gpio_in_h[22]
    DIRECTION INPUT ;
    USE SIGNAL ;
    PORT
      LAYER met2 ;
        RECT 4016.800 4766.350 4017.080 4768.630 ;
    END
  END gpio_in_h[22]
  PIN gpio_in_h[23]
    DIRECTION INPUT ;
    USE SIGNAL ;
    PORT
      LAYER met2 ;
        RECT 3759.800 4766.350 3760.080 4768.630 ;
    END
  END gpio_in_h[23]
  PIN gpio_in_h[24]
    DIRECTION INPUT ;
    USE SIGNAL ;
    PORT
      LAYER met2 ;
        RECT 3434.800 4766.350 3435.080 4768.630 ;
    END
  END gpio_in_h[24]
  PIN gpio_in_h[25]
    DIRECTION INPUT ;
    USE SIGNAL ;
    PORT
      LAYER met2 ;
        RECT 3177.800 4766.350 3178.080 4768.630 ;
    END
  END gpio_in_h[25]
  PIN gpio_in_h[26]
    DIRECTION INPUT ;
    USE SIGNAL ;
    PORT
      LAYER met2 ;
        RECT 2920.800 4766.350 2921.080 4768.630 ;
    END
  END gpio_in_h[26]
  PIN gpio_in_h[27]
    DIRECTION INPUT ;
    USE SIGNAL ;
    PORT
      LAYER met2 ;
        RECT 2411.800 4766.350 2412.080 4768.630 ;
    END
  END gpio_in_h[27]
  PIN gpio_in_h[28]
    DIRECTION INPUT ;
    USE SIGNAL ;
    PORT
      LAYER met2 ;
        RECT 2154.800 4766.350 2155.080 4768.630 ;
    END
  END gpio_in_h[28]
  PIN gpio_in_h[29]
    DIRECTION INPUT ;
    USE SIGNAL ;
    PORT
      LAYER met2 ;
        RECT 1709.800 4766.350 1710.080 4768.630 ;
    END
  END gpio_in_h[29]
  PIN gpio_in_h[2]
    DIRECTION INPUT ;
    USE SIGNAL ;
    PORT
      LAYER met3 ;
        RECT 6754.330 818.520 6756.630 818.870 ;
    END
  END gpio_in_h[2]
  PIN gpio_in_h[30]
    DIRECTION INPUT ;
    USE SIGNAL ;
    PORT
      LAYER met2 ;
        RECT 1200.800 4766.350 1201.080 4768.630 ;
    END
  END gpio_in_h[30]
  PIN gpio_in_h[31]
    DIRECTION INPUT ;
    USE SIGNAL ;
    PORT
      LAYER met2 ;
        RECT 942.800 4766.350 943.080 4768.630 ;
    END
  END gpio_in_h[31]
  PIN gpio_in_h[32]
    DIRECTION INPUT ;
    USE SIGNAL ;
    PORT
      LAYER met2 ;
        RECT 685.800 4766.350 686.080 4768.630 ;
    END
  END gpio_in_h[32]
  PIN gpio_in_h[33]
    DIRECTION INPUT ;
    USE SIGNAL ;
    PORT
      LAYER met2 ;
        RECT 428.800 4766.350 429.080 4768.630 ;
    END
  END gpio_in_h[33]
  PIN gpio_in_h[34]
    DIRECTION INPUT ;
    USE SIGNAL ;
    PORT
      LAYER met2 ;
        RECT 171.800 4766.350 172.080 4768.630 ;
    END
  END gpio_in_h[34]
  PIN gpio_in_h[35]
    DIRECTION INPUT ;
    USE SIGNAL ;
    PORT
      LAYER met3 ;
        RECT -2.000 4561.760 0.300 4562.110 ;
    END
  END gpio_in_h[35]
  PIN gpio_in_h[36]
    DIRECTION INPUT ;
    USE SIGNAL ;
    PORT
      LAYER met3 ;
        RECT -2.000 3712.760 0.300 3713.110 ;
    END
  END gpio_in_h[36]
  PIN gpio_in_h[37]
    DIRECTION INPUT ;
    USE SIGNAL ;
    PORT
      LAYER met3 ;
        RECT -2.000 3496.760 0.300 3497.110 ;
    END
  END gpio_in_h[37]
  PIN gpio_in_h[38]
    DIRECTION INPUT ;
    USE SIGNAL ;
    PORT
      LAYER met3 ;
        RECT -2.000 3280.760 0.300 3281.110 ;
    END
  END gpio_in_h[38]
  PIN gpio_in_h[39]
    DIRECTION INPUT ;
    USE SIGNAL ;
    PORT
      LAYER met3 ;
        RECT -2.000 3064.760 0.300 3065.110 ;
    END
  END gpio_in_h[39]
  PIN gpio_in_h[3]
    DIRECTION INPUT ;
    USE SIGNAL ;
    PORT
      LAYER met3 ;
        RECT 6754.330 1044.520 6756.630 1044.870 ;
    END
  END gpio_in_h[3]
  PIN gpio_in_h[40]
    DIRECTION INPUT ;
    USE SIGNAL ;
    PORT
      LAYER met3 ;
        RECT -2.000 2848.760 0.300 2849.110 ;
    END
  END gpio_in_h[40]
  PIN gpio_in_h[41]
    DIRECTION INPUT ;
    USE SIGNAL ;
    PORT
      LAYER met3 ;
        RECT -2.000 2632.760 0.300 2633.110 ;
    END
  END gpio_in_h[41]
  PIN gpio_in_h[42]
    DIRECTION INPUT ;
    USE SIGNAL ;
    PORT
      LAYER met3 ;
        RECT -2.000 2416.760 0.300 2417.110 ;
    END
  END gpio_in_h[42]
  PIN gpio_in_h[43]
    DIRECTION INPUT ;
    USE SIGNAL ;
    PORT
      LAYER met3 ;
        RECT -2.000 1778.760 0.300 1779.110 ;
    END
  END gpio_in_h[43]
  PIN gpio_in_h[44]
    DIRECTION INPUT ;
    USE SIGNAL ;
    PORT
      LAYER met3 ;
        RECT -2.000 1562.760 0.300 1563.110 ;
    END
  END gpio_in_h[44]
  PIN gpio_in_h[45]
    DIRECTION INPUT ;
    USE SIGNAL ;
    PORT
      LAYER met3 ;
        RECT -2.000 1346.760 0.300 1347.110 ;
    END
  END gpio_in_h[45]
  PIN gpio_in_h[46]
    DIRECTION INPUT ;
    USE SIGNAL ;
    PORT
      LAYER met3 ;
        RECT -2.000 1130.760 0.300 1131.110 ;
    END
  END gpio_in_h[46]
  PIN gpio_in_h[47]
    DIRECTION INPUT ;
    USE SIGNAL ;
    PORT
      LAYER met3 ;
        RECT -2.000 914.760 0.300 915.110 ;
    END
  END gpio_in_h[47]
  PIN gpio_in_h[48]
    DIRECTION INPUT ;
    USE SIGNAL ;
    PORT
      LAYER met3 ;
        RECT -2.000 698.760 0.300 699.110 ;
    END
  END gpio_in_h[48]
  PIN gpio_in_h[49]
    DIRECTION INPUT ;
    USE SIGNAL ;
    PORT
      LAYER met2 ;
        RECT 799.550 -2.000 799.830 0.280 ;
    END
  END gpio_in_h[49]
  PIN gpio_in_h[4]
    DIRECTION INPUT ;
    USE SIGNAL ;
    PORT
      LAYER met3 ;
        RECT 6754.330 1269.520 6756.630 1269.870 ;
    END
  END gpio_in_h[4]
  PIN gpio_in_h[50]
    DIRECTION INPUT ;
    USE SIGNAL ;
    PORT
      LAYER met2 ;
        RECT 1342.550 -2.000 1342.830 0.280 ;
    END
  END gpio_in_h[50]
  PIN gpio_in_h[51]
    DIRECTION INPUT ;
    USE SIGNAL ;
    PORT
      LAYER met2 ;
        RECT 1616.550 -2.000 1616.830 0.280 ;
    END
  END gpio_in_h[51]
  PIN gpio_in_h[52]
    DIRECTION INPUT ;
    USE SIGNAL ;
    PORT
      LAYER met2 ;
        RECT 1890.550 -2.000 1890.830 0.280 ;
    END
  END gpio_in_h[52]
  PIN gpio_in_h[53]
    DIRECTION INPUT ;
    USE SIGNAL ;
    PORT
      LAYER met2 ;
        RECT 2164.550 -2.000 2164.830 0.280 ;
    END
  END gpio_in_h[53]
  PIN gpio_in_h[54]
    DIRECTION INPUT ;
    USE SIGNAL ;
    PORT
      LAYER met2 ;
        RECT 2438.550 -2.000 2438.830 0.280 ;
    END
  END gpio_in_h[54]
  PIN gpio_in_h[55]
    DIRECTION INPUT ;
    USE SIGNAL ;
    PORT
      LAYER met2 ;
        RECT 3253.030 -2.000 3253.310 0.280 ;
    END
  END gpio_in_h[55]
  PIN gpio_in_h[56]
    DIRECTION INPUT ;
    USE SIGNAL ;
    PORT
      LAYER met2 ;
        RECT 3527.030 -2.000 3527.310 0.280 ;
    END
  END gpio_in_h[56]
  PIN gpio_in_h[57]
    DIRECTION INPUT ;
    USE SIGNAL ;
    PORT
      LAYER met2 ;
        RECT 4387.550 -2.000 4387.830 0.280 ;
    END
  END gpio_in_h[57]
  PIN gpio_in_h[58]
    DIRECTION INPUT ;
    USE SIGNAL ;
    PORT
      LAYER met2 ;
        RECT 4930.550 -2.000 4930.830 0.280 ;
    END
  END gpio_in_h[58]
  PIN gpio_in_h[59]
    DIRECTION INPUT ;
    USE SIGNAL ;
    PORT
      LAYER met2 ;
        RECT 5204.550 -2.000 5204.830 0.280 ;
    END
  END gpio_in_h[59]
  PIN gpio_in_h[5]
    DIRECTION INPUT ;
    USE SIGNAL ;
    PORT
      LAYER met3 ;
        RECT 6754.330 1494.520 6756.630 1494.870 ;
    END
  END gpio_in_h[5]
  PIN gpio_in_h[60]
    DIRECTION INPUT ;
    USE SIGNAL ;
    PORT
      LAYER met2 ;
        RECT 5478.550 -2.000 5478.830 0.280 ;
    END
  END gpio_in_h[60]
  PIN gpio_in_h[61]
    DIRECTION INPUT ;
    USE SIGNAL ;
    PORT
      LAYER met2 ;
        RECT 5752.550 -2.000 5752.830 0.280 ;
    END
  END gpio_in_h[61]
  PIN gpio_in_h[62]
    DIRECTION INPUT ;
    USE SIGNAL ;
    PORT
      LAYER met2 ;
        RECT 6026.550 -2.000 6026.830 0.280 ;
    END
  END gpio_in_h[62]
  PIN gpio_in_h[6]
    DIRECTION INPUT ;
    USE SIGNAL ;
    PORT
      LAYER met3 ;
        RECT 6754.330 1720.520 6756.630 1720.870 ;
    END
  END gpio_in_h[6]
  PIN gpio_in_h[7]
    DIRECTION INPUT ;
    USE SIGNAL ;
    PORT
      LAYER met3 ;
        RECT 6754.330 2606.520 6756.630 2606.870 ;
    END
  END gpio_in_h[7]
  PIN gpio_in_h[8]
    DIRECTION INPUT ;
    USE SIGNAL ;
    PORT
      LAYER met3 ;
        RECT 6754.330 2832.520 6756.630 2832.870 ;
    END
  END gpio_in_h[8]
  PIN gpio_in_h[9]
    DIRECTION INPUT ;
    USE SIGNAL ;
    PORT
      LAYER met3 ;
        RECT 6754.330 3057.520 6756.630 3057.870 ;
    END
  END gpio_in_h[9]
  PIN gpio_inp_dis[0]
    DIRECTION OUTPUT ;
    USE SIGNAL ;
    PORT
      LAYER met3 ;
        RECT 6754.330 327.500 6756.630 327.850 ;
    END
  END gpio_inp_dis[0]
  PIN gpio_inp_dis[10]
    DIRECTION OUTPUT ;
    USE SIGNAL ;
    PORT
      LAYER met3 ;
        RECT 6754.330 3243.500 6756.630 3243.850 ;
    END
  END gpio_inp_dis[10]
  PIN gpio_inp_dis[11]
    DIRECTION OUTPUT ;
    USE SIGNAL ;
    PORT
      LAYER met3 ;
        RECT 6754.330 3468.500 6756.630 3468.850 ;
    END
  END gpio_inp_dis[11]
  PIN gpio_inp_dis[12]
    DIRECTION OUTPUT ;
    USE SIGNAL ;
    PORT
      LAYER met3 ;
        RECT 6754.330 3693.500 6756.630 3693.850 ;
    END
  END gpio_inp_dis[12]
  PIN gpio_inp_dis[13]
    DIRECTION OUTPUT ;
    USE SIGNAL ;
    PORT
      LAYER met3 ;
        RECT 6754.330 4139.500 6756.630 4139.850 ;
    END
  END gpio_inp_dis[13]
  PIN gpio_inp_dis[14]
    DIRECTION OUTPUT ;
    USE SIGNAL ;
    PORT
      LAYER met3 ;
        RECT 6754.330 4585.500 6756.630 4585.850 ;
    END
  END gpio_inp_dis[14]
  PIN gpio_inp_dis[15]
    DIRECTION OUTPUT ;
    USE SIGNAL ;
    PORT
      LAYER met2 ;
        RECT 6548.820 4766.350 6549.100 4768.630 ;
    END
  END gpio_inp_dis[15]
  PIN gpio_inp_dis[16]
    DIRECTION OUTPUT ;
    USE SIGNAL ;
    PORT
      LAYER met2 ;
        RECT 6039.820 4766.350 6040.100 4768.630 ;
    END
  END gpio_inp_dis[16]
  PIN gpio_inp_dis[17]
    DIRECTION OUTPUT ;
    USE SIGNAL ;
    PORT
      LAYER met2 ;
        RECT 5782.820 4766.350 5783.100 4768.630 ;
    END
  END gpio_inp_dis[17]
  PIN gpio_inp_dis[18]
    DIRECTION OUTPUT ;
    USE SIGNAL ;
    PORT
      LAYER met2 ;
        RECT 5337.820 4766.350 5338.100 4768.630 ;
    END
  END gpio_inp_dis[18]
  PIN gpio_inp_dis[19]
    DIRECTION OUTPUT ;
    USE SIGNAL ;
    PORT
      LAYER met2 ;
        RECT 4828.820 4766.350 4829.100 4768.630 ;
    END
  END gpio_inp_dis[19]
  PIN gpio_inp_dis[1]
    DIRECTION OUTPUT ;
    USE SIGNAL ;
    PORT
      LAYER met3 ;
        RECT 6754.330 553.500 6756.630 553.850 ;
    END
  END gpio_inp_dis[1]
  PIN gpio_inp_dis[20]
    DIRECTION OUTPUT ;
    USE SIGNAL ;
    PORT
      LAYER met2 ;
        RECT 4570.820 4766.350 4571.100 4768.630 ;
    END
  END gpio_inp_dis[20]
  PIN gpio_inp_dis[21]
    DIRECTION OUTPUT ;
    USE SIGNAL ;
    PORT
      LAYER met2 ;
        RECT 4313.820 4766.350 4314.100 4768.630 ;
    END
  END gpio_inp_dis[21]
  PIN gpio_inp_dis[22]
    DIRECTION OUTPUT ;
    USE SIGNAL ;
    PORT
      LAYER met2 ;
        RECT 4056.820 4766.350 4057.100 4768.630 ;
    END
  END gpio_inp_dis[22]
  PIN gpio_inp_dis[23]
    DIRECTION OUTPUT ;
    USE SIGNAL ;
    PORT
      LAYER met2 ;
        RECT 3799.820 4766.350 3800.100 4768.630 ;
    END
  END gpio_inp_dis[23]
  PIN gpio_inp_dis[24]
    DIRECTION OUTPUT ;
    USE SIGNAL ;
    PORT
      LAYER met2 ;
        RECT 3474.820 4766.350 3475.100 4768.630 ;
    END
  END gpio_inp_dis[24]
  PIN gpio_inp_dis[25]
    DIRECTION OUTPUT ;
    USE SIGNAL ;
    PORT
      LAYER met2 ;
        RECT 3217.820 4766.350 3218.100 4768.630 ;
    END
  END gpio_inp_dis[25]
  PIN gpio_inp_dis[26]
    DIRECTION OUTPUT ;
    USE SIGNAL ;
    PORT
      LAYER met2 ;
        RECT 2960.820 4766.350 2961.100 4768.630 ;
    END
  END gpio_inp_dis[26]
  PIN gpio_inp_dis[27]
    DIRECTION OUTPUT ;
    USE SIGNAL ;
    PORT
      LAYER met2 ;
        RECT 2451.820 4766.350 2452.100 4768.630 ;
    END
  END gpio_inp_dis[27]
  PIN gpio_inp_dis[28]
    DIRECTION OUTPUT ;
    USE SIGNAL ;
    PORT
      LAYER met2 ;
        RECT 2194.820 4766.350 2195.100 4768.630 ;
    END
  END gpio_inp_dis[28]
  PIN gpio_inp_dis[29]
    DIRECTION OUTPUT ;
    USE SIGNAL ;
    PORT
      LAYER met2 ;
        RECT 1749.820 4766.350 1750.100 4768.630 ;
    END
  END gpio_inp_dis[29]
  PIN gpio_inp_dis[2]
    DIRECTION OUTPUT ;
    USE SIGNAL ;
    PORT
      LAYER met3 ;
        RECT 6754.330 778.500 6756.630 778.850 ;
    END
  END gpio_inp_dis[2]
  PIN gpio_inp_dis[30]
    DIRECTION OUTPUT ;
    USE SIGNAL ;
    PORT
      LAYER met2 ;
        RECT 1240.820 4766.350 1241.100 4768.630 ;
    END
  END gpio_inp_dis[30]
  PIN gpio_inp_dis[31]
    DIRECTION OUTPUT ;
    USE SIGNAL ;
    PORT
      LAYER met2 ;
        RECT 982.820 4766.350 983.100 4768.630 ;
    END
  END gpio_inp_dis[31]
  PIN gpio_inp_dis[32]
    DIRECTION OUTPUT ;
    USE SIGNAL ;
    PORT
      LAYER met2 ;
        RECT 725.820 4766.350 726.100 4768.630 ;
    END
  END gpio_inp_dis[32]
  PIN gpio_inp_dis[33]
    DIRECTION OUTPUT ;
    USE SIGNAL ;
    PORT
      LAYER met2 ;
        RECT 468.820 4766.350 469.100 4768.630 ;
    END
  END gpio_inp_dis[33]
  PIN gpio_inp_dis[34]
    DIRECTION OUTPUT ;
    USE SIGNAL ;
    PORT
      LAYER met2 ;
        RECT 211.820 4766.350 212.100 4768.630 ;
    END
  END gpio_inp_dis[34]
  PIN gpio_inp_dis[35]
    DIRECTION OUTPUT ;
    USE SIGNAL ;
    PORT
      LAYER met3 ;
        RECT -2.000 4601.780 0.300 4602.130 ;
    END
  END gpio_inp_dis[35]
  PIN gpio_inp_dis[36]
    DIRECTION OUTPUT ;
    USE SIGNAL ;
    PORT
      LAYER met3 ;
        RECT -2.000 3752.780 0.300 3753.130 ;
    END
  END gpio_inp_dis[36]
  PIN gpio_inp_dis[37]
    DIRECTION OUTPUT ;
    USE SIGNAL ;
    PORT
      LAYER met3 ;
        RECT -2.000 3536.780 0.300 3537.130 ;
    END
  END gpio_inp_dis[37]
  PIN gpio_inp_dis[38]
    DIRECTION OUTPUT ;
    USE SIGNAL ;
    PORT
      LAYER met3 ;
        RECT -2.000 3320.780 0.300 3321.130 ;
    END
  END gpio_inp_dis[38]
  PIN gpio_inp_dis[39]
    DIRECTION OUTPUT ;
    USE SIGNAL ;
    PORT
      LAYER met3 ;
        RECT -2.000 3104.780 0.300 3105.130 ;
    END
  END gpio_inp_dis[39]
  PIN gpio_inp_dis[3]
    DIRECTION OUTPUT ;
    USE SIGNAL ;
    PORT
      LAYER met3 ;
        RECT 6754.330 1004.500 6756.630 1004.850 ;
    END
  END gpio_inp_dis[3]
  PIN gpio_inp_dis[40]
    DIRECTION OUTPUT ;
    USE SIGNAL ;
    PORT
      LAYER met3 ;
        RECT -2.000 2888.780 0.300 2889.130 ;
    END
  END gpio_inp_dis[40]
  PIN gpio_inp_dis[41]
    DIRECTION OUTPUT ;
    USE SIGNAL ;
    PORT
      LAYER met3 ;
        RECT -2.000 2672.780 0.300 2673.130 ;
    END
  END gpio_inp_dis[41]
  PIN gpio_inp_dis[42]
    DIRECTION OUTPUT ;
    USE SIGNAL ;
    PORT
      LAYER met3 ;
        RECT -2.000 2456.780 0.300 2457.130 ;
    END
  END gpio_inp_dis[42]
  PIN gpio_inp_dis[43]
    DIRECTION OUTPUT ;
    USE SIGNAL ;
    PORT
      LAYER met3 ;
        RECT -2.000 1818.780 0.300 1819.130 ;
    END
  END gpio_inp_dis[43]
  PIN gpio_inp_dis[44]
    DIRECTION OUTPUT ;
    USE SIGNAL ;
    PORT
      LAYER met3 ;
        RECT -2.000 1602.780 0.300 1603.130 ;
    END
  END gpio_inp_dis[44]
  PIN gpio_inp_dis[45]
    DIRECTION OUTPUT ;
    USE SIGNAL ;
    PORT
      LAYER met3 ;
        RECT -2.000 1386.780 0.300 1387.130 ;
    END
  END gpio_inp_dis[45]
  PIN gpio_inp_dis[46]
    DIRECTION OUTPUT ;
    USE SIGNAL ;
    PORT
      LAYER met3 ;
        RECT -2.000 1170.780 0.300 1171.130 ;
    END
  END gpio_inp_dis[46]
  PIN gpio_inp_dis[47]
    DIRECTION OUTPUT ;
    USE SIGNAL ;
    PORT
      LAYER met3 ;
        RECT -2.000 954.780 0.300 955.130 ;
    END
  END gpio_inp_dis[47]
  PIN gpio_inp_dis[48]
    DIRECTION OUTPUT ;
    USE SIGNAL ;
    PORT
      LAYER met3 ;
        RECT -2.000 738.780 0.300 739.130 ;
    END
  END gpio_inp_dis[48]
  PIN gpio_inp_dis[49]
    DIRECTION OUTPUT ;
    USE SIGNAL ;
    PORT
      LAYER met2 ;
        RECT 759.530 -2.000 759.810 0.280 ;
    END
  END gpio_inp_dis[49]
  PIN gpio_inp_dis[4]
    DIRECTION OUTPUT ;
    USE SIGNAL ;
    PORT
      LAYER met3 ;
        RECT 6754.330 1229.500 6756.630 1229.850 ;
    END
  END gpio_inp_dis[4]
  PIN gpio_inp_dis[50]
    DIRECTION OUTPUT ;
    USE SIGNAL ;
    PORT
      LAYER met2 ;
        RECT 1302.530 -2.000 1302.810 0.280 ;
    END
  END gpio_inp_dis[50]
  PIN gpio_inp_dis[51]
    DIRECTION OUTPUT ;
    USE SIGNAL ;
    PORT
      LAYER met2 ;
        RECT 1576.530 -2.000 1576.810 0.280 ;
    END
  END gpio_inp_dis[51]
  PIN gpio_inp_dis[52]
    DIRECTION OUTPUT ;
    USE SIGNAL ;
    PORT
      LAYER met2 ;
        RECT 1850.530 -2.000 1850.810 0.280 ;
    END
  END gpio_inp_dis[52]
  PIN gpio_inp_dis[53]
    DIRECTION OUTPUT ;
    USE SIGNAL ;
    PORT
      LAYER met2 ;
        RECT 2124.530 -2.000 2124.810 0.280 ;
    END
  END gpio_inp_dis[53]
  PIN gpio_inp_dis[54]
    DIRECTION OUTPUT ;
    USE SIGNAL ;
    PORT
      LAYER met2 ;
        RECT 2398.530 -2.000 2398.810 0.280 ;
    END
  END gpio_inp_dis[54]
  PIN gpio_inp_dis[55]
    DIRECTION OUTPUT ;
    USE SIGNAL ;
    PORT
      LAYER met2 ;
        RECT 3213.010 -2.000 3213.290 0.280 ;
    END
  END gpio_inp_dis[55]
  PIN gpio_inp_dis[56]
    DIRECTION OUTPUT ;
    USE SIGNAL ;
    PORT
      LAYER met2 ;
        RECT 3487.010 -2.000 3487.290 0.280 ;
    END
  END gpio_inp_dis[56]
  PIN gpio_inp_dis[57]
    DIRECTION OUTPUT ;
    USE SIGNAL ;
    PORT
      LAYER met2 ;
        RECT 4347.530 -2.000 4347.810 0.280 ;
    END
  END gpio_inp_dis[57]
  PIN gpio_inp_dis[58]
    DIRECTION OUTPUT ;
    USE SIGNAL ;
    PORT
      LAYER met2 ;
        RECT 4890.530 -2.000 4890.810 0.280 ;
    END
  END gpio_inp_dis[58]
  PIN gpio_inp_dis[59]
    DIRECTION OUTPUT ;
    USE SIGNAL ;
    PORT
      LAYER met2 ;
        RECT 5164.530 -2.000 5164.810 0.280 ;
    END
  END gpio_inp_dis[59]
  PIN gpio_inp_dis[5]
    DIRECTION OUTPUT ;
    USE SIGNAL ;
    PORT
      LAYER met3 ;
        RECT 6754.330 1454.500 6756.630 1454.850 ;
    END
  END gpio_inp_dis[5]
  PIN gpio_inp_dis[60]
    DIRECTION OUTPUT ;
    USE SIGNAL ;
    PORT
      LAYER met2 ;
        RECT 5438.530 -2.000 5438.810 0.280 ;
    END
  END gpio_inp_dis[60]
  PIN gpio_inp_dis[61]
    DIRECTION OUTPUT ;
    USE SIGNAL ;
    PORT
      LAYER met2 ;
        RECT 5712.530 -2.000 5712.810 0.280 ;
    END
  END gpio_inp_dis[61]
  PIN gpio_inp_dis[62]
    DIRECTION OUTPUT ;
    USE SIGNAL ;
    PORT
      LAYER met2 ;
        RECT 5986.530 -2.000 5986.810 0.280 ;
    END
  END gpio_inp_dis[62]
  PIN gpio_inp_dis[6]
    DIRECTION OUTPUT ;
    USE SIGNAL ;
    PORT
      LAYER met3 ;
        RECT 6754.330 1680.500 6756.630 1680.850 ;
    END
  END gpio_inp_dis[6]
  PIN gpio_inp_dis[7]
    DIRECTION OUTPUT ;
    USE SIGNAL ;
    PORT
      LAYER met3 ;
        RECT 6754.330 2566.500 6756.630 2566.850 ;
    END
  END gpio_inp_dis[7]
  PIN gpio_inp_dis[8]
    DIRECTION OUTPUT ;
    USE SIGNAL ;
    PORT
      LAYER met3 ;
        RECT 6754.330 2792.500 6756.630 2792.850 ;
    END
  END gpio_inp_dis[8]
  PIN gpio_inp_dis[9]
    DIRECTION OUTPUT ;
    USE SIGNAL ;
    PORT
      LAYER met3 ;
        RECT 6754.330 3017.500 6756.630 3017.850 ;
    END
  END gpio_inp_dis[9]
  PIN gpio_loopback_one[0]
    DIRECTION INPUT ;
    USE SIGNAL ;
    PORT
      LAYER met3 ;
        RECT 6754.330 380.025 6756.630 380.335 ;
    END
  END gpio_loopback_one[0]
  PIN gpio_loopback_one[10]
    DIRECTION INPUT ;
    USE SIGNAL ;
    PORT
      LAYER met3 ;
        RECT 6754.330 3290.030 6756.630 3290.340 ;
    END
  END gpio_loopback_one[10]
  PIN gpio_loopback_one[11]
    DIRECTION INPUT ;
    USE SIGNAL ;
    PORT
      LAYER met3 ;
        RECT 6754.330 3515.030 6756.630 3515.340 ;
    END
  END gpio_loopback_one[11]
  PIN gpio_loopback_one[12]
    DIRECTION INPUT ;
    USE SIGNAL ;
    PORT
      LAYER met3 ;
        RECT 6754.330 3740.030 6756.630 3740.340 ;
    END
  END gpio_loopback_one[12]
  PIN gpio_loopback_one[13]
    DIRECTION INPUT ;
    USE SIGNAL ;
    PORT
      LAYER met3 ;
        RECT 6754.330 4185.030 6756.630 4185.340 ;
    END
  END gpio_loopback_one[13]
  PIN gpio_loopback_one[14]
    DIRECTION INPUT ;
    USE SIGNAL ;
    PORT
      LAYER met3 ;
        RECT 6754.330 4635.030 6756.630 4635.340 ;
    END
  END gpio_loopback_one[14]
  PIN gpio_loopback_one[15]
    DIRECTION INPUT ;
    USE SIGNAL ;
    PORT
      LAYER met2 ;
        RECT 6479.490 4766.350 6479.790 4768.630 ;
    END
  END gpio_loopback_one[15]
  PIN gpio_loopback_one[16]
    DIRECTION INPUT ;
    USE SIGNAL ;
    PORT
      LAYER met2 ;
        RECT 5982.490 4766.350 5982.790 4768.630 ;
    END
  END gpio_loopback_one[16]
  PIN gpio_loopback_one[17]
    DIRECTION INPUT ;
    USE SIGNAL ;
    PORT
      LAYER met2 ;
        RECT 5726.490 4766.350 5726.790 4768.630 ;
    END
  END gpio_loopback_one[17]
  PIN gpio_loopback_one[18]
    DIRECTION INPUT ;
    USE SIGNAL ;
    PORT
      LAYER met2 ;
        RECT 5281.490 4766.350 5281.790 4768.630 ;
    END
  END gpio_loopback_one[18]
  PIN gpio_loopback_one[19]
    DIRECTION INPUT ;
    USE SIGNAL ;
    PORT
      LAYER met2 ;
        RECT 4759.490 4766.350 4759.790 4768.630 ;
    END
  END gpio_loopback_one[19]
  PIN gpio_loopback_one[1]
    DIRECTION INPUT ;
    USE SIGNAL ;
    PORT
      LAYER met3 ;
        RECT 6754.330 605.025 6756.630 605.335 ;
    END
  END gpio_loopback_one[1]
  PIN gpio_loopback_one[20]
    DIRECTION INPUT ;
    USE SIGNAL ;
    PORT
      LAYER met2 ;
        RECT 4503.490 4766.350 4503.790 4768.630 ;
    END
  END gpio_loopback_one[20]
  PIN gpio_loopback_one[21]
    DIRECTION INPUT ;
    USE SIGNAL ;
    PORT
      LAYER met2 ;
        RECT 4247.490 4766.350 4247.790 4768.630 ;
    END
  END gpio_loopback_one[21]
  PIN gpio_loopback_one[22]
    DIRECTION INPUT ;
    USE SIGNAL ;
    PORT
      LAYER met2 ;
        RECT 3991.490 4766.350 3991.790 4768.630 ;
    END
  END gpio_loopback_one[22]
  PIN gpio_loopback_one[23]
    DIRECTION INPUT ;
    USE SIGNAL ;
    PORT
      LAYER met2 ;
        RECT 3735.490 4766.350 3735.790 4768.630 ;
    END
  END gpio_loopback_one[23]
  PIN gpio_loopback_one[24]
    DIRECTION INPUT ;
    USE SIGNAL ;
    PORT
      LAYER met2 ;
        RECT 3410.490 4766.350 3410.790 4768.630 ;
    END
  END gpio_loopback_one[24]
  PIN gpio_loopback_one[25]
    DIRECTION INPUT ;
    USE SIGNAL ;
    PORT
      LAYER met2 ;
        RECT 3153.490 4766.350 3153.790 4768.630 ;
    END
  END gpio_loopback_one[25]
  PIN gpio_loopback_one[26]
    DIRECTION INPUT ;
    USE SIGNAL ;
    PORT
      LAYER met2 ;
        RECT 2891.490 4766.350 2891.790 4768.630 ;
    END
  END gpio_loopback_one[26]
  PIN gpio_loopback_one[27]
    DIRECTION INPUT ;
    USE SIGNAL ;
    PORT
      LAYER met2 ;
        RECT 2394.490 4766.350 2394.790 4768.630 ;
    END
  END gpio_loopback_one[27]
  PIN gpio_loopback_one[28]
    DIRECTION INPUT ;
    USE SIGNAL ;
    PORT
      LAYER met2 ;
        RECT 2138.490 4766.350 2138.790 4768.630 ;
    END
  END gpio_loopback_one[28]
  PIN gpio_loopback_one[29]
    DIRECTION INPUT ;
    USE SIGNAL ;
    PORT
      LAYER met2 ;
        RECT 1693.490 4766.350 1693.790 4768.630 ;
    END
  END gpio_loopback_one[29]
  PIN gpio_loopback_one[2]
    DIRECTION INPUT ;
    USE SIGNAL ;
    PORT
      LAYER met3 ;
        RECT 6754.330 830.025 6756.630 830.335 ;
    END
  END gpio_loopback_one[2]
  PIN gpio_loopback_one[30]
    DIRECTION INPUT ;
    USE SIGNAL ;
    PORT
      LAYER met2 ;
        RECT 1171.490 4766.350 1171.790 4768.630 ;
    END
  END gpio_loopback_one[30]
  PIN gpio_loopback_one[31]
    DIRECTION INPUT ;
    USE SIGNAL ;
    PORT
      LAYER met2 ;
        RECT 915.490 4766.350 915.790 4768.630 ;
    END
  END gpio_loopback_one[31]
  PIN gpio_loopback_one[32]
    DIRECTION INPUT ;
    USE SIGNAL ;
    PORT
      LAYER met2 ;
        RECT 659.490 4766.350 659.790 4768.630 ;
    END
  END gpio_loopback_one[32]
  PIN gpio_loopback_one[33]
    DIRECTION INPUT ;
    USE SIGNAL ;
    PORT
      LAYER met2 ;
        RECT 403.490 4766.350 403.790 4768.630 ;
    END
  END gpio_loopback_one[33]
  PIN gpio_loopback_one[34]
    DIRECTION INPUT ;
    USE SIGNAL ;
    PORT
      LAYER met2 ;
        RECT 147.490 4766.350 147.790 4768.630 ;
    END
  END gpio_loopback_one[34]
  PIN gpio_loopback_one[35]
    DIRECTION INPUT ;
    USE SIGNAL ;
    PORT
      LAYER met3 ;
        RECT -2.000 4533.220 0.300 4533.520 ;
    END
  END gpio_loopback_one[35]
  PIN gpio_loopback_one[36]
    DIRECTION INPUT ;
    USE SIGNAL ;
    PORT
      LAYER met3 ;
        RECT -2.000 3683.220 0.300 3683.520 ;
    END
  END gpio_loopback_one[36]
  PIN gpio_loopback_one[37]
    DIRECTION INPUT ;
    USE SIGNAL ;
    PORT
      LAYER met3 ;
        RECT -2.000 3468.220 0.300 3468.520 ;
    END
  END gpio_loopback_one[37]
  PIN gpio_loopback_one[38]
    DIRECTION INPUT ;
    USE SIGNAL ;
    PORT
      LAYER met3 ;
        RECT -2.000 3253.220 0.300 3253.520 ;
    END
  END gpio_loopback_one[38]
  PIN gpio_loopback_one[39]
    DIRECTION INPUT ;
    USE SIGNAL ;
    PORT
      LAYER met3 ;
        RECT -2.000 3038.220 0.300 3038.520 ;
    END
  END gpio_loopback_one[39]
  PIN gpio_loopback_one[3]
    DIRECTION INPUT ;
    USE SIGNAL ;
    PORT
      LAYER met3 ;
        RECT 6754.330 1055.025 6756.630 1055.335 ;
    END
  END gpio_loopback_one[3]
  PIN gpio_loopback_one[40]
    DIRECTION INPUT ;
    USE SIGNAL ;
    PORT
      LAYER met3 ;
        RECT -2.000 2823.220 0.300 2823.520 ;
    END
  END gpio_loopback_one[40]
  PIN gpio_loopback_one[41]
    DIRECTION INPUT ;
    USE SIGNAL ;
    PORT
      LAYER met3 ;
        RECT -2.000 2608.220 0.300 2608.520 ;
    END
  END gpio_loopback_one[41]
  PIN gpio_loopback_one[42]
    DIRECTION INPUT ;
    USE SIGNAL ;
    PORT
      LAYER met3 ;
        RECT -2.000 2393.220 0.300 2393.520 ;
    END
  END gpio_loopback_one[42]
  PIN gpio_loopback_one[43]
    DIRECTION INPUT ;
    USE SIGNAL ;
    PORT
      LAYER met3 ;
        RECT -2.000 1748.220 0.300 1748.520 ;
    END
  END gpio_loopback_one[43]
  PIN gpio_loopback_one[44]
    DIRECTION INPUT ;
    USE SIGNAL ;
    PORT
      LAYER met3 ;
        RECT -2.000 1533.220 0.300 1533.520 ;
    END
  END gpio_loopback_one[44]
  PIN gpio_loopback_one[45]
    DIRECTION INPUT ;
    USE SIGNAL ;
    PORT
      LAYER met3 ;
        RECT -2.000 1318.220 0.300 1318.520 ;
    END
  END gpio_loopback_one[45]
  PIN gpio_loopback_one[46]
    DIRECTION INPUT ;
    USE SIGNAL ;
    PORT
      LAYER met3 ;
        RECT -2.000 1103.220 0.300 1103.520 ;
    END
  END gpio_loopback_one[46]
  PIN gpio_loopback_one[47]
    DIRECTION INPUT ;
    USE SIGNAL ;
    PORT
      LAYER met3 ;
        RECT -2.000 888.220 0.300 888.520 ;
    END
  END gpio_loopback_one[47]
  PIN gpio_loopback_one[48]
    DIRECTION INPUT ;
    USE SIGNAL ;
    PORT
      LAYER met3 ;
        RECT -2.000 673.220 0.300 673.520 ;
    END
  END gpio_loopback_one[48]
  PIN gpio_loopback_one[49]
    DIRECTION INPUT ;
    USE SIGNAL ;
    PORT
      LAYER met2 ;
        RECT 802.900 -2.000 803.160 0.280 ;
    END
  END gpio_loopback_one[49]
  PIN gpio_loopback_one[4]
    DIRECTION INPUT ;
    USE SIGNAL ;
    PORT
      LAYER met3 ;
        RECT 6754.330 1280.025 6756.630 1280.335 ;
    END
  END gpio_loopback_one[4]
  PIN gpio_loopback_one[50]
    DIRECTION INPUT ;
    USE SIGNAL ;
    PORT
      LAYER met2 ;
        RECT 1345.900 -2.000 1346.160 0.280 ;
    END
  END gpio_loopback_one[50]
  PIN gpio_loopback_one[51]
    DIRECTION INPUT ;
    USE SIGNAL ;
    PORT
      LAYER met2 ;
        RECT 1619.900 -2.000 1620.160 0.280 ;
    END
  END gpio_loopback_one[51]
  PIN gpio_loopback_one[52]
    DIRECTION INPUT ;
    USE SIGNAL ;
    PORT
      LAYER met2 ;
        RECT 1893.900 -2.000 1894.160 0.280 ;
    END
  END gpio_loopback_one[52]
  PIN gpio_loopback_one[53]
    DIRECTION INPUT ;
    USE SIGNAL ;
    PORT
      LAYER met2 ;
        RECT 2167.900 -2.000 2168.160 0.280 ;
    END
  END gpio_loopback_one[53]
  PIN gpio_loopback_one[54]
    DIRECTION INPUT ;
    USE SIGNAL ;
    PORT
      LAYER met2 ;
        RECT 2441.900 -2.000 2442.160 0.280 ;
    END
  END gpio_loopback_one[54]
  PIN gpio_loopback_one[55]
    DIRECTION INPUT ;
    USE SIGNAL ;
    PORT
      LAYER met2 ;
        RECT 3256.380 -2.000 3256.640 0.280 ;
    END
  END gpio_loopback_one[55]
  PIN gpio_loopback_one[56]
    DIRECTION INPUT ;
    USE SIGNAL ;
    PORT
      LAYER met2 ;
        RECT 3530.380 -2.000 3530.640 0.280 ;
    END
  END gpio_loopback_one[56]
  PIN gpio_loopback_one[57]
    DIRECTION INPUT ;
    USE SIGNAL ;
    PORT
      LAYER met2 ;
        RECT 4390.900 -2.000 4391.160 0.280 ;
    END
  END gpio_loopback_one[57]
  PIN gpio_loopback_one[58]
    DIRECTION INPUT ;
    USE SIGNAL ;
    PORT
      LAYER met2 ;
        RECT 4933.900 -2.000 4934.160 0.280 ;
    END
  END gpio_loopback_one[58]
  PIN gpio_loopback_one[59]
    DIRECTION INPUT ;
    USE SIGNAL ;
    PORT
      LAYER met2 ;
        RECT 5207.900 -2.000 5208.160 0.280 ;
    END
  END gpio_loopback_one[59]
  PIN gpio_loopback_one[5]
    DIRECTION INPUT ;
    USE SIGNAL ;
    PORT
      LAYER met3 ;
        RECT 6754.330 1505.025 6756.630 1505.335 ;
    END
  END gpio_loopback_one[5]
  PIN gpio_loopback_one[60]
    DIRECTION INPUT ;
    USE SIGNAL ;
    PORT
      LAYER met2 ;
        RECT 5481.900 -2.000 5482.160 0.280 ;
    END
  END gpio_loopback_one[60]
  PIN gpio_loopback_one[61]
    DIRECTION INPUT ;
    USE SIGNAL ;
    PORT
      LAYER met2 ;
        RECT 5755.900 -2.000 5756.160 0.280 ;
    END
  END gpio_loopback_one[61]
  PIN gpio_loopback_one[62]
    DIRECTION INPUT ;
    USE SIGNAL ;
    PORT
      LAYER met2 ;
        RECT 6029.900 -2.000 6030.160 0.280 ;
    END
  END gpio_loopback_one[62]
  PIN gpio_loopback_one[6]
    DIRECTION INPUT ;
    USE SIGNAL ;
    PORT
      LAYER met3 ;
        RECT 6754.330 1730.025 6756.630 1730.335 ;
    END
  END gpio_loopback_one[6]
  PIN gpio_loopback_one[7]
    DIRECTION INPUT ;
    USE SIGNAL ;
    PORT
      LAYER met3 ;
        RECT 6754.330 2615.025 6756.630 2615.335 ;
    END
  END gpio_loopback_one[7]
  PIN gpio_loopback_one[8]
    DIRECTION INPUT ;
    USE SIGNAL ;
    PORT
      LAYER met3 ;
        RECT 6754.330 2840.030 6756.630 2840.340 ;
    END
  END gpio_loopback_one[8]
  PIN gpio_loopback_one[9]
    DIRECTION INPUT ;
    USE SIGNAL ;
    PORT
      LAYER met3 ;
        RECT 6754.330 3065.030 6756.630 3065.340 ;
    END
  END gpio_loopback_one[9]
  PIN gpio_loopback_zero[0]
    DIRECTION INPUT ;
    USE SIGNAL ;
    PORT
      LAYER met3 ;
        RECT 6754.330 390.030 6756.630 390.340 ;
    END
  END gpio_loopback_zero[0]
  PIN gpio_loopback_zero[10]
    DIRECTION INPUT ;
    USE SIGNAL ;
    PORT
      LAYER met3 ;
        RECT 6754.330 3300.030 6756.630 3300.340 ;
    END
  END gpio_loopback_zero[10]
  PIN gpio_loopback_zero[11]
    DIRECTION INPUT ;
    USE SIGNAL ;
    PORT
      LAYER met3 ;
        RECT 6754.330 3525.030 6756.630 3525.340 ;
    END
  END gpio_loopback_zero[11]
  PIN gpio_loopback_zero[12]
    DIRECTION INPUT ;
    USE SIGNAL ;
    PORT
      LAYER met3 ;
        RECT 6754.330 3750.030 6756.630 3750.340 ;
    END
  END gpio_loopback_zero[12]
  PIN gpio_loopback_zero[13]
    DIRECTION INPUT ;
    USE SIGNAL ;
    PORT
      LAYER met3 ;
        RECT 6754.330 4195.030 6756.630 4195.340 ;
    END
  END gpio_loopback_zero[13]
  PIN gpio_loopback_zero[14]
    DIRECTION INPUT ;
    USE SIGNAL ;
    PORT
      LAYER met3 ;
        RECT 6754.330 4645.030 6756.630 4645.340 ;
    END
  END gpio_loopback_zero[14]
  PIN gpio_loopback_zero[15]
    DIRECTION INPUT ;
    USE SIGNAL ;
    PORT
      LAYER met2 ;
        RECT 6469.490 4766.350 6469.790 4768.630 ;
    END
  END gpio_loopback_zero[15]
  PIN gpio_loopback_zero[16]
    DIRECTION INPUT ;
    USE SIGNAL ;
    PORT
      LAYER met2 ;
        RECT 5972.490 4766.350 5972.790 4768.630 ;
    END
  END gpio_loopback_zero[16]
  PIN gpio_loopback_zero[17]
    DIRECTION INPUT ;
    USE SIGNAL ;
    PORT
      LAYER met2 ;
        RECT 5716.490 4766.350 5716.790 4768.630 ;
    END
  END gpio_loopback_zero[17]
  PIN gpio_loopback_zero[18]
    DIRECTION INPUT ;
    USE SIGNAL ;
    PORT
      LAYER met2 ;
        RECT 5271.490 4766.350 5271.790 4768.630 ;
    END
  END gpio_loopback_zero[18]
  PIN gpio_loopback_zero[19]
    DIRECTION INPUT ;
    USE SIGNAL ;
    PORT
      LAYER met2 ;
        RECT 4749.490 4766.350 4749.790 4768.630 ;
    END
  END gpio_loopback_zero[19]
  PIN gpio_loopback_zero[1]
    DIRECTION INPUT ;
    USE SIGNAL ;
    PORT
      LAYER met3 ;
        RECT 6754.330 615.030 6756.630 615.340 ;
    END
  END gpio_loopback_zero[1]
  PIN gpio_loopback_zero[20]
    DIRECTION INPUT ;
    USE SIGNAL ;
    PORT
      LAYER met2 ;
        RECT 4493.490 4766.350 4493.790 4768.630 ;
    END
  END gpio_loopback_zero[20]
  PIN gpio_loopback_zero[21]
    DIRECTION INPUT ;
    USE SIGNAL ;
    PORT
      LAYER met2 ;
        RECT 4237.490 4766.350 4237.790 4768.630 ;
    END
  END gpio_loopback_zero[21]
  PIN gpio_loopback_zero[22]
    DIRECTION INPUT ;
    USE SIGNAL ;
    PORT
      LAYER met2 ;
        RECT 3981.490 4766.350 3981.790 4768.630 ;
    END
  END gpio_loopback_zero[22]
  PIN gpio_loopback_zero[23]
    DIRECTION INPUT ;
    USE SIGNAL ;
    PORT
      LAYER met2 ;
        RECT 3725.490 4766.350 3725.790 4768.630 ;
    END
  END gpio_loopback_zero[23]
  PIN gpio_loopback_zero[24]
    DIRECTION INPUT ;
    USE SIGNAL ;
    PORT
      LAYER met2 ;
        RECT 3400.490 4766.350 3400.790 4768.630 ;
    END
  END gpio_loopback_zero[24]
  PIN gpio_loopback_zero[25]
    DIRECTION INPUT ;
    USE SIGNAL ;
    PORT
      LAYER met2 ;
        RECT 3143.490 4766.350 3143.790 4768.630 ;
    END
  END gpio_loopback_zero[25]
  PIN gpio_loopback_zero[26]
    DIRECTION INPUT ;
    USE SIGNAL ;
    PORT
      LAYER met2 ;
        RECT 2881.490 4766.350 2881.790 4768.630 ;
    END
  END gpio_loopback_zero[26]
  PIN gpio_loopback_zero[27]
    DIRECTION INPUT ;
    USE SIGNAL ;
    PORT
      LAYER met2 ;
        RECT 2384.490 4766.350 2384.790 4768.630 ;
    END
  END gpio_loopback_zero[27]
  PIN gpio_loopback_zero[28]
    DIRECTION INPUT ;
    USE SIGNAL ;
    PORT
      LAYER met2 ;
        RECT 2128.490 4766.350 2128.790 4768.630 ;
    END
  END gpio_loopback_zero[28]
  PIN gpio_loopback_zero[29]
    DIRECTION INPUT ;
    USE SIGNAL ;
    PORT
      LAYER met2 ;
        RECT 1683.490 4766.350 1683.790 4768.630 ;
    END
  END gpio_loopback_zero[29]
  PIN gpio_loopback_zero[2]
    DIRECTION INPUT ;
    USE SIGNAL ;
    PORT
      LAYER met3 ;
        RECT 6754.330 840.030 6756.630 840.340 ;
    END
  END gpio_loopback_zero[2]
  PIN gpio_loopback_zero[30]
    DIRECTION INPUT ;
    USE SIGNAL ;
    PORT
      LAYER met2 ;
        RECT 1161.490 4766.350 1161.790 4768.630 ;
    END
  END gpio_loopback_zero[30]
  PIN gpio_loopback_zero[31]
    DIRECTION INPUT ;
    USE SIGNAL ;
    PORT
      LAYER met2 ;
        RECT 905.490 4766.350 905.790 4768.630 ;
    END
  END gpio_loopback_zero[31]
  PIN gpio_loopback_zero[32]
    DIRECTION INPUT ;
    USE SIGNAL ;
    PORT
      LAYER met2 ;
        RECT 649.490 4766.350 649.790 4768.630 ;
    END
  END gpio_loopback_zero[32]
  PIN gpio_loopback_zero[33]
    DIRECTION INPUT ;
    USE SIGNAL ;
    PORT
      LAYER met2 ;
        RECT 393.490 4766.350 393.790 4768.630 ;
    END
  END gpio_loopback_zero[33]
  PIN gpio_loopback_zero[34]
    DIRECTION INPUT ;
    USE SIGNAL ;
    PORT
      LAYER met2 ;
        RECT 137.490 4766.350 137.790 4768.630 ;
    END
  END gpio_loopback_zero[34]
  PIN gpio_loopback_zero[35]
    DIRECTION INPUT ;
    USE SIGNAL ;
    PORT
      LAYER met3 ;
        RECT -2.000 4523.220 0.300 4523.520 ;
    END
  END gpio_loopback_zero[35]
  PIN gpio_loopback_zero[36]
    DIRECTION INPUT ;
    USE SIGNAL ;
    PORT
      LAYER met3 ;
        RECT -2.000 3673.220 0.300 3673.520 ;
    END
  END gpio_loopback_zero[36]
  PIN gpio_loopback_zero[37]
    DIRECTION INPUT ;
    USE SIGNAL ;
    PORT
      LAYER met3 ;
        RECT -2.000 3458.220 0.300 3458.520 ;
    END
  END gpio_loopback_zero[37]
  PIN gpio_loopback_zero[38]
    DIRECTION INPUT ;
    USE SIGNAL ;
    PORT
      LAYER met3 ;
        RECT -2.000 3243.220 0.300 3243.520 ;
    END
  END gpio_loopback_zero[38]
  PIN gpio_loopback_zero[39]
    DIRECTION INPUT ;
    USE SIGNAL ;
    PORT
      LAYER met3 ;
        RECT -2.000 3028.220 0.300 3028.520 ;
    END
  END gpio_loopback_zero[39]
  PIN gpio_loopback_zero[3]
    DIRECTION INPUT ;
    USE SIGNAL ;
    PORT
      LAYER met3 ;
        RECT 6754.330 1065.030 6756.630 1065.340 ;
    END
  END gpio_loopback_zero[3]
  PIN gpio_loopback_zero[40]
    DIRECTION INPUT ;
    USE SIGNAL ;
    PORT
      LAYER met3 ;
        RECT -2.000 2813.220 0.300 2813.520 ;
    END
  END gpio_loopback_zero[40]
  PIN gpio_loopback_zero[41]
    DIRECTION INPUT ;
    USE SIGNAL ;
    PORT
      LAYER met3 ;
        RECT -2.000 2598.220 0.300 2598.520 ;
    END
  END gpio_loopback_zero[41]
  PIN gpio_loopback_zero[42]
    DIRECTION INPUT ;
    USE SIGNAL ;
    PORT
      LAYER met3 ;
        RECT -2.000 2383.220 0.300 2383.520 ;
    END
  END gpio_loopback_zero[42]
  PIN gpio_loopback_zero[43]
    DIRECTION INPUT ;
    USE SIGNAL ;
    PORT
      LAYER met3 ;
        RECT -2.000 1738.220 0.300 1738.520 ;
    END
  END gpio_loopback_zero[43]
  PIN gpio_loopback_zero[44]
    DIRECTION INPUT ;
    USE SIGNAL ;
    PORT
      LAYER met3 ;
        RECT -2.000 1523.220 0.300 1523.520 ;
    END
  END gpio_loopback_zero[44]
  PIN gpio_loopback_zero[45]
    DIRECTION INPUT ;
    USE SIGNAL ;
    PORT
      LAYER met3 ;
        RECT -2.000 1308.220 0.300 1308.520 ;
    END
  END gpio_loopback_zero[45]
  PIN gpio_loopback_zero[46]
    DIRECTION INPUT ;
    USE SIGNAL ;
    PORT
      LAYER met3 ;
        RECT -2.000 1093.220 0.300 1093.520 ;
    END
  END gpio_loopback_zero[46]
  PIN gpio_loopback_zero[47]
    DIRECTION INPUT ;
    USE SIGNAL ;
    PORT
      LAYER met3 ;
        RECT -2.000 878.220 0.300 878.520 ;
    END
  END gpio_loopback_zero[47]
  PIN gpio_loopback_zero[48]
    DIRECTION INPUT ;
    USE SIGNAL ;
    PORT
      LAYER met3 ;
        RECT -2.000 663.220 0.300 663.520 ;
    END
  END gpio_loopback_zero[48]
  PIN gpio_loopback_zero[49]
    DIRECTION INPUT ;
    USE SIGNAL ;
    PORT
      LAYER met2 ;
        RECT 818.955 -2.000 819.215 0.280 ;
    END
  END gpio_loopback_zero[49]
  PIN gpio_loopback_zero[4]
    DIRECTION INPUT ;
    USE SIGNAL ;
    PORT
      LAYER met3 ;
        RECT 6754.330 1290.030 6756.630 1290.340 ;
    END
  END gpio_loopback_zero[4]
  PIN gpio_loopback_zero[50]
    DIRECTION INPUT ;
    USE SIGNAL ;
    PORT
      LAYER met2 ;
        RECT 1366.800 -2.000 1367.060 0.280 ;
    END
  END gpio_loopback_zero[50]
  PIN gpio_loopback_zero[51]
    DIRECTION INPUT ;
    USE SIGNAL ;
    PORT
      LAYER met2 ;
        RECT 1640.825 -2.000 1641.085 0.280 ;
    END
  END gpio_loopback_zero[51]
  PIN gpio_loopback_zero[52]
    DIRECTION INPUT ;
    USE SIGNAL ;
    PORT
      LAYER met2 ;
        RECT 1914.890 -2.000 1915.150 0.280 ;
    END
  END gpio_loopback_zero[52]
  PIN gpio_loopback_zero[53]
    DIRECTION INPUT ;
    USE SIGNAL ;
    PORT
      LAYER met2 ;
        RECT 2188.890 -2.000 2189.150 0.280 ;
    END
  END gpio_loopback_zero[53]
  PIN gpio_loopback_zero[54]
    DIRECTION INPUT ;
    USE SIGNAL ;
    PORT
      LAYER met2 ;
        RECT 2463.175 -2.000 2463.435 0.280 ;
    END
  END gpio_loopback_zero[54]
  PIN gpio_loopback_zero[55]
    DIRECTION INPUT ;
    USE SIGNAL ;
    PORT
      LAYER met2 ;
        RECT 3272.435 -2.000 3272.695 0.280 ;
    END
  END gpio_loopback_zero[55]
  PIN gpio_loopback_zero[56]
    DIRECTION INPUT ;
    USE SIGNAL ;
    PORT
      LAYER met2 ;
        RECT 3546.435 -2.000 3546.695 0.280 ;
    END
  END gpio_loopback_zero[56]
  PIN gpio_loopback_zero[57]
    DIRECTION INPUT ;
    USE SIGNAL ;
    PORT
      LAYER met2 ;
        RECT 4406.955 -2.000 4407.215 0.280 ;
    END
  END gpio_loopback_zero[57]
  PIN gpio_loopback_zero[58]
    DIRECTION INPUT ;
    USE SIGNAL ;
    PORT
      LAYER met2 ;
        RECT 4954.800 -2.000 4955.060 0.280 ;
    END
  END gpio_loopback_zero[58]
  PIN gpio_loopback_zero[59]
    DIRECTION INPUT ;
    USE SIGNAL ;
    PORT
      LAYER met2 ;
        RECT 5228.825 -2.000 5229.085 0.280 ;
    END
  END gpio_loopback_zero[59]
  PIN gpio_loopback_zero[5]
    DIRECTION INPUT ;
    USE SIGNAL ;
    PORT
      LAYER met3 ;
        RECT 6754.330 1515.030 6756.630 1515.340 ;
    END
  END gpio_loopback_zero[5]
  PIN gpio_loopback_zero[60]
    DIRECTION INPUT ;
    USE SIGNAL ;
    PORT
      LAYER met2 ;
        RECT 5502.890 -2.000 5503.150 0.280 ;
    END
  END gpio_loopback_zero[60]
  PIN gpio_loopback_zero[61]
    DIRECTION INPUT ;
    USE SIGNAL ;
    PORT
      LAYER met2 ;
        RECT 5776.890 -2.000 5777.150 0.280 ;
    END
  END gpio_loopback_zero[61]
  PIN gpio_loopback_zero[62]
    DIRECTION INPUT ;
    USE SIGNAL ;
    PORT
      LAYER met2 ;
        RECT 6051.175 -2.000 6051.435 0.280 ;
    END
  END gpio_loopback_zero[62]
  PIN gpio_loopback_zero[6]
    DIRECTION INPUT ;
    USE SIGNAL ;
    PORT
      LAYER met3 ;
        RECT 6754.330 1740.030 6756.630 1740.340 ;
    END
  END gpio_loopback_zero[6]
  PIN gpio_loopback_zero[7]
    DIRECTION INPUT ;
    USE SIGNAL ;
    PORT
      LAYER met3 ;
        RECT 6754.330 2625.030 6756.630 2625.340 ;
    END
  END gpio_loopback_zero[7]
  PIN gpio_loopback_zero[8]
    DIRECTION INPUT ;
    USE SIGNAL ;
    PORT
      LAYER met3 ;
        RECT 6754.330 2850.030 6756.630 2850.340 ;
    END
  END gpio_loopback_zero[8]
  PIN gpio_loopback_zero[9]
    DIRECTION INPUT ;
    USE SIGNAL ;
    PORT
      LAYER met3 ;
        RECT 6754.330 3075.030 6756.630 3075.340 ;
    END
  END gpio_loopback_zero[9]
  PIN gpio_oeb[0]
    DIRECTION OUTPUT ;
    USE SIGNAL ;
    PORT
      LAYER met3 ;
        RECT 6754.330 364.760 6756.630 365.110 ;
    END
  END gpio_oeb[0]
  PIN gpio_oeb[10]
    DIRECTION OUTPUT ;
    USE SIGNAL ;
    PORT
      LAYER met3 ;
        RECT 6754.330 3280.760 6756.630 3281.110 ;
    END
  END gpio_oeb[10]
  PIN gpio_oeb[11]
    DIRECTION OUTPUT ;
    USE SIGNAL ;
    PORT
      LAYER met3 ;
        RECT 6754.330 3505.760 6756.630 3506.110 ;
    END
  END gpio_oeb[11]
  PIN gpio_oeb[12]
    DIRECTION OUTPUT ;
    USE SIGNAL ;
    PORT
      LAYER met3 ;
        RECT 6754.330 3730.760 6756.630 3731.110 ;
    END
  END gpio_oeb[12]
  PIN gpio_oeb[13]
    DIRECTION OUTPUT ;
    USE SIGNAL ;
    PORT
      LAYER met3 ;
        RECT 6754.330 4176.760 6756.630 4177.110 ;
    END
  END gpio_oeb[13]
  PIN gpio_oeb[14]
    DIRECTION OUTPUT ;
    USE SIGNAL ;
    PORT
      LAYER met3 ;
        RECT 6754.330 4622.760 6756.630 4623.110 ;
    END
  END gpio_oeb[14]
  PIN gpio_oeb[15]
    DIRECTION OUTPUT ;
    USE SIGNAL ;
    PORT
      LAYER met2 ;
        RECT 6511.560 4766.350 6511.840 4768.630 ;
    END
  END gpio_oeb[15]
  PIN gpio_oeb[16]
    DIRECTION OUTPUT ;
    USE SIGNAL ;
    PORT
      LAYER met2 ;
        RECT 6002.560 4766.350 6002.840 4768.630 ;
    END
  END gpio_oeb[16]
  PIN gpio_oeb[17]
    DIRECTION OUTPUT ;
    USE SIGNAL ;
    PORT
      LAYER met2 ;
        RECT 5745.560 4766.350 5745.840 4768.630 ;
    END
  END gpio_oeb[17]
  PIN gpio_oeb[18]
    DIRECTION OUTPUT ;
    USE SIGNAL ;
    PORT
      LAYER met2 ;
        RECT 5300.560 4766.350 5300.840 4768.630 ;
    END
  END gpio_oeb[18]
  PIN gpio_oeb[19]
    DIRECTION OUTPUT ;
    USE SIGNAL ;
    PORT
      LAYER met2 ;
        RECT 4791.560 4766.350 4791.840 4768.630 ;
    END
  END gpio_oeb[19]
  PIN gpio_oeb[1]
    DIRECTION OUTPUT ;
    USE SIGNAL ;
    PORT
      LAYER met3 ;
        RECT 6754.330 590.760 6756.630 591.110 ;
    END
  END gpio_oeb[1]
  PIN gpio_oeb[20]
    DIRECTION OUTPUT ;
    USE SIGNAL ;
    PORT
      LAYER met2 ;
        RECT 4533.560 4766.350 4533.840 4768.630 ;
    END
  END gpio_oeb[20]
  PIN gpio_oeb[21]
    DIRECTION OUTPUT ;
    USE SIGNAL ;
    PORT
      LAYER met2 ;
        RECT 4276.560 4766.350 4276.840 4768.630 ;
    END
  END gpio_oeb[21]
  PIN gpio_oeb[22]
    DIRECTION OUTPUT ;
    USE SIGNAL ;
    PORT
      LAYER met2 ;
        RECT 4019.560 4766.350 4019.840 4768.630 ;
    END
  END gpio_oeb[22]
  PIN gpio_oeb[23]
    DIRECTION OUTPUT ;
    USE SIGNAL ;
    PORT
      LAYER met2 ;
        RECT 3762.560 4766.350 3762.840 4768.630 ;
    END
  END gpio_oeb[23]
  PIN gpio_oeb[24]
    DIRECTION OUTPUT ;
    USE SIGNAL ;
    PORT
      LAYER met2 ;
        RECT 3437.560 4766.350 3437.840 4768.630 ;
    END
  END gpio_oeb[24]
  PIN gpio_oeb[25]
    DIRECTION OUTPUT ;
    USE SIGNAL ;
    PORT
      LAYER met2 ;
        RECT 3180.560 4766.350 3180.840 4768.630 ;
    END
  END gpio_oeb[25]
  PIN gpio_oeb[26]
    DIRECTION OUTPUT ;
    USE SIGNAL ;
    PORT
      LAYER met2 ;
        RECT 2923.560 4766.350 2923.840 4768.630 ;
    END
  END gpio_oeb[26]
  PIN gpio_oeb[27]
    DIRECTION OUTPUT ;
    USE SIGNAL ;
    PORT
      LAYER met2 ;
        RECT 2414.560 4766.350 2414.840 4768.630 ;
    END
  END gpio_oeb[27]
  PIN gpio_oeb[28]
    DIRECTION OUTPUT ;
    USE SIGNAL ;
    PORT
      LAYER met2 ;
        RECT 2157.560 4766.350 2157.840 4768.630 ;
    END
  END gpio_oeb[28]
  PIN gpio_oeb[29]
    DIRECTION OUTPUT ;
    USE SIGNAL ;
    PORT
      LAYER met2 ;
        RECT 1712.560 4766.350 1712.840 4768.630 ;
    END
  END gpio_oeb[29]
  PIN gpio_oeb[2]
    DIRECTION OUTPUT ;
    USE SIGNAL ;
    PORT
      LAYER met3 ;
        RECT 6754.330 815.760 6756.630 816.110 ;
    END
  END gpio_oeb[2]
  PIN gpio_oeb[30]
    DIRECTION OUTPUT ;
    USE SIGNAL ;
    PORT
      LAYER met2 ;
        RECT 1203.560 4766.350 1203.840 4768.630 ;
    END
  END gpio_oeb[30]
  PIN gpio_oeb[31]
    DIRECTION OUTPUT ;
    USE SIGNAL ;
    PORT
      LAYER met2 ;
        RECT 945.560 4766.350 945.840 4768.630 ;
    END
  END gpio_oeb[31]
  PIN gpio_oeb[32]
    DIRECTION OUTPUT ;
    USE SIGNAL ;
    PORT
      LAYER met2 ;
        RECT 688.560 4766.350 688.840 4768.630 ;
    END
  END gpio_oeb[32]
  PIN gpio_oeb[33]
    DIRECTION OUTPUT ;
    USE SIGNAL ;
    PORT
      LAYER met2 ;
        RECT 431.560 4766.350 431.840 4768.630 ;
    END
  END gpio_oeb[33]
  PIN gpio_oeb[34]
    DIRECTION OUTPUT ;
    USE SIGNAL ;
    PORT
      LAYER met2 ;
        RECT 174.560 4766.350 174.840 4768.630 ;
    END
  END gpio_oeb[34]
  PIN gpio_oeb[35]
    DIRECTION OUTPUT ;
    USE SIGNAL ;
    PORT
      LAYER met3 ;
        RECT -2.000 4564.520 0.300 4564.870 ;
    END
  END gpio_oeb[35]
  PIN gpio_oeb[36]
    DIRECTION OUTPUT ;
    USE SIGNAL ;
    PORT
      LAYER met3 ;
        RECT -2.000 3715.520 0.300 3715.870 ;
    END
  END gpio_oeb[36]
  PIN gpio_oeb[37]
    DIRECTION OUTPUT ;
    USE SIGNAL ;
    PORT
      LAYER met3 ;
        RECT -2.000 3499.520 0.300 3499.870 ;
    END
  END gpio_oeb[37]
  PIN gpio_oeb[38]
    DIRECTION OUTPUT ;
    USE SIGNAL ;
    PORT
      LAYER met3 ;
        RECT -2.000 3283.520 0.300 3283.870 ;
    END
  END gpio_oeb[38]
  PIN gpio_oeb[39]
    DIRECTION OUTPUT ;
    USE SIGNAL ;
    PORT
      LAYER met3 ;
        RECT -2.000 3067.520 0.300 3067.870 ;
    END
  END gpio_oeb[39]
  PIN gpio_oeb[3]
    DIRECTION OUTPUT ;
    USE SIGNAL ;
    PORT
      LAYER met3 ;
        RECT 6754.330 1041.760 6756.630 1042.110 ;
    END
  END gpio_oeb[3]
  PIN gpio_oeb[40]
    DIRECTION OUTPUT ;
    USE SIGNAL ;
    PORT
      LAYER met3 ;
        RECT -2.000 2851.520 0.300 2851.870 ;
    END
  END gpio_oeb[40]
  PIN gpio_oeb[41]
    DIRECTION OUTPUT ;
    USE SIGNAL ;
    PORT
      LAYER met3 ;
        RECT -2.000 2635.520 0.300 2635.870 ;
    END
  END gpio_oeb[41]
  PIN gpio_oeb[42]
    DIRECTION OUTPUT ;
    USE SIGNAL ;
    PORT
      LAYER met3 ;
        RECT -2.000 2419.520 0.300 2419.870 ;
    END
  END gpio_oeb[42]
  PIN gpio_oeb[43]
    DIRECTION OUTPUT ;
    USE SIGNAL ;
    PORT
      LAYER met3 ;
        RECT -2.000 1781.520 0.300 1781.870 ;
    END
  END gpio_oeb[43]
  PIN gpio_oeb[44]
    DIRECTION OUTPUT ;
    USE SIGNAL ;
    PORT
      LAYER met3 ;
        RECT -2.000 1565.520 0.300 1565.870 ;
    END
  END gpio_oeb[44]
  PIN gpio_oeb[45]
    DIRECTION OUTPUT ;
    USE SIGNAL ;
    PORT
      LAYER met3 ;
        RECT -2.000 1349.520 0.300 1349.870 ;
    END
  END gpio_oeb[45]
  PIN gpio_oeb[46]
    DIRECTION OUTPUT ;
    USE SIGNAL ;
    PORT
      LAYER met3 ;
        RECT -2.000 1133.520 0.300 1133.870 ;
    END
  END gpio_oeb[46]
  PIN gpio_oeb[47]
    DIRECTION OUTPUT ;
    USE SIGNAL ;
    PORT
      LAYER met3 ;
        RECT -2.000 917.520 0.300 917.870 ;
    END
  END gpio_oeb[47]
  PIN gpio_oeb[48]
    DIRECTION OUTPUT ;
    USE SIGNAL ;
    PORT
      LAYER met3 ;
        RECT -2.000 701.520 0.300 701.870 ;
    END
  END gpio_oeb[48]
  PIN gpio_oeb[49]
    DIRECTION OUTPUT ;
    USE SIGNAL ;
    PORT
      LAYER met2 ;
        RECT 796.790 -2.000 797.070 0.280 ;
    END
  END gpio_oeb[49]
  PIN gpio_oeb[4]
    DIRECTION OUTPUT ;
    USE SIGNAL ;
    PORT
      LAYER met3 ;
        RECT 6754.330 1266.760 6756.630 1267.110 ;
    END
  END gpio_oeb[4]
  PIN gpio_oeb[50]
    DIRECTION OUTPUT ;
    USE SIGNAL ;
    PORT
      LAYER met2 ;
        RECT 1339.790 -2.000 1340.070 0.280 ;
    END
  END gpio_oeb[50]
  PIN gpio_oeb[51]
    DIRECTION OUTPUT ;
    USE SIGNAL ;
    PORT
      LAYER met2 ;
        RECT 1613.790 -2.000 1614.070 0.280 ;
    END
  END gpio_oeb[51]
  PIN gpio_oeb[52]
    DIRECTION OUTPUT ;
    USE SIGNAL ;
    PORT
      LAYER met2 ;
        RECT 1887.790 -2.000 1888.070 0.280 ;
    END
  END gpio_oeb[52]
  PIN gpio_oeb[53]
    DIRECTION OUTPUT ;
    USE SIGNAL ;
    PORT
      LAYER met2 ;
        RECT 2161.790 -2.000 2162.070 0.280 ;
    END
  END gpio_oeb[53]
  PIN gpio_oeb[54]
    DIRECTION OUTPUT ;
    USE SIGNAL ;
    PORT
      LAYER met2 ;
        RECT 2435.790 -2.000 2436.070 0.280 ;
    END
  END gpio_oeb[54]
  PIN gpio_oeb[55]
    DIRECTION OUTPUT ;
    USE SIGNAL ;
    PORT
      LAYER met2 ;
        RECT 3250.270 -2.000 3250.550 0.280 ;
    END
  END gpio_oeb[55]
  PIN gpio_oeb[56]
    DIRECTION OUTPUT ;
    USE SIGNAL ;
    PORT
      LAYER met2 ;
        RECT 3524.270 -2.000 3524.550 0.280 ;
    END
  END gpio_oeb[56]
  PIN gpio_oeb[57]
    DIRECTION OUTPUT ;
    USE SIGNAL ;
    PORT
      LAYER met2 ;
        RECT 4384.790 -2.000 4385.070 0.280 ;
    END
  END gpio_oeb[57]
  PIN gpio_oeb[58]
    DIRECTION OUTPUT ;
    USE SIGNAL ;
    PORT
      LAYER met2 ;
        RECT 4927.790 -2.000 4928.070 0.280 ;
    END
  END gpio_oeb[58]
  PIN gpio_oeb[59]
    DIRECTION OUTPUT ;
    USE SIGNAL ;
    PORT
      LAYER met2 ;
        RECT 5201.790 -2.000 5202.070 0.280 ;
    END
  END gpio_oeb[59]
  PIN gpio_oeb[5]
    DIRECTION OUTPUT ;
    USE SIGNAL ;
    PORT
      LAYER met3 ;
        RECT 6754.330 1491.760 6756.630 1492.110 ;
    END
  END gpio_oeb[5]
  PIN gpio_oeb[60]
    DIRECTION OUTPUT ;
    USE SIGNAL ;
    PORT
      LAYER met2 ;
        RECT 5475.790 -2.000 5476.070 0.280 ;
    END
  END gpio_oeb[60]
  PIN gpio_oeb[61]
    DIRECTION OUTPUT ;
    USE SIGNAL ;
    PORT
      LAYER met2 ;
        RECT 5749.790 -2.000 5750.070 0.280 ;
    END
  END gpio_oeb[61]
  PIN gpio_oeb[62]
    DIRECTION OUTPUT ;
    USE SIGNAL ;
    PORT
      LAYER met2 ;
        RECT 6023.790 -2.000 6024.070 0.280 ;
    END
  END gpio_oeb[62]
  PIN gpio_oeb[6]
    DIRECTION OUTPUT ;
    USE SIGNAL ;
    PORT
      LAYER met3 ;
        RECT 6754.330 1717.760 6756.630 1718.110 ;
    END
  END gpio_oeb[6]
  PIN gpio_oeb[7]
    DIRECTION OUTPUT ;
    USE SIGNAL ;
    PORT
      LAYER met3 ;
        RECT 6754.330 2603.760 6756.630 2604.110 ;
    END
  END gpio_oeb[7]
  PIN gpio_oeb[8]
    DIRECTION OUTPUT ;
    USE SIGNAL ;
    PORT
      LAYER met3 ;
        RECT 6754.330 2829.760 6756.630 2830.110 ;
    END
  END gpio_oeb[8]
  PIN gpio_oeb[9]
    DIRECTION OUTPUT ;
    USE SIGNAL ;
    PORT
      LAYER met3 ;
        RECT 6754.330 3054.760 6756.630 3055.110 ;
    END
  END gpio_oeb[9]
  PIN gpio_out[0]
    DIRECTION OUTPUT ;
    USE SIGNAL ;
    PORT
      LAYER met3 ;
        RECT 6754.330 349.120 6756.630 349.470 ;
    END
  END gpio_out[0]
  PIN gpio_out[10]
    DIRECTION OUTPUT ;
    USE SIGNAL ;
    PORT
      LAYER met3 ;
        RECT 6754.330 3265.120 6756.630 3265.470 ;
    END
  END gpio_out[10]
  PIN gpio_out[11]
    DIRECTION OUTPUT ;
    USE SIGNAL ;
    PORT
      LAYER met3 ;
        RECT 6754.330 3490.120 6756.630 3490.470 ;
    END
  END gpio_out[11]
  PIN gpio_out[12]
    DIRECTION OUTPUT ;
    USE SIGNAL ;
    PORT
      LAYER met3 ;
        RECT 6754.330 3715.120 6756.630 3715.470 ;
    END
  END gpio_out[12]
  PIN gpio_out[13]
    DIRECTION OUTPUT ;
    USE SIGNAL ;
    PORT
      LAYER met3 ;
        RECT 6754.330 4161.120 6756.630 4161.470 ;
    END
  END gpio_out[13]
  PIN gpio_out[14]
    DIRECTION OUTPUT ;
    USE SIGNAL ;
    PORT
      LAYER met3 ;
        RECT 6754.330 4607.120 6756.630 4607.470 ;
    END
  END gpio_out[14]
  PIN gpio_out[15]
    DIRECTION OUTPUT ;
    USE SIGNAL ;
    PORT
      LAYER met2 ;
        RECT 6527.200 4766.350 6527.480 4768.630 ;
    END
  END gpio_out[15]
  PIN gpio_out[16]
    DIRECTION OUTPUT ;
    USE SIGNAL ;
    PORT
      LAYER met2 ;
        RECT 6018.200 4766.350 6018.480 4768.630 ;
    END
  END gpio_out[16]
  PIN gpio_out[17]
    DIRECTION OUTPUT ;
    USE SIGNAL ;
    PORT
      LAYER met2 ;
        RECT 5761.200 4766.350 5761.480 4768.630 ;
    END
  END gpio_out[17]
  PIN gpio_out[18]
    DIRECTION OUTPUT ;
    USE SIGNAL ;
    PORT
      LAYER met2 ;
        RECT 5316.200 4766.350 5316.480 4768.630 ;
    END
  END gpio_out[18]
  PIN gpio_out[19]
    DIRECTION OUTPUT ;
    USE SIGNAL ;
    PORT
      LAYER met2 ;
        RECT 4807.200 4766.350 4807.480 4768.630 ;
    END
  END gpio_out[19]
  PIN gpio_out[1]
    DIRECTION OUTPUT ;
    USE SIGNAL ;
    PORT
      LAYER met3 ;
        RECT 6754.330 575.120 6756.630 575.470 ;
    END
  END gpio_out[1]
  PIN gpio_out[20]
    DIRECTION OUTPUT ;
    USE SIGNAL ;
    PORT
      LAYER met2 ;
        RECT 4549.200 4766.350 4549.480 4768.630 ;
    END
  END gpio_out[20]
  PIN gpio_out[21]
    DIRECTION OUTPUT ;
    USE SIGNAL ;
    PORT
      LAYER met2 ;
        RECT 4292.200 4766.350 4292.480 4768.630 ;
    END
  END gpio_out[21]
  PIN gpio_out[22]
    DIRECTION OUTPUT ;
    USE SIGNAL ;
    PORT
      LAYER met2 ;
        RECT 4035.200 4766.350 4035.480 4768.630 ;
    END
  END gpio_out[22]
  PIN gpio_out[23]
    DIRECTION OUTPUT ;
    USE SIGNAL ;
    PORT
      LAYER met2 ;
        RECT 3778.200 4766.350 3778.480 4768.630 ;
    END
  END gpio_out[23]
  PIN gpio_out[24]
    DIRECTION OUTPUT ;
    USE SIGNAL ;
    PORT
      LAYER met2 ;
        RECT 3453.200 4766.350 3453.480 4768.630 ;
    END
  END gpio_out[24]
  PIN gpio_out[25]
    DIRECTION OUTPUT ;
    USE SIGNAL ;
    PORT
      LAYER met2 ;
        RECT 3196.200 4766.350 3196.480 4768.630 ;
    END
  END gpio_out[25]
  PIN gpio_out[26]
    DIRECTION OUTPUT ;
    USE SIGNAL ;
    PORT
      LAYER met2 ;
        RECT 2939.200 4766.350 2939.480 4768.630 ;
    END
  END gpio_out[26]
  PIN gpio_out[27]
    DIRECTION OUTPUT ;
    USE SIGNAL ;
    PORT
      LAYER met2 ;
        RECT 2430.200 4766.350 2430.480 4768.630 ;
    END
  END gpio_out[27]
  PIN gpio_out[28]
    DIRECTION OUTPUT ;
    USE SIGNAL ;
    PORT
      LAYER met2 ;
        RECT 2173.200 4766.350 2173.480 4768.630 ;
    END
  END gpio_out[28]
  PIN gpio_out[29]
    DIRECTION OUTPUT ;
    USE SIGNAL ;
    PORT
      LAYER met2 ;
        RECT 1728.200 4766.350 1728.480 4768.630 ;
    END
  END gpio_out[29]
  PIN gpio_out[2]
    DIRECTION OUTPUT ;
    USE SIGNAL ;
    PORT
      LAYER met3 ;
        RECT 6754.330 800.120 6756.630 800.470 ;
    END
  END gpio_out[2]
  PIN gpio_out[30]
    DIRECTION OUTPUT ;
    USE SIGNAL ;
    PORT
      LAYER met2 ;
        RECT 1219.200 4766.350 1219.480 4768.630 ;
    END
  END gpio_out[30]
  PIN gpio_out[31]
    DIRECTION OUTPUT ;
    USE SIGNAL ;
    PORT
      LAYER met2 ;
        RECT 961.200 4766.350 961.480 4768.630 ;
    END
  END gpio_out[31]
  PIN gpio_out[32]
    DIRECTION OUTPUT ;
    USE SIGNAL ;
    PORT
      LAYER met2 ;
        RECT 704.200 4766.350 704.480 4768.630 ;
    END
  END gpio_out[32]
  PIN gpio_out[33]
    DIRECTION OUTPUT ;
    USE SIGNAL ;
    PORT
      LAYER met2 ;
        RECT 447.200 4766.350 447.480 4768.630 ;
    END
  END gpio_out[33]
  PIN gpio_out[34]
    DIRECTION OUTPUT ;
    USE SIGNAL ;
    PORT
      LAYER met2 ;
        RECT 190.200 4766.350 190.480 4768.630 ;
    END
  END gpio_out[34]
  PIN gpio_out[35]
    DIRECTION OUTPUT ;
    USE SIGNAL ;
    PORT
      LAYER met3 ;
        RECT -2.000 4580.160 0.300 4580.510 ;
    END
  END gpio_out[35]
  PIN gpio_out[36]
    DIRECTION OUTPUT ;
    USE SIGNAL ;
    PORT
      LAYER met3 ;
        RECT -2.000 3731.160 0.300 3731.510 ;
    END
  END gpio_out[36]
  PIN gpio_out[37]
    DIRECTION OUTPUT ;
    USE SIGNAL ;
    PORT
      LAYER met3 ;
        RECT -2.000 3515.160 0.300 3515.510 ;
    END
  END gpio_out[37]
  PIN gpio_out[38]
    DIRECTION OUTPUT ;
    USE SIGNAL ;
    PORT
      LAYER met3 ;
        RECT -2.000 3299.160 0.300 3299.510 ;
    END
  END gpio_out[38]
  PIN gpio_out[39]
    DIRECTION OUTPUT ;
    USE SIGNAL ;
    PORT
      LAYER met3 ;
        RECT -2.000 3083.160 0.300 3083.510 ;
    END
  END gpio_out[39]
  PIN gpio_out[3]
    DIRECTION OUTPUT ;
    USE SIGNAL ;
    PORT
      LAYER met3 ;
        RECT 6754.330 1026.120 6756.630 1026.470 ;
    END
  END gpio_out[3]
  PIN gpio_out[40]
    DIRECTION OUTPUT ;
    USE SIGNAL ;
    PORT
      LAYER met3 ;
        RECT -2.000 2867.160 0.300 2867.510 ;
    END
  END gpio_out[40]
  PIN gpio_out[41]
    DIRECTION OUTPUT ;
    USE SIGNAL ;
    PORT
      LAYER met3 ;
        RECT -2.000 2651.160 0.300 2651.510 ;
    END
  END gpio_out[41]
  PIN gpio_out[42]
    DIRECTION OUTPUT ;
    USE SIGNAL ;
    PORT
      LAYER met3 ;
        RECT -2.000 2435.160 0.300 2435.510 ;
    END
  END gpio_out[42]
  PIN gpio_out[43]
    DIRECTION OUTPUT ;
    USE SIGNAL ;
    PORT
      LAYER met3 ;
        RECT -2.000 1797.160 0.300 1797.510 ;
    END
  END gpio_out[43]
  PIN gpio_out[44]
    DIRECTION OUTPUT ;
    USE SIGNAL ;
    PORT
      LAYER met3 ;
        RECT -2.000 1581.160 0.300 1581.510 ;
    END
  END gpio_out[44]
  PIN gpio_out[45]
    DIRECTION OUTPUT ;
    USE SIGNAL ;
    PORT
      LAYER met3 ;
        RECT -2.000 1365.160 0.300 1365.510 ;
    END
  END gpio_out[45]
  PIN gpio_out[46]
    DIRECTION OUTPUT ;
    USE SIGNAL ;
    PORT
      LAYER met3 ;
        RECT -2.000 1149.160 0.300 1149.510 ;
    END
  END gpio_out[46]
  PIN gpio_out[47]
    DIRECTION OUTPUT ;
    USE SIGNAL ;
    PORT
      LAYER met3 ;
        RECT -2.000 933.160 0.300 933.510 ;
    END
  END gpio_out[47]
  PIN gpio_out[48]
    DIRECTION OUTPUT ;
    USE SIGNAL ;
    PORT
      LAYER met3 ;
        RECT -2.000 717.160 0.300 717.510 ;
    END
  END gpio_out[48]
  PIN gpio_out[49]
    DIRECTION OUTPUT ;
    USE SIGNAL ;
    PORT
      LAYER met2 ;
        RECT 781.150 -2.000 781.430 0.280 ;
    END
  END gpio_out[49]
  PIN gpio_out[4]
    DIRECTION OUTPUT ;
    USE SIGNAL ;
    PORT
      LAYER met3 ;
        RECT 6754.330 1251.120 6756.630 1251.470 ;
    END
  END gpio_out[4]
  PIN gpio_out[50]
    DIRECTION OUTPUT ;
    USE SIGNAL ;
    PORT
      LAYER met2 ;
        RECT 1324.150 -2.000 1324.430 0.280 ;
    END
  END gpio_out[50]
  PIN gpio_out[51]
    DIRECTION OUTPUT ;
    USE SIGNAL ;
    PORT
      LAYER met2 ;
        RECT 1598.150 -2.000 1598.430 0.280 ;
    END
  END gpio_out[51]
  PIN gpio_out[52]
    DIRECTION OUTPUT ;
    USE SIGNAL ;
    PORT
      LAYER met2 ;
        RECT 1872.150 -2.000 1872.430 0.280 ;
    END
  END gpio_out[52]
  PIN gpio_out[53]
    DIRECTION OUTPUT ;
    USE SIGNAL ;
    PORT
      LAYER met2 ;
        RECT 2146.150 -2.000 2146.430 0.280 ;
    END
  END gpio_out[53]
  PIN gpio_out[54]
    DIRECTION OUTPUT ;
    USE SIGNAL ;
    PORT
      LAYER met2 ;
        RECT 2420.150 -2.000 2420.430 0.280 ;
    END
  END gpio_out[54]
  PIN gpio_out[55]
    DIRECTION OUTPUT ;
    USE SIGNAL ;
    PORT
      LAYER met2 ;
        RECT 3234.630 -2.000 3234.910 0.280 ;
    END
  END gpio_out[55]
  PIN gpio_out[56]
    DIRECTION OUTPUT ;
    USE SIGNAL ;
    PORT
      LAYER met2 ;
        RECT 3508.630 -2.000 3508.910 0.280 ;
    END
  END gpio_out[56]
  PIN gpio_out[57]
    DIRECTION OUTPUT ;
    USE SIGNAL ;
    PORT
      LAYER met2 ;
        RECT 4369.150 -2.000 4369.430 0.280 ;
    END
  END gpio_out[57]
  PIN gpio_out[58]
    DIRECTION OUTPUT ;
    USE SIGNAL ;
    PORT
      LAYER met2 ;
        RECT 4912.150 -2.000 4912.430 0.280 ;
    END
  END gpio_out[58]
  PIN gpio_out[59]
    DIRECTION OUTPUT ;
    USE SIGNAL ;
    PORT
      LAYER met2 ;
        RECT 5186.150 -2.000 5186.430 0.280 ;
    END
  END gpio_out[59]
  PIN gpio_out[5]
    DIRECTION OUTPUT ;
    USE SIGNAL ;
    PORT
      LAYER met3 ;
        RECT 6754.330 1476.120 6756.630 1476.470 ;
    END
  END gpio_out[5]
  PIN gpio_out[60]
    DIRECTION OUTPUT ;
    USE SIGNAL ;
    PORT
      LAYER met2 ;
        RECT 5460.150 -2.000 5460.430 0.280 ;
    END
  END gpio_out[60]
  PIN gpio_out[61]
    DIRECTION OUTPUT ;
    USE SIGNAL ;
    PORT
      LAYER met2 ;
        RECT 5734.150 -2.000 5734.430 0.280 ;
    END
  END gpio_out[61]
  PIN gpio_out[62]
    DIRECTION OUTPUT ;
    USE SIGNAL ;
    PORT
      LAYER met2 ;
        RECT 6008.150 -2.000 6008.430 0.280 ;
    END
  END gpio_out[62]
  PIN gpio_out[6]
    DIRECTION OUTPUT ;
    USE SIGNAL ;
    PORT
      LAYER met3 ;
        RECT 6754.330 1702.120 6756.630 1702.470 ;
    END
  END gpio_out[6]
  PIN gpio_out[7]
    DIRECTION OUTPUT ;
    USE SIGNAL ;
    PORT
      LAYER met3 ;
        RECT 6754.330 2588.120 6756.630 2588.470 ;
    END
  END gpio_out[7]
  PIN gpio_out[8]
    DIRECTION OUTPUT ;
    USE SIGNAL ;
    PORT
      LAYER met3 ;
        RECT 6754.330 2814.120 6756.630 2814.470 ;
    END
  END gpio_out[8]
  PIN gpio_out[9]
    DIRECTION OUTPUT ;
    USE SIGNAL ;
    PORT
      LAYER met3 ;
        RECT 6754.330 3039.120 6756.630 3039.470 ;
    END
  END gpio_out[9]
  PIN gpio_slow_sel[0]
    DIRECTION OUTPUT ;
    USE SIGNAL ;
    PORT
      LAYER met3 ;
        RECT 6754.330 303.120 6756.630 303.470 ;
    END
  END gpio_slow_sel[0]
  PIN gpio_slow_sel[10]
    DIRECTION OUTPUT ;
    USE SIGNAL ;
    PORT
      LAYER met3 ;
        RECT 6754.330 3219.120 6756.630 3219.470 ;
    END
  END gpio_slow_sel[10]
  PIN gpio_slow_sel[11]
    DIRECTION OUTPUT ;
    USE SIGNAL ;
    PORT
      LAYER met3 ;
        RECT 6754.330 3444.120 6756.630 3444.470 ;
    END
  END gpio_slow_sel[11]
  PIN gpio_slow_sel[12]
    DIRECTION OUTPUT ;
    USE SIGNAL ;
    PORT
      LAYER met3 ;
        RECT 6754.330 3669.120 6756.630 3669.470 ;
    END
  END gpio_slow_sel[12]
  PIN gpio_slow_sel[13]
    DIRECTION OUTPUT ;
    USE SIGNAL ;
    PORT
      LAYER met3 ;
        RECT 6754.330 4115.120 6756.630 4115.470 ;
    END
  END gpio_slow_sel[13]
  PIN gpio_slow_sel[14]
    DIRECTION OUTPUT ;
    USE SIGNAL ;
    PORT
      LAYER met3 ;
        RECT 6754.330 4561.120 6756.630 4561.470 ;
    END
  END gpio_slow_sel[14]
  PIN gpio_slow_sel[15]
    DIRECTION OUTPUT ;
    USE SIGNAL ;
    PORT
      LAYER met2 ;
        RECT 6573.200 4766.350 6573.480 4768.630 ;
    END
  END gpio_slow_sel[15]
  PIN gpio_slow_sel[16]
    DIRECTION OUTPUT ;
    USE SIGNAL ;
    PORT
      LAYER met2 ;
        RECT 6064.200 4766.350 6064.480 4768.630 ;
    END
  END gpio_slow_sel[16]
  PIN gpio_slow_sel[17]
    DIRECTION OUTPUT ;
    USE SIGNAL ;
    PORT
      LAYER met2 ;
        RECT 5807.200 4766.350 5807.480 4768.630 ;
    END
  END gpio_slow_sel[17]
  PIN gpio_slow_sel[18]
    DIRECTION OUTPUT ;
    USE SIGNAL ;
    PORT
      LAYER met2 ;
        RECT 5362.200 4766.350 5362.480 4768.630 ;
    END
  END gpio_slow_sel[18]
  PIN gpio_slow_sel[19]
    DIRECTION OUTPUT ;
    USE SIGNAL ;
    PORT
      LAYER met2 ;
        RECT 4853.200 4766.350 4853.480 4768.630 ;
    END
  END gpio_slow_sel[19]
  PIN gpio_slow_sel[1]
    DIRECTION OUTPUT ;
    USE SIGNAL ;
    PORT
      LAYER met3 ;
        RECT 6754.330 529.120 6756.630 529.470 ;
    END
  END gpio_slow_sel[1]
  PIN gpio_slow_sel[20]
    DIRECTION OUTPUT ;
    USE SIGNAL ;
    PORT
      LAYER met2 ;
        RECT 4595.200 4766.350 4595.480 4768.630 ;
    END
  END gpio_slow_sel[20]
  PIN gpio_slow_sel[21]
    DIRECTION OUTPUT ;
    USE SIGNAL ;
    PORT
      LAYER met2 ;
        RECT 4338.200 4766.350 4338.480 4768.630 ;
    END
  END gpio_slow_sel[21]
  PIN gpio_slow_sel[22]
    DIRECTION OUTPUT ;
    USE SIGNAL ;
    PORT
      LAYER met2 ;
        RECT 4081.200 4766.350 4081.480 4768.630 ;
    END
  END gpio_slow_sel[22]
  PIN gpio_slow_sel[23]
    DIRECTION OUTPUT ;
    USE SIGNAL ;
    PORT
      LAYER met2 ;
        RECT 3824.200 4766.350 3824.480 4768.630 ;
    END
  END gpio_slow_sel[23]
  PIN gpio_slow_sel[24]
    DIRECTION OUTPUT ;
    USE SIGNAL ;
    PORT
      LAYER met2 ;
        RECT 3499.200 4766.350 3499.480 4768.630 ;
    END
  END gpio_slow_sel[24]
  PIN gpio_slow_sel[25]
    DIRECTION OUTPUT ;
    USE SIGNAL ;
    PORT
      LAYER met2 ;
        RECT 3242.200 4766.350 3242.480 4768.630 ;
    END
  END gpio_slow_sel[25]
  PIN gpio_slow_sel[26]
    DIRECTION OUTPUT ;
    USE SIGNAL ;
    PORT
      LAYER met2 ;
        RECT 2985.200 4766.350 2985.480 4768.630 ;
    END
  END gpio_slow_sel[26]
  PIN gpio_slow_sel[27]
    DIRECTION OUTPUT ;
    USE SIGNAL ;
    PORT
      LAYER met2 ;
        RECT 2476.200 4766.350 2476.480 4768.630 ;
    END
  END gpio_slow_sel[27]
  PIN gpio_slow_sel[28]
    DIRECTION OUTPUT ;
    USE SIGNAL ;
    PORT
      LAYER met2 ;
        RECT 2219.200 4766.350 2219.480 4768.630 ;
    END
  END gpio_slow_sel[28]
  PIN gpio_slow_sel[29]
    DIRECTION OUTPUT ;
    USE SIGNAL ;
    PORT
      LAYER met2 ;
        RECT 1774.200 4766.350 1774.480 4768.630 ;
    END
  END gpio_slow_sel[29]
  PIN gpio_slow_sel[2]
    DIRECTION OUTPUT ;
    USE SIGNAL ;
    PORT
      LAYER met3 ;
        RECT 6754.330 754.120 6756.630 754.470 ;
    END
  END gpio_slow_sel[2]
  PIN gpio_slow_sel[30]
    DIRECTION OUTPUT ;
    USE SIGNAL ;
    PORT
      LAYER met2 ;
        RECT 1265.200 4766.350 1265.480 4768.630 ;
    END
  END gpio_slow_sel[30]
  PIN gpio_slow_sel[31]
    DIRECTION OUTPUT ;
    USE SIGNAL ;
    PORT
      LAYER met2 ;
        RECT 1007.200 4766.350 1007.480 4768.630 ;
    END
  END gpio_slow_sel[31]
  PIN gpio_slow_sel[32]
    DIRECTION OUTPUT ;
    USE SIGNAL ;
    PORT
      LAYER met2 ;
        RECT 750.200 4766.350 750.480 4768.630 ;
    END
  END gpio_slow_sel[32]
  PIN gpio_slow_sel[33]
    DIRECTION OUTPUT ;
    USE SIGNAL ;
    PORT
      LAYER met2 ;
        RECT 493.200 4766.350 493.480 4768.630 ;
    END
  END gpio_slow_sel[33]
  PIN gpio_slow_sel[34]
    DIRECTION OUTPUT ;
    USE SIGNAL ;
    PORT
      LAYER met2 ;
        RECT 236.200 4766.350 236.480 4768.630 ;
    END
  END gpio_slow_sel[34]
  PIN gpio_slow_sel[35]
    DIRECTION OUTPUT ;
    USE SIGNAL ;
    PORT
      LAYER met3 ;
        RECT -2.000 4626.160 0.300 4626.510 ;
    END
  END gpio_slow_sel[35]
  PIN gpio_slow_sel[36]
    DIRECTION OUTPUT ;
    USE SIGNAL ;
    PORT
      LAYER met3 ;
        RECT -2.000 3777.160 0.300 3777.510 ;
    END
  END gpio_slow_sel[36]
  PIN gpio_slow_sel[37]
    DIRECTION OUTPUT ;
    USE SIGNAL ;
    PORT
      LAYER met3 ;
        RECT -2.000 3561.160 0.300 3561.510 ;
    END
  END gpio_slow_sel[37]
  PIN gpio_slow_sel[38]
    DIRECTION OUTPUT ;
    USE SIGNAL ;
    PORT
      LAYER met3 ;
        RECT -2.000 3345.160 0.300 3345.510 ;
    END
  END gpio_slow_sel[38]
  PIN gpio_slow_sel[39]
    DIRECTION OUTPUT ;
    USE SIGNAL ;
    PORT
      LAYER met3 ;
        RECT -2.000 3129.160 0.300 3129.510 ;
    END
  END gpio_slow_sel[39]
  PIN gpio_slow_sel[3]
    DIRECTION OUTPUT ;
    USE SIGNAL ;
    PORT
      LAYER met3 ;
        RECT 6754.330 980.120 6756.630 980.470 ;
    END
  END gpio_slow_sel[3]
  PIN gpio_slow_sel[40]
    DIRECTION OUTPUT ;
    USE SIGNAL ;
    PORT
      LAYER met3 ;
        RECT -2.000 2913.160 0.300 2913.510 ;
    END
  END gpio_slow_sel[40]
  PIN gpio_slow_sel[41]
    DIRECTION OUTPUT ;
    USE SIGNAL ;
    PORT
      LAYER met3 ;
        RECT -2.000 2697.160 0.300 2697.510 ;
    END
  END gpio_slow_sel[41]
  PIN gpio_slow_sel[42]
    DIRECTION OUTPUT ;
    USE SIGNAL ;
    PORT
      LAYER met3 ;
        RECT -2.000 2481.160 0.300 2481.510 ;
    END
  END gpio_slow_sel[42]
  PIN gpio_slow_sel[43]
    DIRECTION OUTPUT ;
    USE SIGNAL ;
    PORT
      LAYER met3 ;
        RECT -2.000 1843.160 0.300 1843.510 ;
    END
  END gpio_slow_sel[43]
  PIN gpio_slow_sel[44]
    DIRECTION OUTPUT ;
    USE SIGNAL ;
    PORT
      LAYER met3 ;
        RECT -2.000 1627.160 0.300 1627.510 ;
    END
  END gpio_slow_sel[44]
  PIN gpio_slow_sel[45]
    DIRECTION OUTPUT ;
    USE SIGNAL ;
    PORT
      LAYER met3 ;
        RECT -2.000 1411.160 0.300 1411.510 ;
    END
  END gpio_slow_sel[45]
  PIN gpio_slow_sel[46]
    DIRECTION OUTPUT ;
    USE SIGNAL ;
    PORT
      LAYER met3 ;
        RECT -2.000 1195.160 0.300 1195.510 ;
    END
  END gpio_slow_sel[46]
  PIN gpio_slow_sel[47]
    DIRECTION OUTPUT ;
    USE SIGNAL ;
    PORT
      LAYER met3 ;
        RECT -2.000 979.160 0.300 979.510 ;
    END
  END gpio_slow_sel[47]
  PIN gpio_slow_sel[48]
    DIRECTION OUTPUT ;
    USE SIGNAL ;
    PORT
      LAYER met3 ;
        RECT -2.000 763.160 0.300 763.510 ;
    END
  END gpio_slow_sel[48]
  PIN gpio_slow_sel[49]
    DIRECTION OUTPUT ;
    USE SIGNAL ;
    PORT
      LAYER met2 ;
        RECT 735.150 -2.000 735.430 0.280 ;
    END
  END gpio_slow_sel[49]
  PIN gpio_slow_sel[4]
    DIRECTION OUTPUT ;
    USE SIGNAL ;
    PORT
      LAYER met3 ;
        RECT 6754.330 1205.120 6756.630 1205.470 ;
    END
  END gpio_slow_sel[4]
  PIN gpio_slow_sel[50]
    DIRECTION OUTPUT ;
    USE SIGNAL ;
    PORT
      LAYER met2 ;
        RECT 1278.150 -2.000 1278.430 0.280 ;
    END
  END gpio_slow_sel[50]
  PIN gpio_slow_sel[51]
    DIRECTION OUTPUT ;
    USE SIGNAL ;
    PORT
      LAYER met2 ;
        RECT 1552.150 -2.000 1552.430 0.280 ;
    END
  END gpio_slow_sel[51]
  PIN gpio_slow_sel[52]
    DIRECTION OUTPUT ;
    USE SIGNAL ;
    PORT
      LAYER met2 ;
        RECT 1826.150 -2.000 1826.430 0.280 ;
    END
  END gpio_slow_sel[52]
  PIN gpio_slow_sel[53]
    DIRECTION OUTPUT ;
    USE SIGNAL ;
    PORT
      LAYER met2 ;
        RECT 2100.150 -2.000 2100.430 0.280 ;
    END
  END gpio_slow_sel[53]
  PIN gpio_slow_sel[54]
    DIRECTION OUTPUT ;
    USE SIGNAL ;
    PORT
      LAYER met2 ;
        RECT 2374.150 -2.000 2374.430 0.280 ;
    END
  END gpio_slow_sel[54]
  PIN gpio_slow_sel[55]
    DIRECTION OUTPUT ;
    USE SIGNAL ;
    PORT
      LAYER met2 ;
        RECT 3188.630 -2.000 3188.910 0.280 ;
    END
  END gpio_slow_sel[55]
  PIN gpio_slow_sel[56]
    DIRECTION OUTPUT ;
    USE SIGNAL ;
    PORT
      LAYER met2 ;
        RECT 3462.630 -2.000 3462.910 0.280 ;
    END
  END gpio_slow_sel[56]
  PIN gpio_slow_sel[57]
    DIRECTION OUTPUT ;
    USE SIGNAL ;
    PORT
      LAYER met2 ;
        RECT 4323.150 -2.000 4323.430 0.280 ;
    END
  END gpio_slow_sel[57]
  PIN gpio_slow_sel[58]
    DIRECTION OUTPUT ;
    USE SIGNAL ;
    PORT
      LAYER met2 ;
        RECT 4866.150 -2.000 4866.430 0.280 ;
    END
  END gpio_slow_sel[58]
  PIN gpio_slow_sel[59]
    DIRECTION OUTPUT ;
    USE SIGNAL ;
    PORT
      LAYER met2 ;
        RECT 5140.150 -2.000 5140.430 0.280 ;
    END
  END gpio_slow_sel[59]
  PIN gpio_slow_sel[5]
    DIRECTION OUTPUT ;
    USE SIGNAL ;
    PORT
      LAYER met3 ;
        RECT 6754.330 1430.120 6756.630 1430.470 ;
    END
  END gpio_slow_sel[5]
  PIN gpio_slow_sel[60]
    DIRECTION OUTPUT ;
    USE SIGNAL ;
    PORT
      LAYER met2 ;
        RECT 5414.150 -2.000 5414.430 0.280 ;
    END
  END gpio_slow_sel[60]
  PIN gpio_slow_sel[61]
    DIRECTION OUTPUT ;
    USE SIGNAL ;
    PORT
      LAYER met2 ;
        RECT 5688.150 -2.000 5688.430 0.280 ;
    END
  END gpio_slow_sel[61]
  PIN gpio_slow_sel[62]
    DIRECTION OUTPUT ;
    USE SIGNAL ;
    PORT
      LAYER met2 ;
        RECT 5962.150 -2.000 5962.430 0.280 ;
    END
  END gpio_slow_sel[62]
  PIN gpio_slow_sel[6]
    DIRECTION OUTPUT ;
    USE SIGNAL ;
    PORT
      LAYER met3 ;
        RECT 6754.330 1656.120 6756.630 1656.470 ;
    END
  END gpio_slow_sel[6]
  PIN gpio_slow_sel[7]
    DIRECTION OUTPUT ;
    USE SIGNAL ;
    PORT
      LAYER met3 ;
        RECT 6754.330 2542.120 6756.630 2542.470 ;
    END
  END gpio_slow_sel[7]
  PIN gpio_slow_sel[8]
    DIRECTION OUTPUT ;
    USE SIGNAL ;
    PORT
      LAYER met3 ;
        RECT 6754.330 2768.120 6756.630 2768.470 ;
    END
  END gpio_slow_sel[8]
  PIN gpio_slow_sel[9]
    DIRECTION OUTPUT ;
    USE SIGNAL ;
    PORT
      LAYER met3 ;
        RECT 6754.330 2993.120 6756.630 2993.470 ;
    END
  END gpio_slow_sel[9]
  PIN gpio_vtrip_sel[0]
    DIRECTION OUTPUT ;
    USE SIGNAL ;
    PORT
      LAYER met3 ;
        RECT 6754.330 358.320 6756.630 358.670 ;
    END
  END gpio_vtrip_sel[0]
  PIN gpio_vtrip_sel[10]
    DIRECTION OUTPUT ;
    USE SIGNAL ;
    PORT
      LAYER met3 ;
        RECT 6754.330 3274.320 6756.630 3274.670 ;
    END
  END gpio_vtrip_sel[10]
  PIN gpio_vtrip_sel[11]
    DIRECTION OUTPUT ;
    USE SIGNAL ;
    PORT
      LAYER met3 ;
        RECT 6754.330 3499.320 6756.630 3499.670 ;
    END
  END gpio_vtrip_sel[11]
  PIN gpio_vtrip_sel[12]
    DIRECTION OUTPUT ;
    USE SIGNAL ;
    PORT
      LAYER met3 ;
        RECT 6754.330 3724.320 6756.630 3724.670 ;
    END
  END gpio_vtrip_sel[12]
  PIN gpio_vtrip_sel[13]
    DIRECTION OUTPUT ;
    USE SIGNAL ;
    PORT
      LAYER met3 ;
        RECT 6754.330 4170.320 6756.630 4170.670 ;
    END
  END gpio_vtrip_sel[13]
  PIN gpio_vtrip_sel[14]
    DIRECTION OUTPUT ;
    USE SIGNAL ;
    PORT
      LAYER met3 ;
        RECT 6754.330 4616.320 6756.630 4616.670 ;
    END
  END gpio_vtrip_sel[14]
  PIN gpio_vtrip_sel[15]
    DIRECTION OUTPUT ;
    USE SIGNAL ;
    PORT
      LAYER met2 ;
        RECT 6518.000 4766.350 6518.280 4768.630 ;
    END
  END gpio_vtrip_sel[15]
  PIN gpio_vtrip_sel[16]
    DIRECTION OUTPUT ;
    USE SIGNAL ;
    PORT
      LAYER met2 ;
        RECT 6009.000 4766.350 6009.280 4768.630 ;
    END
  END gpio_vtrip_sel[16]
  PIN gpio_vtrip_sel[17]
    DIRECTION OUTPUT ;
    USE SIGNAL ;
    PORT
      LAYER met2 ;
        RECT 5752.000 4766.350 5752.280 4768.630 ;
    END
  END gpio_vtrip_sel[17]
  PIN gpio_vtrip_sel[18]
    DIRECTION OUTPUT ;
    USE SIGNAL ;
    PORT
      LAYER met2 ;
        RECT 5307.000 4766.350 5307.280 4768.630 ;
    END
  END gpio_vtrip_sel[18]
  PIN gpio_vtrip_sel[19]
    DIRECTION OUTPUT ;
    USE SIGNAL ;
    PORT
      LAYER met2 ;
        RECT 4798.000 4766.350 4798.280 4768.630 ;
    END
  END gpio_vtrip_sel[19]
  PIN gpio_vtrip_sel[1]
    DIRECTION OUTPUT ;
    USE SIGNAL ;
    PORT
      LAYER met3 ;
        RECT 6754.330 584.320 6756.630 584.670 ;
    END
  END gpio_vtrip_sel[1]
  PIN gpio_vtrip_sel[20]
    DIRECTION OUTPUT ;
    USE SIGNAL ;
    PORT
      LAYER met2 ;
        RECT 4540.000 4766.350 4540.280 4768.630 ;
    END
  END gpio_vtrip_sel[20]
  PIN gpio_vtrip_sel[21]
    DIRECTION OUTPUT ;
    USE SIGNAL ;
    PORT
      LAYER met2 ;
        RECT 4283.000 4766.350 4283.280 4768.630 ;
    END
  END gpio_vtrip_sel[21]
  PIN gpio_vtrip_sel[22]
    DIRECTION OUTPUT ;
    USE SIGNAL ;
    PORT
      LAYER met2 ;
        RECT 4026.000 4766.350 4026.280 4768.630 ;
    END
  END gpio_vtrip_sel[22]
  PIN gpio_vtrip_sel[23]
    DIRECTION OUTPUT ;
    USE SIGNAL ;
    PORT
      LAYER met2 ;
        RECT 3769.000 4766.350 3769.280 4768.630 ;
    END
  END gpio_vtrip_sel[23]
  PIN gpio_vtrip_sel[24]
    DIRECTION OUTPUT ;
    USE SIGNAL ;
    PORT
      LAYER met2 ;
        RECT 3444.000 4766.350 3444.280 4768.630 ;
    END
  END gpio_vtrip_sel[24]
  PIN gpio_vtrip_sel[25]
    DIRECTION OUTPUT ;
    USE SIGNAL ;
    PORT
      LAYER met2 ;
        RECT 3187.000 4766.350 3187.280 4768.630 ;
    END
  END gpio_vtrip_sel[25]
  PIN gpio_vtrip_sel[26]
    DIRECTION OUTPUT ;
    USE SIGNAL ;
    PORT
      LAYER met2 ;
        RECT 2930.000 4766.350 2930.280 4768.630 ;
    END
  END gpio_vtrip_sel[26]
  PIN gpio_vtrip_sel[27]
    DIRECTION OUTPUT ;
    USE SIGNAL ;
    PORT
      LAYER met2 ;
        RECT 2421.000 4766.350 2421.280 4768.630 ;
    END
  END gpio_vtrip_sel[27]
  PIN gpio_vtrip_sel[28]
    DIRECTION OUTPUT ;
    USE SIGNAL ;
    PORT
      LAYER met2 ;
        RECT 2164.000 4766.350 2164.280 4768.630 ;
    END
  END gpio_vtrip_sel[28]
  PIN gpio_vtrip_sel[29]
    DIRECTION OUTPUT ;
    USE SIGNAL ;
    PORT
      LAYER met2 ;
        RECT 1719.000 4766.350 1719.280 4768.630 ;
    END
  END gpio_vtrip_sel[29]
  PIN gpio_vtrip_sel[2]
    DIRECTION OUTPUT ;
    USE SIGNAL ;
    PORT
      LAYER met3 ;
        RECT 6754.330 809.320 6756.630 809.670 ;
    END
  END gpio_vtrip_sel[2]
  PIN gpio_vtrip_sel[30]
    DIRECTION OUTPUT ;
    USE SIGNAL ;
    PORT
      LAYER met2 ;
        RECT 1210.000 4766.350 1210.280 4768.630 ;
    END
  END gpio_vtrip_sel[30]
  PIN gpio_vtrip_sel[31]
    DIRECTION OUTPUT ;
    USE SIGNAL ;
    PORT
      LAYER met2 ;
        RECT 952.000 4766.350 952.280 4768.630 ;
    END
  END gpio_vtrip_sel[31]
  PIN gpio_vtrip_sel[32]
    DIRECTION OUTPUT ;
    USE SIGNAL ;
    PORT
      LAYER met2 ;
        RECT 695.000 4766.350 695.280 4768.630 ;
    END
  END gpio_vtrip_sel[32]
  PIN gpio_vtrip_sel[33]
    DIRECTION OUTPUT ;
    USE SIGNAL ;
    PORT
      LAYER met2 ;
        RECT 438.000 4766.350 438.280 4768.630 ;
    END
  END gpio_vtrip_sel[33]
  PIN gpio_vtrip_sel[34]
    DIRECTION OUTPUT ;
    USE SIGNAL ;
    PORT
      LAYER met2 ;
        RECT 181.000 4766.350 181.280 4768.630 ;
    END
  END gpio_vtrip_sel[34]
  PIN gpio_vtrip_sel[35]
    DIRECTION OUTPUT ;
    USE SIGNAL ;
    PORT
      LAYER met3 ;
        RECT -2.000 4570.960 0.300 4571.310 ;
    END
  END gpio_vtrip_sel[35]
  PIN gpio_vtrip_sel[36]
    DIRECTION OUTPUT ;
    USE SIGNAL ;
    PORT
      LAYER met3 ;
        RECT -2.000 3721.960 0.300 3722.310 ;
    END
  END gpio_vtrip_sel[36]
  PIN gpio_vtrip_sel[37]
    DIRECTION OUTPUT ;
    USE SIGNAL ;
    PORT
      LAYER met3 ;
        RECT -2.000 3505.960 0.300 3506.310 ;
    END
  END gpio_vtrip_sel[37]
  PIN gpio_vtrip_sel[38]
    DIRECTION OUTPUT ;
    USE SIGNAL ;
    PORT
      LAYER met3 ;
        RECT -2.000 3289.960 0.300 3290.310 ;
    END
  END gpio_vtrip_sel[38]
  PIN gpio_vtrip_sel[39]
    DIRECTION OUTPUT ;
    USE SIGNAL ;
    PORT
      LAYER met3 ;
        RECT -2.000 3073.960 0.300 3074.310 ;
    END
  END gpio_vtrip_sel[39]
  PIN gpio_vtrip_sel[3]
    DIRECTION OUTPUT ;
    USE SIGNAL ;
    PORT
      LAYER met3 ;
        RECT 6754.330 1035.320 6756.630 1035.670 ;
    END
  END gpio_vtrip_sel[3]
  PIN gpio_vtrip_sel[40]
    DIRECTION OUTPUT ;
    USE SIGNAL ;
    PORT
      LAYER met3 ;
        RECT -2.000 2857.960 0.300 2858.310 ;
    END
  END gpio_vtrip_sel[40]
  PIN gpio_vtrip_sel[41]
    DIRECTION OUTPUT ;
    USE SIGNAL ;
    PORT
      LAYER met3 ;
        RECT -2.000 2641.960 0.300 2642.310 ;
    END
  END gpio_vtrip_sel[41]
  PIN gpio_vtrip_sel[42]
    DIRECTION OUTPUT ;
    USE SIGNAL ;
    PORT
      LAYER met3 ;
        RECT -2.000 2425.960 0.300 2426.310 ;
    END
  END gpio_vtrip_sel[42]
  PIN gpio_vtrip_sel[43]
    DIRECTION OUTPUT ;
    USE SIGNAL ;
    PORT
      LAYER met3 ;
        RECT -2.000 1787.960 0.300 1788.310 ;
    END
  END gpio_vtrip_sel[43]
  PIN gpio_vtrip_sel[44]
    DIRECTION OUTPUT ;
    USE SIGNAL ;
    PORT
      LAYER met3 ;
        RECT -2.000 1571.960 0.300 1572.310 ;
    END
  END gpio_vtrip_sel[44]
  PIN gpio_vtrip_sel[45]
    DIRECTION OUTPUT ;
    USE SIGNAL ;
    PORT
      LAYER met3 ;
        RECT -2.000 1355.960 0.300 1356.310 ;
    END
  END gpio_vtrip_sel[45]
  PIN gpio_vtrip_sel[46]
    DIRECTION OUTPUT ;
    USE SIGNAL ;
    PORT
      LAYER met3 ;
        RECT -2.000 1139.960 0.300 1140.310 ;
    END
  END gpio_vtrip_sel[46]
  PIN gpio_vtrip_sel[47]
    DIRECTION OUTPUT ;
    USE SIGNAL ;
    PORT
      LAYER met3 ;
        RECT -2.000 923.960 0.300 924.310 ;
    END
  END gpio_vtrip_sel[47]
  PIN gpio_vtrip_sel[48]
    DIRECTION OUTPUT ;
    USE SIGNAL ;
    PORT
      LAYER met3 ;
        RECT -2.000 707.960 0.300 708.310 ;
    END
  END gpio_vtrip_sel[48]
  PIN gpio_vtrip_sel[49]
    DIRECTION OUTPUT ;
    USE SIGNAL ;
    PORT
      LAYER met2 ;
        RECT 790.350 -2.000 790.630 0.280 ;
    END
  END gpio_vtrip_sel[49]
  PIN gpio_vtrip_sel[4]
    DIRECTION OUTPUT ;
    USE SIGNAL ;
    PORT
      LAYER met3 ;
        RECT 6754.330 1260.320 6756.630 1260.670 ;
    END
  END gpio_vtrip_sel[4]
  PIN gpio_vtrip_sel[50]
    DIRECTION OUTPUT ;
    USE SIGNAL ;
    PORT
      LAYER met2 ;
        RECT 1333.350 -2.000 1333.630 0.280 ;
    END
  END gpio_vtrip_sel[50]
  PIN gpio_vtrip_sel[51]
    DIRECTION OUTPUT ;
    USE SIGNAL ;
    PORT
      LAYER met2 ;
        RECT 1607.350 -2.000 1607.630 0.280 ;
    END
  END gpio_vtrip_sel[51]
  PIN gpio_vtrip_sel[52]
    DIRECTION OUTPUT ;
    USE SIGNAL ;
    PORT
      LAYER met2 ;
        RECT 1881.350 -2.000 1881.630 0.280 ;
    END
  END gpio_vtrip_sel[52]
  PIN gpio_vtrip_sel[53]
    DIRECTION OUTPUT ;
    USE SIGNAL ;
    PORT
      LAYER met2 ;
        RECT 2155.350 -2.000 2155.630 0.280 ;
    END
  END gpio_vtrip_sel[53]
  PIN gpio_vtrip_sel[54]
    DIRECTION OUTPUT ;
    USE SIGNAL ;
    PORT
      LAYER met2 ;
        RECT 2429.350 -2.000 2429.630 0.280 ;
    END
  END gpio_vtrip_sel[54]
  PIN gpio_vtrip_sel[55]
    DIRECTION OUTPUT ;
    USE SIGNAL ;
    PORT
      LAYER met2 ;
        RECT 3243.830 -2.000 3244.110 0.280 ;
    END
  END gpio_vtrip_sel[55]
  PIN gpio_vtrip_sel[56]
    DIRECTION OUTPUT ;
    USE SIGNAL ;
    PORT
      LAYER met2 ;
        RECT 3517.830 -2.000 3518.110 0.280 ;
    END
  END gpio_vtrip_sel[56]
  PIN gpio_vtrip_sel[57]
    DIRECTION OUTPUT ;
    USE SIGNAL ;
    PORT
      LAYER met2 ;
        RECT 4378.350 -2.000 4378.630 0.280 ;
    END
  END gpio_vtrip_sel[57]
  PIN gpio_vtrip_sel[58]
    DIRECTION OUTPUT ;
    USE SIGNAL ;
    PORT
      LAYER met2 ;
        RECT 4921.350 -2.000 4921.630 0.280 ;
    END
  END gpio_vtrip_sel[58]
  PIN gpio_vtrip_sel[59]
    DIRECTION OUTPUT ;
    USE SIGNAL ;
    PORT
      LAYER met2 ;
        RECT 5195.350 -2.000 5195.630 0.280 ;
    END
  END gpio_vtrip_sel[59]
  PIN gpio_vtrip_sel[5]
    DIRECTION OUTPUT ;
    USE SIGNAL ;
    PORT
      LAYER met3 ;
        RECT 6754.330 1485.320 6756.630 1485.670 ;
    END
  END gpio_vtrip_sel[5]
  PIN gpio_vtrip_sel[60]
    DIRECTION OUTPUT ;
    USE SIGNAL ;
    PORT
      LAYER met2 ;
        RECT 5469.350 -2.000 5469.630 0.280 ;
    END
  END gpio_vtrip_sel[60]
  PIN gpio_vtrip_sel[61]
    DIRECTION OUTPUT ;
    USE SIGNAL ;
    PORT
      LAYER met2 ;
        RECT 5743.350 -2.000 5743.630 0.280 ;
    END
  END gpio_vtrip_sel[61]
  PIN gpio_vtrip_sel[62]
    DIRECTION OUTPUT ;
    USE SIGNAL ;
    PORT
      LAYER met2 ;
        RECT 6017.350 -2.000 6017.630 0.280 ;
    END
  END gpio_vtrip_sel[62]
  PIN gpio_vtrip_sel[6]
    DIRECTION OUTPUT ;
    USE SIGNAL ;
    PORT
      LAYER met3 ;
        RECT 6754.330 1711.320 6756.630 1711.670 ;
    END
  END gpio_vtrip_sel[6]
  PIN gpio_vtrip_sel[7]
    DIRECTION OUTPUT ;
    USE SIGNAL ;
    PORT
      LAYER met3 ;
        RECT 6754.330 2597.320 6756.630 2597.670 ;
    END
  END gpio_vtrip_sel[7]
  PIN gpio_vtrip_sel[8]
    DIRECTION OUTPUT ;
    USE SIGNAL ;
    PORT
      LAYER met3 ;
        RECT 6754.330 2823.320 6756.630 2823.670 ;
    END
  END gpio_vtrip_sel[8]
  PIN gpio_vtrip_sel[9]
    DIRECTION OUTPUT ;
    USE SIGNAL ;
    PORT
      LAYER met3 ;
        RECT 6754.330 3048.320 6756.630 3048.670 ;
    END
  END gpio_vtrip_sel[9]
  PIN mask_rev[0]
    DIRECTION INPUT ;
    USE SIGNAL ;
    PORT
      LAYER met2 ;
        RECT 6613.410 -2.000 6613.670 0.280 ;
    END
  END mask_rev[0]
  PIN mask_rev[10]
    DIRECTION INPUT ;
    USE SIGNAL ;
    PORT
      LAYER met2 ;
        RECT 6624.610 -2.000 6624.870 0.280 ;
    END
  END mask_rev[10]
  PIN mask_rev[11]
    DIRECTION INPUT ;
    USE SIGNAL ;
    PORT
      LAYER met2 ;
        RECT 6625.730 -2.000 6625.990 0.280 ;
    END
  END mask_rev[11]
  PIN mask_rev[12]
    DIRECTION INPUT ;
    USE SIGNAL ;
    PORT
      LAYER met2 ;
        RECT 6626.850 -2.000 6627.110 0.280 ;
    END
  END mask_rev[12]
  PIN mask_rev[13]
    DIRECTION INPUT ;
    USE SIGNAL ;
    PORT
      LAYER met2 ;
        RECT 6627.970 -2.000 6628.230 0.280 ;
    END
  END mask_rev[13]
  PIN mask_rev[14]
    DIRECTION INPUT ;
    USE SIGNAL ;
    PORT
      LAYER met2 ;
        RECT 6629.090 -2.000 6629.350 0.280 ;
    END
  END mask_rev[14]
  PIN mask_rev[15]
    DIRECTION INPUT ;
    USE SIGNAL ;
    PORT
      LAYER met2 ;
        RECT 6630.210 -2.000 6630.470 0.280 ;
    END
  END mask_rev[15]
  PIN mask_rev[16]
    DIRECTION INPUT ;
    USE SIGNAL ;
    PORT
      LAYER met2 ;
        RECT 6631.330 -2.000 6631.590 0.280 ;
    END
  END mask_rev[16]
  PIN mask_rev[17]
    DIRECTION INPUT ;
    USE SIGNAL ;
    PORT
      LAYER met2 ;
        RECT 6632.450 -2.000 6632.710 0.280 ;
    END
  END mask_rev[17]
  PIN mask_rev[18]
    DIRECTION INPUT ;
    USE SIGNAL ;
    PORT
      LAYER met2 ;
        RECT 6633.570 -2.000 6633.830 0.280 ;
    END
  END mask_rev[18]
  PIN mask_rev[19]
    DIRECTION INPUT ;
    USE SIGNAL ;
    PORT
      LAYER met2 ;
        RECT 6634.690 -2.000 6634.950 0.280 ;
    END
  END mask_rev[19]
  PIN mask_rev[1]
    DIRECTION INPUT ;
    USE SIGNAL ;
    PORT
      LAYER met2 ;
        RECT 6614.530 -2.000 6614.790 0.280 ;
    END
  END mask_rev[1]
  PIN mask_rev[20]
    DIRECTION INPUT ;
    USE SIGNAL ;
    PORT
      LAYER met2 ;
        RECT 6635.810 -2.000 6636.070 0.280 ;
    END
  END mask_rev[20]
  PIN mask_rev[21]
    DIRECTION INPUT ;
    USE SIGNAL ;
    PORT
      LAYER met2 ;
        RECT 6636.930 -2.000 6637.190 0.280 ;
    END
  END mask_rev[21]
  PIN mask_rev[22]
    DIRECTION INPUT ;
    USE SIGNAL ;
    PORT
      LAYER met2 ;
        RECT 6638.050 -2.000 6638.310 0.280 ;
    END
  END mask_rev[22]
  PIN mask_rev[23]
    DIRECTION INPUT ;
    USE SIGNAL ;
    PORT
      LAYER met2 ;
        RECT 6639.170 -2.000 6639.430 0.280 ;
    END
  END mask_rev[23]
  PIN mask_rev[24]
    DIRECTION INPUT ;
    USE SIGNAL ;
    PORT
      LAYER met2 ;
        RECT 6640.290 -2.000 6640.550 0.280 ;
    END
  END mask_rev[24]
  PIN mask_rev[25]
    DIRECTION INPUT ;
    USE SIGNAL ;
    PORT
      LAYER met2 ;
        RECT 6641.410 -2.000 6641.670 0.280 ;
    END
  END mask_rev[25]
  PIN mask_rev[26]
    DIRECTION INPUT ;
    USE SIGNAL ;
    PORT
      LAYER met2 ;
        RECT 6642.530 -2.000 6642.790 0.280 ;
    END
  END mask_rev[26]
  PIN mask_rev[27]
    DIRECTION INPUT ;
    USE SIGNAL ;
    PORT
      LAYER met2 ;
        RECT 6643.650 -2.000 6643.910 0.280 ;
    END
  END mask_rev[27]
  PIN mask_rev[28]
    DIRECTION INPUT ;
    USE SIGNAL ;
    PORT
      LAYER met2 ;
        RECT 6644.770 -2.000 6645.030 0.280 ;
    END
  END mask_rev[28]
  PIN mask_rev[29]
    DIRECTION INPUT ;
    USE SIGNAL ;
    PORT
      LAYER met2 ;
        RECT 6645.890 -2.000 6646.150 0.280 ;
    END
  END mask_rev[29]
  PIN mask_rev[2]
    DIRECTION INPUT ;
    USE SIGNAL ;
    PORT
      LAYER met2 ;
        RECT 6615.650 -2.000 6615.910 0.280 ;
    END
  END mask_rev[2]
  PIN mask_rev[30]
    DIRECTION INPUT ;
    USE SIGNAL ;
    PORT
      LAYER met2 ;
        RECT 6647.010 -2.000 6647.270 0.280 ;
    END
  END mask_rev[30]
  PIN mask_rev[31]
    DIRECTION INPUT ;
    USE SIGNAL ;
    PORT
      LAYER met2 ;
        RECT 6648.130 -2.000 6648.390 0.280 ;
    END
  END mask_rev[31]
  PIN mask_rev[3]
    DIRECTION INPUT ;
    USE SIGNAL ;
    PORT
      LAYER met2 ;
        RECT 6616.770 -2.000 6617.030 0.280 ;
    END
  END mask_rev[3]
  PIN mask_rev[4]
    DIRECTION INPUT ;
    USE SIGNAL ;
    PORT
      LAYER met2 ;
        RECT 6617.890 -2.000 6618.150 0.280 ;
    END
  END mask_rev[4]
  PIN mask_rev[5]
    DIRECTION INPUT ;
    USE SIGNAL ;
    PORT
      LAYER met2 ;
        RECT 6619.010 -2.000 6619.270 0.280 ;
    END
  END mask_rev[5]
  PIN mask_rev[6]
    DIRECTION INPUT ;
    USE SIGNAL ;
    PORT
      LAYER met2 ;
        RECT 6620.130 -2.000 6620.390 0.280 ;
    END
  END mask_rev[6]
  PIN mask_rev[7]
    DIRECTION INPUT ;
    USE SIGNAL ;
    PORT
      LAYER met2 ;
        RECT 6621.250 -2.000 6621.510 0.280 ;
    END
  END mask_rev[7]
  PIN mask_rev[8]
    DIRECTION INPUT ;
    USE SIGNAL ;
    PORT
      LAYER met2 ;
        RECT 6622.370 -2.000 6622.630 0.280 ;
    END
  END mask_rev[8]
  PIN mask_rev[9]
    DIRECTION INPUT ;
    USE SIGNAL ;
    PORT
      LAYER met2 ;
        RECT 6623.490 -2.000 6623.750 0.280 ;
    END
  END mask_rev[9]
  PIN por_l
    DIRECTION INPUT ;
    USE SIGNAL ;
    PORT
      LAYER met3 ;
        RECT -2.000 528.180 0.300 528.530 ;
    END
  END por_l
  PIN porb_h
    DIRECTION INPUT ;
    USE SIGNAL ;
    PORT
      LAYER met3 ;
        RECT -2.000 527.055 0.300 527.405 ;
    END
  END porb_h
  PIN porb_l
    DIRECTION INPUT ;
    USE SIGNAL ;
    PORT
      LAYER met3 ;
        RECT -2.000 529.295 0.300 529.645 ;
    END
  END porb_l
  PIN resetb_h
    DIRECTION INPUT ;
    USE SIGNAL ;
    PORT
      LAYER met2 ;
        RECT 497.880 -2.000 498.160 0.280 ;
    END
  END resetb_h
  PIN resetb_l
    DIRECTION INPUT ;
    USE SIGNAL ;
    PORT
      LAYER met2 ;
        RECT 550.820 -2.000 551.100 0.280 ;
    END
  END resetb_l
  PIN vccd
    DIRECTION INOUT ;
    USE POWER ;
    PORT
      LAYER met3 ;
        RECT -2.000 129.810 0.300 153.810 ;
    END
    PORT
      LAYER met3 ;
        RECT -2.000 180.070 0.300 204.020 ;
    END
  END vccd
  PIN vccd1
    DIRECTION INOUT ;
    USE POWER ;
    PORT
      LAYER met3 ;
        RECT 6754.330 4327.610 6756.630 4351.560 ;
    END
    PORT
      LAYER met3 ;
        RECT 6754.330 4377.810 6756.630 4401.810 ;
    END
    PORT
      LAYER met3 ;
        RECT 6754.330 2114.050 6756.630 2137.360 ;
    END
  END vccd1
  PIN vccd2
    DIRECTION INOUT ;
    USE POWER ;
    PORT
      LAYER met3 ;
        RECT -2.000 4349.820 0.300 4373.820 ;
    END
    PORT
      LAYER met3 ;
        RECT -2.000 4400.070 0.300 4424.020 ;
    END
    PORT
      LAYER met3 ;
        RECT -2.000 2019.310 0.300 2042.570 ;
    END
  END vccd2
  PIN vdda
    DIRECTION INOUT ;
    USE POWER ;
    PORT
      LAYER met3 ;
        RECT 6492.030 -2.000 6515.930 0.300 ;
    END
    PORT
      LAYER met3 ;
        RECT 6541.920 -2.000 6565.820 0.300 ;
    END
    PORT
      LAYER met3 ;
        RECT 2904.030 -2.000 2927.930 0.300 ;
    END
    PORT
      LAYER met3 ;
        RECT 2953.920 -2.000 2977.820 0.300 ;
    END
  END vdda
  PIN vdda1
    DIRECTION INOUT ;
    USE POWER ;
    PORT
      LAYER met3 ;
        RECT 6754.330 3882.030 6756.630 3905.930 ;
    END
    PORT
      LAYER met3 ;
        RECT 6754.330 3931.920 6756.630 3955.820 ;
    END
    PORT
      LAYER met3 ;
        RECT 6754.330 2309.020 6756.630 2332.920 ;
    END
    PORT
      LAYER met3 ;
        RECT 6754.330 2358.920 6756.630 2382.820 ;
    END
  END vdda1
  PIN vdda2
    DIRECTION INOUT ;
    USE POWER ;
    PORT
      LAYER met3 ;
        RECT -2.000 2254.700 0.300 2278.600 ;
    END
    PORT
      LAYER met3 ;
        RECT -2.000 2204.810 0.300 2228.710 ;
    END
  END vdda2
  PIN vddio
    DIRECTION INOUT ;
    USE POWER ;
    PORT
      LAYER met3 ;
        RECT -2.000 4188.710 0.300 4212.610 ;
    END
    PORT
      LAYER met3 ;
        RECT -2.000 4138.810 0.300 4162.710 ;
    END
    PORT
      LAYER met3 ;
        RECT -2.000 390.700 0.300 414.600 ;
    END
    PORT
      LAYER met3 ;
        RECT -2.000 340.810 0.300 364.710 ;
    END
  END vddio
  PIN vssa
    DIRECTION INOUT ;
    USE GROUND ;
    PORT
      LAYER met3 ;
        RECT 3772.030 -2.000 3795.930 0.300 ;
    END
    PORT
      LAYER met3 ;
        RECT 3821.920 -2.000 3845.820 0.300 ;
    END
    PORT
      LAYER met3 ;
        RECT 184.030 -2.000 207.930 0.300 ;
    END
    PORT
      LAYER met3 ;
        RECT 233.920 -2.000 257.820 0.300 ;
    END
  END vssa
  PIN vssa1
    DIRECTION INOUT ;
    USE GROUND ;
    PORT
      LAYER met3 ;
        RECT 6305.710 4766.330 6329.610 4768.630 ;
    END
    PORT
      LAYER met3 ;
        RECT 6255.810 4766.330 6279.710 4768.630 ;
    END
    PORT
      LAYER met3 ;
        RECT 2717.710 4766.330 2741.610 4768.630 ;
    END
    PORT
      LAYER met3 ;
        RECT 2667.810 4766.330 2691.710 4768.630 ;
    END
    PORT
      LAYER met3 ;
        RECT 6754.330 1868.030 6756.630 1891.930 ;
    END
    PORT
      LAYER met3 ;
        RECT 6754.330 1917.920 6756.630 1941.820 ;
    END
  END vssa1
  PIN vssa2
    DIRECTION INOUT ;
    USE GROUND ;
    PORT
      LAYER met3 ;
        RECT -2.000 3977.710 0.300 4001.610 ;
    END
    PORT
      LAYER met3 ;
        RECT -2.000 3927.810 0.300 3951.710 ;
    END
  END vssa2
  PIN vssd
    DIRECTION INOUT ;
    USE GROUND ;
    PORT
      LAYER met3 ;
        RECT 4633.820 -2.000 4657.820 0.300 ;
    END
    PORT
      LAYER met3 ;
        RECT 4584.420 -2.000 4607.570 0.300 ;
    END
    PORT
      LAYER met3 ;
        RECT 1045.820 -2.000 1069.820 0.300 ;
    END
    PORT
      LAYER met3 ;
        RECT 996.420 -2.000 1019.570 0.300 ;
    END
  END vssd
  PIN vssd1
    DIRECTION INOUT ;
    USE GROUND ;
    PORT
      LAYER met3 ;
        RECT 6754.330 4353.050 6756.630 4376.360 ;
    END
    PORT
      LAYER met3 ;
        RECT 6754.330 2138.810 6756.630 2162.810 ;
    END
    PORT
      LAYER met3 ;
        RECT 6754.330 2088.610 6756.630 2112.560 ;
    END
  END vssd1
  PIN vssd2
    DIRECTION INOUT ;
    USE GROUND ;
    PORT
      LAYER met3 ;
        RECT -2.000 4375.270 0.300 4398.580 ;
    END
    PORT
      LAYER met3 ;
        RECT -2.000 1993.810 0.300 2017.810 ;
    END
    PORT
      LAYER met3 ;
        RECT -2.000 2044.070 0.300 2068.020 ;
    END
  END vssd2
  PIN vssio
    DIRECTION INOUT ;
    USE GROUND ;
    PORT
      LAYER met3 ;
        RECT 6223.030 -2.000 6246.930 0.300 ;
    END
    PORT
      LAYER met3 ;
        RECT 6272.920 -2.000 6296.820 0.300 ;
    END
    PORT
      LAYER met3 ;
        RECT 2635.030 -2.000 2658.930 0.300 ;
    END
    PORT
      LAYER met3 ;
        RECT 2684.920 -2.000 2708.820 0.300 ;
    END
    PORT
      LAYER met3 ;
        RECT 5094.710 4766.330 5118.610 4768.630 ;
    END
    PORT
      LAYER met3 ;
        RECT 5044.810 4766.330 5068.710 4768.630 ;
    END
    PORT
      LAYER met3 ;
        RECT 1506.710 4766.330 1530.610 4768.630 ;
    END
    PORT
      LAYER met3 ;
        RECT 1456.810 4766.330 1480.710 4768.630 ;
    END
  END vssio







  OBS
      LAYER nwell ;
        RECT 3375.750 2379.915 3377.970 2385.525 ;
      LAYER li1 ;
        RECT 3375.940 2379.915 3377.780 2385.525 ;
      LAYER met1 ;
        RECT 40.020 40.560 6714.620 4724.880 ;
      LAYER met2 ;
        RECT 55.570 40.615 6540.410 4724.825 ;
      LAYER met3 ;
        RECT 55.550 40.635 6540.430 4724.805 ;
      LAYER met4 ;
        RECT 55.540 40.560 6580.040 4724.880 ;
      LAYER met5 ;
        RECT 40.020 56.650 6714.620 4601.150 ;
  END
END double_wide_openframe_project_wrapper
END LIBRARY

